VERSION 5.8 ;
BUSBITCHARS "[]" ;
DIVIDERCHAR "/" ;
UNITS
    DATABASE MICRONS 1000 ;
END UNITS

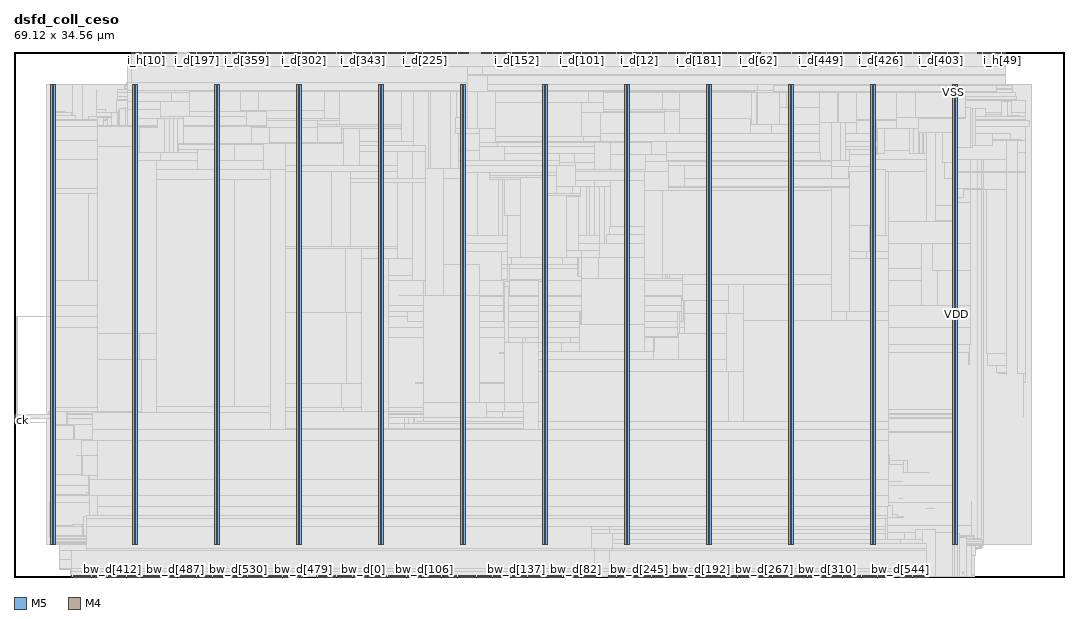
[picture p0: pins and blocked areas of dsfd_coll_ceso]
MACRO dsfd_coll_ceso
  FOREIGN dsfd_coll_ceso 0 0 ;
  CLASS BLOCK ;
  SIZE 69.12 BY 34.56 ;
  PIN bw_d[0]
    DIRECTION OUTPUT ;
    USE SIGNAL ;
    PORT
      LAYER M5 ;
        RECT  22.992 0 23.016 0.084 ;
    END
  END bw_d[0]
  PIN bw_d[100]
    DIRECTION OUTPUT ;
    USE SIGNAL ;
    PORT
      LAYER M5 ;
        RECT  26.448 0 26.472 0.084 ;
    END
  END bw_d[100]
  PIN bw_d[101]
    DIRECTION OUTPUT ;
    USE SIGNAL ;
    PORT
      LAYER M5 ;
        RECT  26.544 0 26.568 0.084 ;
    END
  END bw_d[101]
  PIN bw_d[102]
    DIRECTION OUTPUT ;
    USE SIGNAL ;
    PORT
      LAYER M5 ;
        RECT  26.64 0 26.664 0.084 ;
    END
  END bw_d[102]
  PIN bw_d[103]
    DIRECTION OUTPUT ;
    USE SIGNAL ;
    PORT
      LAYER M5 ;
        RECT  26.736 0 26.76 0.084 ;
    END
  END bw_d[103]
  PIN bw_d[104]
    DIRECTION OUTPUT ;
    USE SIGNAL ;
    PORT
      LAYER M5 ;
        RECT  26.832 0 26.856 0.084 ;
    END
  END bw_d[104]
  PIN bw_d[105]
    DIRECTION OUTPUT ;
    USE SIGNAL ;
    PORT
      LAYER M5 ;
        RECT  26.928 0 26.952 0.084 ;
    END
  END bw_d[105]
  PIN bw_d[106]
    DIRECTION OUTPUT ;
    USE SIGNAL ;
    PORT
      LAYER M5 ;
        RECT  27.024 0 27.048 0.084 ;
    END
  END bw_d[106]
  PIN bw_d[107]
    DIRECTION OUTPUT ;
    USE SIGNAL ;
    PORT
      LAYER M5 ;
        RECT  27.12 0 27.144 0.084 ;
    END
  END bw_d[107]
  PIN bw_d[108]
    DIRECTION OUTPUT ;
    USE SIGNAL ;
    PORT
      LAYER M5 ;
        RECT  27.216 0 27.24 0.084 ;
    END
  END bw_d[108]
  PIN bw_d[109]
    DIRECTION OUTPUT ;
    USE SIGNAL ;
    PORT
      LAYER M5 ;
        RECT  27.312 0 27.336 0.084 ;
    END
  END bw_d[109]
  PIN bw_d[10]
    DIRECTION OUTPUT ;
    USE SIGNAL ;
    PORT
      LAYER M5 ;
        RECT  23.952 0 23.976 0.084 ;
    END
  END bw_d[10]
  PIN bw_d[110]
    DIRECTION OUTPUT ;
    USE SIGNAL ;
    PORT
      LAYER M5 ;
        RECT  27.408 0 27.432 0.084 ;
    END
  END bw_d[110]
  PIN bw_d[111]
    DIRECTION OUTPUT ;
    USE SIGNAL ;
    PORT
      LAYER M5 ;
        RECT  27.504 0 27.528 0.084 ;
    END
  END bw_d[111]
  PIN bw_d[112]
    DIRECTION OUTPUT ;
    USE SIGNAL ;
    PORT
      LAYER M5 ;
        RECT  27.6 0 27.624 0.084 ;
    END
  END bw_d[112]
  PIN bw_d[113]
    DIRECTION OUTPUT ;
    USE SIGNAL ;
    PORT
      LAYER M5 ;
        RECT  27.696 0 27.72 0.084 ;
    END
  END bw_d[113]
  PIN bw_d[114]
    DIRECTION OUTPUT ;
    USE SIGNAL ;
    PORT
      LAYER M5 ;
        RECT  27.792 0 27.816 0.084 ;
    END
  END bw_d[114]
  PIN bw_d[115]
    DIRECTION OUTPUT ;
    USE SIGNAL ;
    PORT
      LAYER M5 ;
        RECT  27.888 0 27.912 0.084 ;
    END
  END bw_d[115]
  PIN bw_d[116]
    DIRECTION OUTPUT ;
    USE SIGNAL ;
    PORT
      LAYER M5 ;
        RECT  27.984 0 28.008 0.084 ;
    END
  END bw_d[116]
  PIN bw_d[117]
    DIRECTION OUTPUT ;
    USE SIGNAL ;
    PORT
      LAYER M5 ;
        RECT  28.08 0 28.104 0.084 ;
    END
  END bw_d[117]
  PIN bw_d[118]
    DIRECTION OUTPUT ;
    USE SIGNAL ;
    PORT
      LAYER M5 ;
        RECT  28.176 0 28.2 0.084 ;
    END
  END bw_d[118]
  PIN bw_d[119]
    DIRECTION OUTPUT ;
    USE SIGNAL ;
    PORT
      LAYER M5 ;
        RECT  28.272 0 28.296 0.084 ;
    END
  END bw_d[119]
  PIN bw_d[11]
    DIRECTION OUTPUT ;
    USE SIGNAL ;
    PORT
      LAYER M5 ;
        RECT  24.048 0 24.072 0.084 ;
    END
  END bw_d[11]
  PIN bw_d[120]
    DIRECTION OUTPUT ;
    USE SIGNAL ;
    PORT
      LAYER M5 ;
        RECT  28.368 0 28.392 0.084 ;
    END
  END bw_d[120]
  PIN bw_d[121]
    DIRECTION OUTPUT ;
    USE SIGNAL ;
    PORT
      LAYER M5 ;
        RECT  28.464 0 28.488 0.084 ;
    END
  END bw_d[121]
  PIN bw_d[122]
    DIRECTION OUTPUT ;
    USE SIGNAL ;
    PORT
      LAYER M5 ;
        RECT  28.56 0 28.584 0.084 ;
    END
  END bw_d[122]
  PIN bw_d[123]
    DIRECTION OUTPUT ;
    USE SIGNAL ;
    PORT
      LAYER M5 ;
        RECT  28.656 0 28.68 0.084 ;
    END
  END bw_d[123]
  PIN bw_d[124]
    DIRECTION OUTPUT ;
    USE SIGNAL ;
    PORT
      LAYER M5 ;
        RECT  28.752 0 28.776 0.084 ;
    END
  END bw_d[124]
  PIN bw_d[125]
    DIRECTION OUTPUT ;
    USE SIGNAL ;
    PORT
      LAYER M5 ;
        RECT  28.848 0 28.872 0.084 ;
    END
  END bw_d[125]
  PIN bw_d[126]
    DIRECTION OUTPUT ;
    USE SIGNAL ;
    PORT
      LAYER M5 ;
        RECT  28.944 0 28.968 0.084 ;
    END
  END bw_d[126]
  PIN bw_d[127]
    DIRECTION OUTPUT ;
    USE SIGNAL ;
    PORT
      LAYER M5 ;
        RECT  29.04 0 29.064 0.084 ;
    END
  END bw_d[127]
  PIN bw_d[128]
    DIRECTION OUTPUT ;
    USE SIGNAL ;
    PORT
      LAYER M5 ;
        RECT  32.208 0 32.232 0.084 ;
    END
  END bw_d[128]
  PIN bw_d[129]
    DIRECTION OUTPUT ;
    USE SIGNAL ;
    PORT
      LAYER M5 ;
        RECT  32.304 0 32.328 0.084 ;
    END
  END bw_d[129]
  PIN bw_d[12]
    DIRECTION OUTPUT ;
    USE SIGNAL ;
    PORT
      LAYER M5 ;
        RECT  24.144 0 24.168 0.084 ;
    END
  END bw_d[12]
  PIN bw_d[130]
    DIRECTION OUTPUT ;
    USE SIGNAL ;
    PORT
      LAYER M5 ;
        RECT  32.4 0 32.424 0.084 ;
    END
  END bw_d[130]
  PIN bw_d[131]
    DIRECTION OUTPUT ;
    USE SIGNAL ;
    PORT
      LAYER M5 ;
        RECT  32.496 0 32.52 0.084 ;
    END
  END bw_d[131]
  PIN bw_d[132]
    DIRECTION OUTPUT ;
    USE SIGNAL ;
    PORT
      LAYER M5 ;
        RECT  32.592 0 32.616 0.084 ;
    END
  END bw_d[132]
  PIN bw_d[133]
    DIRECTION OUTPUT ;
    USE SIGNAL ;
    PORT
      LAYER M5 ;
        RECT  32.688 0 32.712 0.084 ;
    END
  END bw_d[133]
  PIN bw_d[134]
    DIRECTION OUTPUT ;
    USE SIGNAL ;
    PORT
      LAYER M5 ;
        RECT  32.784 0 32.808 0.084 ;
    END
  END bw_d[134]
  PIN bw_d[135]
    DIRECTION OUTPUT ;
    USE SIGNAL ;
    PORT
      LAYER M5 ;
        RECT  32.88 0 32.904 0.084 ;
    END
  END bw_d[135]
  PIN bw_d[136]
    DIRECTION OUTPUT ;
    USE SIGNAL ;
    PORT
      LAYER M5 ;
        RECT  32.976 0 33 0.084 ;
    END
  END bw_d[136]
  PIN bw_d[137]
    DIRECTION OUTPUT ;
    USE SIGNAL ;
    PORT
      LAYER M5 ;
        RECT  33.072 0 33.096 0.084 ;
    END
  END bw_d[137]
  PIN bw_d[138]
    DIRECTION OUTPUT ;
    USE SIGNAL ;
    PORT
      LAYER M5 ;
        RECT  33.168 0 33.192 0.084 ;
    END
  END bw_d[138]
  PIN bw_d[139]
    DIRECTION OUTPUT ;
    USE SIGNAL ;
    PORT
      LAYER M5 ;
        RECT  33.264 0 33.288 0.084 ;
    END
  END bw_d[139]
  PIN bw_d[13]
    DIRECTION OUTPUT ;
    USE SIGNAL ;
    PORT
      LAYER M5 ;
        RECT  24.24 0 24.264 0.084 ;
    END
  END bw_d[13]
  PIN bw_d[140]
    DIRECTION OUTPUT ;
    USE SIGNAL ;
    PORT
      LAYER M5 ;
        RECT  33.36 0 33.384 0.084 ;
    END
  END bw_d[140]
  PIN bw_d[141]
    DIRECTION OUTPUT ;
    USE SIGNAL ;
    PORT
      LAYER M5 ;
        RECT  33.456 0 33.48 0.084 ;
    END
  END bw_d[141]
  PIN bw_d[142]
    DIRECTION OUTPUT ;
    USE SIGNAL ;
    PORT
      LAYER M5 ;
        RECT  33.552 0 33.576 0.084 ;
    END
  END bw_d[142]
  PIN bw_d[143]
    DIRECTION OUTPUT ;
    USE SIGNAL ;
    PORT
      LAYER M5 ;
        RECT  33.648 0 33.672 0.084 ;
    END
  END bw_d[143]
  PIN bw_d[144]
    DIRECTION OUTPUT ;
    USE SIGNAL ;
    PORT
      LAYER M5 ;
        RECT  33.744 0 33.768 0.084 ;
    END
  END bw_d[144]
  PIN bw_d[145]
    DIRECTION OUTPUT ;
    USE SIGNAL ;
    PORT
      LAYER M5 ;
        RECT  33.84 0 33.864 0.084 ;
    END
  END bw_d[145]
  PIN bw_d[146]
    DIRECTION OUTPUT ;
    USE SIGNAL ;
    PORT
      LAYER M5 ;
        RECT  33.936 0 33.96 0.084 ;
    END
  END bw_d[146]
  PIN bw_d[147]
    DIRECTION OUTPUT ;
    USE SIGNAL ;
    PORT
      LAYER M5 ;
        RECT  34.032 0 34.056 0.084 ;
    END
  END bw_d[147]
  PIN bw_d[148]
    DIRECTION OUTPUT ;
    USE SIGNAL ;
    PORT
      LAYER M5 ;
        RECT  34.128 0 34.152 0.084 ;
    END
  END bw_d[148]
  PIN bw_d[149]
    DIRECTION OUTPUT ;
    USE SIGNAL ;
    PORT
      LAYER M5 ;
        RECT  34.224 0 34.248 0.084 ;
    END
  END bw_d[149]
  PIN bw_d[14]
    DIRECTION OUTPUT ;
    USE SIGNAL ;
    PORT
      LAYER M5 ;
        RECT  24.336 0 24.36 0.084 ;
    END
  END bw_d[14]
  PIN bw_d[150]
    DIRECTION OUTPUT ;
    USE SIGNAL ;
    PORT
      LAYER M5 ;
        RECT  34.32 0 34.344 0.084 ;
    END
  END bw_d[150]
  PIN bw_d[151]
    DIRECTION OUTPUT ;
    USE SIGNAL ;
    PORT
      LAYER M5 ;
        RECT  34.416 0 34.44 0.084 ;
    END
  END bw_d[151]
  PIN bw_d[152]
    DIRECTION OUTPUT ;
    USE SIGNAL ;
    PORT
      LAYER M5 ;
        RECT  34.512 0 34.536 0.084 ;
    END
  END bw_d[152]
  PIN bw_d[153]
    DIRECTION OUTPUT ;
    USE SIGNAL ;
    PORT
      LAYER M5 ;
        RECT  34.608 0 34.632 0.084 ;
    END
  END bw_d[153]
  PIN bw_d[154]
    DIRECTION OUTPUT ;
    USE SIGNAL ;
    PORT
      LAYER M5 ;
        RECT  34.704 0 34.728 0.084 ;
    END
  END bw_d[154]
  PIN bw_d[155]
    DIRECTION OUTPUT ;
    USE SIGNAL ;
    PORT
      LAYER M5 ;
        RECT  34.8 0 34.824 0.084 ;
    END
  END bw_d[155]
  PIN bw_d[156]
    DIRECTION OUTPUT ;
    USE SIGNAL ;
    PORT
      LAYER M5 ;
        RECT  34.896 0 34.92 0.084 ;
    END
  END bw_d[156]
  PIN bw_d[157]
    DIRECTION OUTPUT ;
    USE SIGNAL ;
    PORT
      LAYER M5 ;
        RECT  34.992 0 35.016 0.084 ;
    END
  END bw_d[157]
  PIN bw_d[158]
    DIRECTION OUTPUT ;
    USE SIGNAL ;
    PORT
      LAYER M5 ;
        RECT  35.088 0 35.112 0.084 ;
    END
  END bw_d[158]
  PIN bw_d[159]
    DIRECTION OUTPUT ;
    USE SIGNAL ;
    PORT
      LAYER M5 ;
        RECT  35.184 0 35.208 0.084 ;
    END
  END bw_d[159]
  PIN bw_d[15]
    DIRECTION OUTPUT ;
    USE SIGNAL ;
    PORT
      LAYER M5 ;
        RECT  24.432 0 24.456 0.084 ;
    END
  END bw_d[15]
  PIN bw_d[160]
    DIRECTION OUTPUT ;
    USE SIGNAL ;
    PORT
      LAYER M5 ;
        RECT  29.136 0 29.16 0.084 ;
    END
  END bw_d[160]
  PIN bw_d[161]
    DIRECTION OUTPUT ;
    USE SIGNAL ;
    PORT
      LAYER M5 ;
        RECT  29.232 0 29.256 0.084 ;
    END
  END bw_d[161]
  PIN bw_d[162]
    DIRECTION OUTPUT ;
    USE SIGNAL ;
    PORT
      LAYER M5 ;
        RECT  29.328 0 29.352 0.084 ;
    END
  END bw_d[162]
  PIN bw_d[163]
    DIRECTION OUTPUT ;
    USE SIGNAL ;
    PORT
      LAYER M5 ;
        RECT  29.424 0 29.448 0.084 ;
    END
  END bw_d[163]
  PIN bw_d[164]
    DIRECTION OUTPUT ;
    USE SIGNAL ;
    PORT
      LAYER M5 ;
        RECT  29.52 0 29.544 0.084 ;
    END
  END bw_d[164]
  PIN bw_d[165]
    DIRECTION OUTPUT ;
    USE SIGNAL ;
    PORT
      LAYER M5 ;
        RECT  29.616 0 29.64 0.084 ;
    END
  END bw_d[165]
  PIN bw_d[166]
    DIRECTION OUTPUT ;
    USE SIGNAL ;
    PORT
      LAYER M5 ;
        RECT  29.712 0 29.736 0.084 ;
    END
  END bw_d[166]
  PIN bw_d[167]
    DIRECTION OUTPUT ;
    USE SIGNAL ;
    PORT
      LAYER M5 ;
        RECT  29.808 0 29.832 0.084 ;
    END
  END bw_d[167]
  PIN bw_d[168]
    DIRECTION OUTPUT ;
    USE SIGNAL ;
    PORT
      LAYER M5 ;
        RECT  29.904 0 29.928 0.084 ;
    END
  END bw_d[168]
  PIN bw_d[169]
    DIRECTION OUTPUT ;
    USE SIGNAL ;
    PORT
      LAYER M5 ;
        RECT  30 0 30.024 0.084 ;
    END
  END bw_d[169]
  PIN bw_d[16]
    DIRECTION OUTPUT ;
    USE SIGNAL ;
    PORT
      LAYER M5 ;
        RECT  24.528 0 24.552 0.084 ;
    END
  END bw_d[16]
  PIN bw_d[170]
    DIRECTION OUTPUT ;
    USE SIGNAL ;
    PORT
      LAYER M5 ;
        RECT  30.096 0 30.12 0.084 ;
    END
  END bw_d[170]
  PIN bw_d[171]
    DIRECTION OUTPUT ;
    USE SIGNAL ;
    PORT
      LAYER M5 ;
        RECT  30.192 0 30.216 0.084 ;
    END
  END bw_d[171]
  PIN bw_d[172]
    DIRECTION OUTPUT ;
    USE SIGNAL ;
    PORT
      LAYER M5 ;
        RECT  30.288 0 30.312 0.084 ;
    END
  END bw_d[172]
  PIN bw_d[173]
    DIRECTION OUTPUT ;
    USE SIGNAL ;
    PORT
      LAYER M5 ;
        RECT  30.384 0 30.408 0.084 ;
    END
  END bw_d[173]
  PIN bw_d[174]
    DIRECTION OUTPUT ;
    USE SIGNAL ;
    PORT
      LAYER M5 ;
        RECT  30.48 0 30.504 0.084 ;
    END
  END bw_d[174]
  PIN bw_d[175]
    DIRECTION OUTPUT ;
    USE SIGNAL ;
    PORT
      LAYER M5 ;
        RECT  30.576 0 30.6 0.084 ;
    END
  END bw_d[175]
  PIN bw_d[176]
    DIRECTION OUTPUT ;
    USE SIGNAL ;
    PORT
      LAYER M5 ;
        RECT  30.672 0 30.696 0.084 ;
    END
  END bw_d[176]
  PIN bw_d[177]
    DIRECTION OUTPUT ;
    USE SIGNAL ;
    PORT
      LAYER M5 ;
        RECT  30.768 0 30.792 0.084 ;
    END
  END bw_d[177]
  PIN bw_d[178]
    DIRECTION OUTPUT ;
    USE SIGNAL ;
    PORT
      LAYER M5 ;
        RECT  30.864 0 30.888 0.084 ;
    END
  END bw_d[178]
  PIN bw_d[179]
    DIRECTION OUTPUT ;
    USE SIGNAL ;
    PORT
      LAYER M5 ;
        RECT  30.96 0 30.984 0.084 ;
    END
  END bw_d[179]
  PIN bw_d[17]
    DIRECTION OUTPUT ;
    USE SIGNAL ;
    PORT
      LAYER M5 ;
        RECT  24.624 0 24.648 0.084 ;
    END
  END bw_d[17]
  PIN bw_d[180]
    DIRECTION OUTPUT ;
    USE SIGNAL ;
    PORT
      LAYER M5 ;
        RECT  31.056 0 31.08 0.084 ;
    END
  END bw_d[180]
  PIN bw_d[181]
    DIRECTION OUTPUT ;
    USE SIGNAL ;
    PORT
      LAYER M5 ;
        RECT  31.152 0 31.176 0.084 ;
    END
  END bw_d[181]
  PIN bw_d[182]
    DIRECTION OUTPUT ;
    USE SIGNAL ;
    PORT
      LAYER M5 ;
        RECT  31.248 0 31.272 0.084 ;
    END
  END bw_d[182]
  PIN bw_d[183]
    DIRECTION OUTPUT ;
    USE SIGNAL ;
    PORT
      LAYER M5 ;
        RECT  31.344 0 31.368 0.084 ;
    END
  END bw_d[183]
  PIN bw_d[184]
    DIRECTION OUTPUT ;
    USE SIGNAL ;
    PORT
      LAYER M5 ;
        RECT  31.44 0 31.464 0.084 ;
    END
  END bw_d[184]
  PIN bw_d[185]
    DIRECTION OUTPUT ;
    USE SIGNAL ;
    PORT
      LAYER M5 ;
        RECT  31.536 0 31.56 0.084 ;
    END
  END bw_d[185]
  PIN bw_d[186]
    DIRECTION OUTPUT ;
    USE SIGNAL ;
    PORT
      LAYER M5 ;
        RECT  31.632 0 31.656 0.084 ;
    END
  END bw_d[186]
  PIN bw_d[187]
    DIRECTION OUTPUT ;
    USE SIGNAL ;
    PORT
      LAYER M5 ;
        RECT  31.728 0 31.752 0.084 ;
    END
  END bw_d[187]
  PIN bw_d[188]
    DIRECTION OUTPUT ;
    USE SIGNAL ;
    PORT
      LAYER M5 ;
        RECT  31.824 0 31.848 0.084 ;
    END
  END bw_d[188]
  PIN bw_d[189]
    DIRECTION OUTPUT ;
    USE SIGNAL ;
    PORT
      LAYER M5 ;
        RECT  31.92 0 31.944 0.084 ;
    END
  END bw_d[189]
  PIN bw_d[18]
    DIRECTION OUTPUT ;
    USE SIGNAL ;
    PORT
      LAYER M5 ;
        RECT  24.72 0 24.744 0.084 ;
    END
  END bw_d[18]
  PIN bw_d[190]
    DIRECTION OUTPUT ;
    USE SIGNAL ;
    PORT
      LAYER M5 ;
        RECT  32.016 0 32.04 0.084 ;
    END
  END bw_d[190]
  PIN bw_d[191]
    DIRECTION OUTPUT ;
    USE SIGNAL ;
    PORT
      LAYER M5 ;
        RECT  32.112 0 32.136 0.084 ;
    END
  END bw_d[191]
  PIN bw_d[192]
    DIRECTION OUTPUT ;
    USE SIGNAL ;
    PORT
      LAYER M5 ;
        RECT  45.264 0 45.288 0.084 ;
    END
  END bw_d[192]
  PIN bw_d[193]
    DIRECTION OUTPUT ;
    USE SIGNAL ;
    PORT
      LAYER M5 ;
        RECT  45.36 0 45.384 0.084 ;
    END
  END bw_d[193]
  PIN bw_d[194]
    DIRECTION OUTPUT ;
    USE SIGNAL ;
    PORT
      LAYER M5 ;
        RECT  45.456 0 45.48 0.084 ;
    END
  END bw_d[194]
  PIN bw_d[195]
    DIRECTION OUTPUT ;
    USE SIGNAL ;
    PORT
      LAYER M5 ;
        RECT  45.552 0 45.576 0.084 ;
    END
  END bw_d[195]
  PIN bw_d[196]
    DIRECTION OUTPUT ;
    USE SIGNAL ;
    PORT
      LAYER M5 ;
        RECT  45.648 0 45.672 0.084 ;
    END
  END bw_d[196]
  PIN bw_d[197]
    DIRECTION OUTPUT ;
    USE SIGNAL ;
    PORT
      LAYER M5 ;
        RECT  45.744 0 45.768 0.084 ;
    END
  END bw_d[197]
  PIN bw_d[198]
    DIRECTION OUTPUT ;
    USE SIGNAL ;
    PORT
      LAYER M5 ;
        RECT  45.84 0 45.864 0.084 ;
    END
  END bw_d[198]
  PIN bw_d[199]
    DIRECTION OUTPUT ;
    USE SIGNAL ;
    PORT
      LAYER M5 ;
        RECT  45.936 0 45.96 0.084 ;
    END
  END bw_d[199]
  PIN bw_d[19]
    DIRECTION OUTPUT ;
    USE SIGNAL ;
    PORT
      LAYER M5 ;
        RECT  24.816 0 24.84 0.084 ;
    END
  END bw_d[19]
  PIN bw_d[1]
    DIRECTION OUTPUT ;
    USE SIGNAL ;
    PORT
      LAYER M5 ;
        RECT  23.088 0 23.112 0.084 ;
    END
  END bw_d[1]
  PIN bw_d[200]
    DIRECTION OUTPUT ;
    USE SIGNAL ;
    PORT
      LAYER M5 ;
        RECT  46.032 0 46.056 0.084 ;
    END
  END bw_d[200]
  PIN bw_d[201]
    DIRECTION OUTPUT ;
    USE SIGNAL ;
    PORT
      LAYER M5 ;
        RECT  46.128 0 46.152 0.084 ;
    END
  END bw_d[201]
  PIN bw_d[202]
    DIRECTION OUTPUT ;
    USE SIGNAL ;
    PORT
      LAYER M5 ;
        RECT  46.224 0 46.248 0.084 ;
    END
  END bw_d[202]
  PIN bw_d[203]
    DIRECTION OUTPUT ;
    USE SIGNAL ;
    PORT
      LAYER M5 ;
        RECT  46.32 0 46.344 0.084 ;
    END
  END bw_d[203]
  PIN bw_d[204]
    DIRECTION OUTPUT ;
    USE SIGNAL ;
    PORT
      LAYER M5 ;
        RECT  46.416 0 46.44 0.084 ;
    END
  END bw_d[204]
  PIN bw_d[205]
    DIRECTION OUTPUT ;
    USE SIGNAL ;
    PORT
      LAYER M5 ;
        RECT  46.512 0 46.536 0.084 ;
    END
  END bw_d[205]
  PIN bw_d[206]
    DIRECTION OUTPUT ;
    USE SIGNAL ;
    PORT
      LAYER M5 ;
        RECT  46.608 0 46.632 0.084 ;
    END
  END bw_d[206]
  PIN bw_d[207]
    DIRECTION OUTPUT ;
    USE SIGNAL ;
    PORT
      LAYER M5 ;
        RECT  46.704 0 46.728 0.084 ;
    END
  END bw_d[207]
  PIN bw_d[208]
    DIRECTION OUTPUT ;
    USE SIGNAL ;
    PORT
      LAYER M5 ;
        RECT  46.8 0 46.824 0.084 ;
    END
  END bw_d[208]
  PIN bw_d[209]
    DIRECTION OUTPUT ;
    USE SIGNAL ;
    PORT
      LAYER M5 ;
        RECT  46.896 0 46.92 0.084 ;
    END
  END bw_d[209]
  PIN bw_d[20]
    DIRECTION OUTPUT ;
    USE SIGNAL ;
    PORT
      LAYER M5 ;
        RECT  24.912 0 24.936 0.084 ;
    END
  END bw_d[20]
  PIN bw_d[210]
    DIRECTION OUTPUT ;
    USE SIGNAL ;
    PORT
      LAYER M5 ;
        RECT  46.992 0 47.016 0.084 ;
    END
  END bw_d[210]
  PIN bw_d[211]
    DIRECTION OUTPUT ;
    USE SIGNAL ;
    PORT
      LAYER M5 ;
        RECT  47.088 0 47.112 0.084 ;
    END
  END bw_d[211]
  PIN bw_d[212]
    DIRECTION OUTPUT ;
    USE SIGNAL ;
    PORT
      LAYER M5 ;
        RECT  47.184 0 47.208 0.084 ;
    END
  END bw_d[212]
  PIN bw_d[213]
    DIRECTION OUTPUT ;
    USE SIGNAL ;
    PORT
      LAYER M5 ;
        RECT  47.28 0 47.304 0.084 ;
    END
  END bw_d[213]
  PIN bw_d[214]
    DIRECTION OUTPUT ;
    USE SIGNAL ;
    PORT
      LAYER M5 ;
        RECT  47.376 0 47.4 0.084 ;
    END
  END bw_d[214]
  PIN bw_d[215]
    DIRECTION OUTPUT ;
    USE SIGNAL ;
    PORT
      LAYER M5 ;
        RECT  47.472 0 47.496 0.084 ;
    END
  END bw_d[215]
  PIN bw_d[216]
    DIRECTION OUTPUT ;
    USE SIGNAL ;
    PORT
      LAYER M5 ;
        RECT  47.568 0 47.592 0.084 ;
    END
  END bw_d[216]
  PIN bw_d[217]
    DIRECTION OUTPUT ;
    USE SIGNAL ;
    PORT
      LAYER M5 ;
        RECT  47.664 0 47.688 0.084 ;
    END
  END bw_d[217]
  PIN bw_d[218]
    DIRECTION OUTPUT ;
    USE SIGNAL ;
    PORT
      LAYER M5 ;
        RECT  47.76 0 47.784 0.084 ;
    END
  END bw_d[218]
  PIN bw_d[219]
    DIRECTION OUTPUT ;
    USE SIGNAL ;
    PORT
      LAYER M5 ;
        RECT  47.856 0 47.88 0.084 ;
    END
  END bw_d[219]
  PIN bw_d[21]
    DIRECTION OUTPUT ;
    USE SIGNAL ;
    PORT
      LAYER M5 ;
        RECT  25.008 0 25.032 0.084 ;
    END
  END bw_d[21]
  PIN bw_d[220]
    DIRECTION OUTPUT ;
    USE SIGNAL ;
    PORT
      LAYER M5 ;
        RECT  47.952 0 47.976 0.084 ;
    END
  END bw_d[220]
  PIN bw_d[221]
    DIRECTION OUTPUT ;
    USE SIGNAL ;
    PORT
      LAYER M5 ;
        RECT  48.048 0 48.072 0.084 ;
    END
  END bw_d[221]
  PIN bw_d[222]
    DIRECTION OUTPUT ;
    USE SIGNAL ;
    PORT
      LAYER M5 ;
        RECT  48.144 0 48.168 0.084 ;
    END
  END bw_d[222]
  PIN bw_d[223]
    DIRECTION OUTPUT ;
    USE SIGNAL ;
    PORT
      LAYER M5 ;
        RECT  48.24 0 48.264 0.084 ;
    END
  END bw_d[223]
  PIN bw_d[224]
    DIRECTION OUTPUT ;
    USE SIGNAL ;
    PORT
      LAYER M5 ;
        RECT  39.12 0 39.144 0.084 ;
    END
  END bw_d[224]
  PIN bw_d[225]
    DIRECTION OUTPUT ;
    USE SIGNAL ;
    PORT
      LAYER M5 ;
        RECT  39.216 0 39.24 0.084 ;
    END
  END bw_d[225]
  PIN bw_d[226]
    DIRECTION OUTPUT ;
    USE SIGNAL ;
    PORT
      LAYER M5 ;
        RECT  39.312 0 39.336 0.084 ;
    END
  END bw_d[226]
  PIN bw_d[227]
    DIRECTION OUTPUT ;
    USE SIGNAL ;
    PORT
      LAYER M5 ;
        RECT  39.408 0 39.432 0.084 ;
    END
  END bw_d[227]
  PIN bw_d[228]
    DIRECTION OUTPUT ;
    USE SIGNAL ;
    PORT
      LAYER M5 ;
        RECT  39.504 0 39.528 0.084 ;
    END
  END bw_d[228]
  PIN bw_d[229]
    DIRECTION OUTPUT ;
    USE SIGNAL ;
    PORT
      LAYER M5 ;
        RECT  39.6 0 39.624 0.084 ;
    END
  END bw_d[229]
  PIN bw_d[22]
    DIRECTION OUTPUT ;
    USE SIGNAL ;
    PORT
      LAYER M5 ;
        RECT  25.104 0 25.128 0.084 ;
    END
  END bw_d[22]
  PIN bw_d[230]
    DIRECTION OUTPUT ;
    USE SIGNAL ;
    PORT
      LAYER M5 ;
        RECT  39.696 0 39.72 0.084 ;
    END
  END bw_d[230]
  PIN bw_d[231]
    DIRECTION OUTPUT ;
    USE SIGNAL ;
    PORT
      LAYER M5 ;
        RECT  39.792 0 39.816 0.084 ;
    END
  END bw_d[231]
  PIN bw_d[232]
    DIRECTION OUTPUT ;
    USE SIGNAL ;
    PORT
      LAYER M5 ;
        RECT  39.888 0 39.912 0.084 ;
    END
  END bw_d[232]
  PIN bw_d[233]
    DIRECTION OUTPUT ;
    USE SIGNAL ;
    PORT
      LAYER M5 ;
        RECT  39.984 0 40.008 0.084 ;
    END
  END bw_d[233]
  PIN bw_d[234]
    DIRECTION OUTPUT ;
    USE SIGNAL ;
    PORT
      LAYER M5 ;
        RECT  40.08 0 40.104 0.084 ;
    END
  END bw_d[234]
  PIN bw_d[235]
    DIRECTION OUTPUT ;
    USE SIGNAL ;
    PORT
      LAYER M5 ;
        RECT  40.176 0 40.2 0.084 ;
    END
  END bw_d[235]
  PIN bw_d[236]
    DIRECTION OUTPUT ;
    USE SIGNAL ;
    PORT
      LAYER M5 ;
        RECT  40.272 0 40.296 0.084 ;
    END
  END bw_d[236]
  PIN bw_d[237]
    DIRECTION OUTPUT ;
    USE SIGNAL ;
    PORT
      LAYER M5 ;
        RECT  40.368 0 40.392 0.084 ;
    END
  END bw_d[237]
  PIN bw_d[238]
    DIRECTION OUTPUT ;
    USE SIGNAL ;
    PORT
      LAYER M5 ;
        RECT  40.464 0 40.488 0.084 ;
    END
  END bw_d[238]
  PIN bw_d[239]
    DIRECTION OUTPUT ;
    USE SIGNAL ;
    PORT
      LAYER M5 ;
        RECT  40.56 0 40.584 0.084 ;
    END
  END bw_d[239]
  PIN bw_d[23]
    DIRECTION OUTPUT ;
    USE SIGNAL ;
    PORT
      LAYER M5 ;
        RECT  25.2 0 25.224 0.084 ;
    END
  END bw_d[23]
  PIN bw_d[240]
    DIRECTION OUTPUT ;
    USE SIGNAL ;
    PORT
      LAYER M5 ;
        RECT  40.656 0 40.68 0.084 ;
    END
  END bw_d[240]
  PIN bw_d[241]
    DIRECTION OUTPUT ;
    USE SIGNAL ;
    PORT
      LAYER M5 ;
        RECT  40.752 0 40.776 0.084 ;
    END
  END bw_d[241]
  PIN bw_d[242]
    DIRECTION OUTPUT ;
    USE SIGNAL ;
    PORT
      LAYER M5 ;
        RECT  40.848 0 40.872 0.084 ;
    END
  END bw_d[242]
  PIN bw_d[243]
    DIRECTION OUTPUT ;
    USE SIGNAL ;
    PORT
      LAYER M5 ;
        RECT  40.944 0 40.968 0.084 ;
    END
  END bw_d[243]
  PIN bw_d[244]
    DIRECTION OUTPUT ;
    USE SIGNAL ;
    PORT
      LAYER M5 ;
        RECT  41.04 0 41.064 0.084 ;
    END
  END bw_d[244]
  PIN bw_d[245]
    DIRECTION OUTPUT ;
    USE SIGNAL ;
    PORT
      LAYER M5 ;
        RECT  41.136 0 41.16 0.084 ;
    END
  END bw_d[245]
  PIN bw_d[246]
    DIRECTION OUTPUT ;
    USE SIGNAL ;
    PORT
      LAYER M5 ;
        RECT  41.232 0 41.256 0.084 ;
    END
  END bw_d[246]
  PIN bw_d[247]
    DIRECTION OUTPUT ;
    USE SIGNAL ;
    PORT
      LAYER M5 ;
        RECT  41.328 0 41.352 0.084 ;
    END
  END bw_d[247]
  PIN bw_d[248]
    DIRECTION OUTPUT ;
    USE SIGNAL ;
    PORT
      LAYER M5 ;
        RECT  41.424 0 41.448 0.084 ;
    END
  END bw_d[248]
  PIN bw_d[249]
    DIRECTION OUTPUT ;
    USE SIGNAL ;
    PORT
      LAYER M5 ;
        RECT  41.52 0 41.544 0.084 ;
    END
  END bw_d[249]
  PIN bw_d[24]
    DIRECTION OUTPUT ;
    USE SIGNAL ;
    PORT
      LAYER M5 ;
        RECT  25.296 0 25.32 0.084 ;
    END
  END bw_d[24]
  PIN bw_d[250]
    DIRECTION OUTPUT ;
    USE SIGNAL ;
    PORT
      LAYER M5 ;
        RECT  41.616 0 41.64 0.084 ;
    END
  END bw_d[250]
  PIN bw_d[251]
    DIRECTION OUTPUT ;
    USE SIGNAL ;
    PORT
      LAYER M5 ;
        RECT  41.712 0 41.736 0.084 ;
    END
  END bw_d[251]
  PIN bw_d[252]
    DIRECTION OUTPUT ;
    USE SIGNAL ;
    PORT
      LAYER M5 ;
        RECT  41.808 0 41.832 0.084 ;
    END
  END bw_d[252]
  PIN bw_d[253]
    DIRECTION OUTPUT ;
    USE SIGNAL ;
    PORT
      LAYER M5 ;
        RECT  41.904 0 41.928 0.084 ;
    END
  END bw_d[253]
  PIN bw_d[254]
    DIRECTION OUTPUT ;
    USE SIGNAL ;
    PORT
      LAYER M5 ;
        RECT  42 0 42.024 0.084 ;
    END
  END bw_d[254]
  PIN bw_d[255]
    DIRECTION OUTPUT ;
    USE SIGNAL ;
    PORT
      LAYER M5 ;
        RECT  42.096 0 42.12 0.084 ;
    END
  END bw_d[255]
  PIN bw_d[256]
    DIRECTION OUTPUT ;
    USE SIGNAL ;
    PORT
      LAYER M5 ;
        RECT  48.336 0 48.36 0.084 ;
    END
  END bw_d[256]
  PIN bw_d[257]
    DIRECTION OUTPUT ;
    USE SIGNAL ;
    PORT
      LAYER M5 ;
        RECT  48.432 0 48.456 0.084 ;
    END
  END bw_d[257]
  PIN bw_d[258]
    DIRECTION OUTPUT ;
    USE SIGNAL ;
    PORT
      LAYER M5 ;
        RECT  48.528 0 48.552 0.084 ;
    END
  END bw_d[258]
  PIN bw_d[259]
    DIRECTION OUTPUT ;
    USE SIGNAL ;
    PORT
      LAYER M5 ;
        RECT  48.624 0 48.648 0.084 ;
    END
  END bw_d[259]
  PIN bw_d[25]
    DIRECTION OUTPUT ;
    USE SIGNAL ;
    PORT
      LAYER M5 ;
        RECT  25.392 0 25.416 0.084 ;
    END
  END bw_d[25]
  PIN bw_d[260]
    DIRECTION OUTPUT ;
    USE SIGNAL ;
    PORT
      LAYER M5 ;
        RECT  48.72 0 48.744 0.084 ;
    END
  END bw_d[260]
  PIN bw_d[261]
    DIRECTION OUTPUT ;
    USE SIGNAL ;
    PORT
      LAYER M5 ;
        RECT  48.816 0 48.84 0.084 ;
    END
  END bw_d[261]
  PIN bw_d[262]
    DIRECTION OUTPUT ;
    USE SIGNAL ;
    PORT
      LAYER M5 ;
        RECT  48.912 0 48.936 0.084 ;
    END
  END bw_d[262]
  PIN bw_d[263]
    DIRECTION OUTPUT ;
    USE SIGNAL ;
    PORT
      LAYER M5 ;
        RECT  49.008 0 49.032 0.084 ;
    END
  END bw_d[263]
  PIN bw_d[264]
    DIRECTION OUTPUT ;
    USE SIGNAL ;
    PORT
      LAYER M5 ;
        RECT  49.104 0 49.128 0.084 ;
    END
  END bw_d[264]
  PIN bw_d[265]
    DIRECTION OUTPUT ;
    USE SIGNAL ;
    PORT
      LAYER M5 ;
        RECT  49.2 0 49.224 0.084 ;
    END
  END bw_d[265]
  PIN bw_d[266]
    DIRECTION OUTPUT ;
    USE SIGNAL ;
    PORT
      LAYER M5 ;
        RECT  49.296 0 49.32 0.084 ;
    END
  END bw_d[266]
  PIN bw_d[267]
    DIRECTION OUTPUT ;
    USE SIGNAL ;
    PORT
      LAYER M5 ;
        RECT  49.392 0 49.416 0.084 ;
    END
  END bw_d[267]
  PIN bw_d[268]
    DIRECTION OUTPUT ;
    USE SIGNAL ;
    PORT
      LAYER M5 ;
        RECT  49.488 0 49.512 0.084 ;
    END
  END bw_d[268]
  PIN bw_d[269]
    DIRECTION OUTPUT ;
    USE SIGNAL ;
    PORT
      LAYER M5 ;
        RECT  49.584 0 49.608 0.084 ;
    END
  END bw_d[269]
  PIN bw_d[26]
    DIRECTION OUTPUT ;
    USE SIGNAL ;
    PORT
      LAYER M5 ;
        RECT  25.488 0 25.512 0.084 ;
    END
  END bw_d[26]
  PIN bw_d[270]
    DIRECTION OUTPUT ;
    USE SIGNAL ;
    PORT
      LAYER M5 ;
        RECT  49.68 0 49.704 0.084 ;
    END
  END bw_d[270]
  PIN bw_d[271]
    DIRECTION OUTPUT ;
    USE SIGNAL ;
    PORT
      LAYER M5 ;
        RECT  49.776 0 49.8 0.084 ;
    END
  END bw_d[271]
  PIN bw_d[272]
    DIRECTION OUTPUT ;
    USE SIGNAL ;
    PORT
      LAYER M5 ;
        RECT  49.872 0 49.896 0.084 ;
    END
  END bw_d[272]
  PIN bw_d[273]
    DIRECTION OUTPUT ;
    USE SIGNAL ;
    PORT
      LAYER M5 ;
        RECT  49.968 0 49.992 0.084 ;
    END
  END bw_d[273]
  PIN bw_d[274]
    DIRECTION OUTPUT ;
    USE SIGNAL ;
    PORT
      LAYER M5 ;
        RECT  50.064 0 50.088 0.084 ;
    END
  END bw_d[274]
  PIN bw_d[275]
    DIRECTION OUTPUT ;
    USE SIGNAL ;
    PORT
      LAYER M5 ;
        RECT  50.16 0 50.184 0.084 ;
    END
  END bw_d[275]
  PIN bw_d[276]
    DIRECTION OUTPUT ;
    USE SIGNAL ;
    PORT
      LAYER M5 ;
        RECT  50.256 0 50.28 0.084 ;
    END
  END bw_d[276]
  PIN bw_d[277]
    DIRECTION OUTPUT ;
    USE SIGNAL ;
    PORT
      LAYER M5 ;
        RECT  50.352 0 50.376 0.084 ;
    END
  END bw_d[277]
  PIN bw_d[278]
    DIRECTION OUTPUT ;
    USE SIGNAL ;
    PORT
      LAYER M5 ;
        RECT  50.448 0 50.472 0.084 ;
    END
  END bw_d[278]
  PIN bw_d[279]
    DIRECTION OUTPUT ;
    USE SIGNAL ;
    PORT
      LAYER M5 ;
        RECT  50.544 0 50.568 0.084 ;
    END
  END bw_d[279]
  PIN bw_d[27]
    DIRECTION OUTPUT ;
    USE SIGNAL ;
    PORT
      LAYER M5 ;
        RECT  25.584 0 25.608 0.084 ;
    END
  END bw_d[27]
  PIN bw_d[280]
    DIRECTION OUTPUT ;
    USE SIGNAL ;
    PORT
      LAYER M5 ;
        RECT  50.64 0 50.664 0.084 ;
    END
  END bw_d[280]
  PIN bw_d[281]
    DIRECTION OUTPUT ;
    USE SIGNAL ;
    PORT
      LAYER M5 ;
        RECT  50.736 0 50.76 0.084 ;
    END
  END bw_d[281]
  PIN bw_d[282]
    DIRECTION OUTPUT ;
    USE SIGNAL ;
    PORT
      LAYER M5 ;
        RECT  50.832 0 50.856 0.084 ;
    END
  END bw_d[282]
  PIN bw_d[283]
    DIRECTION OUTPUT ;
    USE SIGNAL ;
    PORT
      LAYER M5 ;
        RECT  50.928 0 50.952 0.084 ;
    END
  END bw_d[283]
  PIN bw_d[284]
    DIRECTION OUTPUT ;
    USE SIGNAL ;
    PORT
      LAYER M5 ;
        RECT  51.024 0 51.048 0.084 ;
    END
  END bw_d[284]
  PIN bw_d[285]
    DIRECTION OUTPUT ;
    USE SIGNAL ;
    PORT
      LAYER M5 ;
        RECT  51.12 0 51.144 0.084 ;
    END
  END bw_d[285]
  PIN bw_d[286]
    DIRECTION OUTPUT ;
    USE SIGNAL ;
    PORT
      LAYER M5 ;
        RECT  51.216 0 51.24 0.084 ;
    END
  END bw_d[286]
  PIN bw_d[287]
    DIRECTION OUTPUT ;
    USE SIGNAL ;
    PORT
      LAYER M5 ;
        RECT  51.312 0 51.336 0.084 ;
    END
  END bw_d[287]
  PIN bw_d[288]
    DIRECTION OUTPUT ;
    USE SIGNAL ;
    PORT
      LAYER M5 ;
        RECT  51.408 0 51.432 0.084 ;
    END
  END bw_d[288]
  PIN bw_d[289]
    DIRECTION OUTPUT ;
    USE SIGNAL ;
    PORT
      LAYER M5 ;
        RECT  51.504 0 51.528 0.084 ;
    END
  END bw_d[289]
  PIN bw_d[28]
    DIRECTION OUTPUT ;
    USE SIGNAL ;
    PORT
      LAYER M5 ;
        RECT  25.68 0 25.704 0.084 ;
    END
  END bw_d[28]
  PIN bw_d[290]
    DIRECTION OUTPUT ;
    USE SIGNAL ;
    PORT
      LAYER M5 ;
        RECT  51.6 0 51.624 0.084 ;
    END
  END bw_d[290]
  PIN bw_d[291]
    DIRECTION OUTPUT ;
    USE SIGNAL ;
    PORT
      LAYER M5 ;
        RECT  51.696 0 51.72 0.084 ;
    END
  END bw_d[291]
  PIN bw_d[292]
    DIRECTION OUTPUT ;
    USE SIGNAL ;
    PORT
      LAYER M5 ;
        RECT  51.792 0 51.816 0.084 ;
    END
  END bw_d[292]
  PIN bw_d[293]
    DIRECTION OUTPUT ;
    USE SIGNAL ;
    PORT
      LAYER M5 ;
        RECT  51.888 0 51.912 0.084 ;
    END
  END bw_d[293]
  PIN bw_d[294]
    DIRECTION OUTPUT ;
    USE SIGNAL ;
    PORT
      LAYER M5 ;
        RECT  51.984 0 52.008 0.084 ;
    END
  END bw_d[294]
  PIN bw_d[295]
    DIRECTION OUTPUT ;
    USE SIGNAL ;
    PORT
      LAYER M5 ;
        RECT  52.08 0 52.104 0.084 ;
    END
  END bw_d[295]
  PIN bw_d[296]
    DIRECTION OUTPUT ;
    USE SIGNAL ;
    PORT
      LAYER M5 ;
        RECT  52.176 0 52.2 0.084 ;
    END
  END bw_d[296]
  PIN bw_d[297]
    DIRECTION OUTPUT ;
    USE SIGNAL ;
    PORT
      LAYER M5 ;
        RECT  52.272 0 52.296 0.084 ;
    END
  END bw_d[297]
  PIN bw_d[298]
    DIRECTION OUTPUT ;
    USE SIGNAL ;
    PORT
      LAYER M5 ;
        RECT  52.368 0 52.392 0.084 ;
    END
  END bw_d[298]
  PIN bw_d[299]
    DIRECTION OUTPUT ;
    USE SIGNAL ;
    PORT
      LAYER M5 ;
        RECT  52.464 0 52.488 0.084 ;
    END
  END bw_d[299]
  PIN bw_d[29]
    DIRECTION OUTPUT ;
    USE SIGNAL ;
    PORT
      LAYER M5 ;
        RECT  25.776 0 25.8 0.084 ;
    END
  END bw_d[29]
  PIN bw_d[2]
    DIRECTION OUTPUT ;
    USE SIGNAL ;
    PORT
      LAYER M5 ;
        RECT  23.184 0 23.208 0.084 ;
    END
  END bw_d[2]
  PIN bw_d[300]
    DIRECTION OUTPUT ;
    USE SIGNAL ;
    PORT
      LAYER M5 ;
        RECT  52.56 0 52.584 0.084 ;
    END
  END bw_d[300]
  PIN bw_d[301]
    DIRECTION OUTPUT ;
    USE SIGNAL ;
    PORT
      LAYER M5 ;
        RECT  52.656 0 52.68 0.084 ;
    END
  END bw_d[301]
  PIN bw_d[302]
    DIRECTION OUTPUT ;
    USE SIGNAL ;
    PORT
      LAYER M5 ;
        RECT  52.752 0 52.776 0.084 ;
    END
  END bw_d[302]
  PIN bw_d[303]
    DIRECTION OUTPUT ;
    USE SIGNAL ;
    PORT
      LAYER M5 ;
        RECT  52.848 0 52.872 0.084 ;
    END
  END bw_d[303]
  PIN bw_d[304]
    DIRECTION OUTPUT ;
    USE SIGNAL ;
    PORT
      LAYER M5 ;
        RECT  52.944 0 52.968 0.084 ;
    END
  END bw_d[304]
  PIN bw_d[305]
    DIRECTION OUTPUT ;
    USE SIGNAL ;
    PORT
      LAYER M5 ;
        RECT  53.04 0 53.064 0.084 ;
    END
  END bw_d[305]
  PIN bw_d[306]
    DIRECTION OUTPUT ;
    USE SIGNAL ;
    PORT
      LAYER M5 ;
        RECT  53.136 0 53.16 0.084 ;
    END
  END bw_d[306]
  PIN bw_d[307]
    DIRECTION OUTPUT ;
    USE SIGNAL ;
    PORT
      LAYER M5 ;
        RECT  53.232 0 53.256 0.084 ;
    END
  END bw_d[307]
  PIN bw_d[308]
    DIRECTION OUTPUT ;
    USE SIGNAL ;
    PORT
      LAYER M5 ;
        RECT  53.328 0 53.352 0.084 ;
    END
  END bw_d[308]
  PIN bw_d[309]
    DIRECTION OUTPUT ;
    USE SIGNAL ;
    PORT
      LAYER M5 ;
        RECT  53.424 0 53.448 0.084 ;
    END
  END bw_d[309]
  PIN bw_d[30]
    DIRECTION OUTPUT ;
    USE SIGNAL ;
    PORT
      LAYER M5 ;
        RECT  25.872 0 25.896 0.084 ;
    END
  END bw_d[30]
  PIN bw_d[310]
    DIRECTION OUTPUT ;
    USE SIGNAL ;
    PORT
      LAYER M5 ;
        RECT  53.52 0 53.544 0.084 ;
    END
  END bw_d[310]
  PIN bw_d[311]
    DIRECTION OUTPUT ;
    USE SIGNAL ;
    PORT
      LAYER M5 ;
        RECT  53.616 0 53.64 0.084 ;
    END
  END bw_d[311]
  PIN bw_d[312]
    DIRECTION OUTPUT ;
    USE SIGNAL ;
    PORT
      LAYER M5 ;
        RECT  53.712 0 53.736 0.084 ;
    END
  END bw_d[312]
  PIN bw_d[313]
    DIRECTION OUTPUT ;
    USE SIGNAL ;
    PORT
      LAYER M5 ;
        RECT  53.808 0 53.832 0.084 ;
    END
  END bw_d[313]
  PIN bw_d[314]
    DIRECTION OUTPUT ;
    USE SIGNAL ;
    PORT
      LAYER M5 ;
        RECT  53.904 0 53.928 0.084 ;
    END
  END bw_d[314]
  PIN bw_d[315]
    DIRECTION OUTPUT ;
    USE SIGNAL ;
    PORT
      LAYER M5 ;
        RECT  54 0 54.024 0.084 ;
    END
  END bw_d[315]
  PIN bw_d[316]
    DIRECTION OUTPUT ;
    USE SIGNAL ;
    PORT
      LAYER M5 ;
        RECT  54.096 0 54.12 0.084 ;
    END
  END bw_d[316]
  PIN bw_d[317]
    DIRECTION OUTPUT ;
    USE SIGNAL ;
    PORT
      LAYER M5 ;
        RECT  54.192 0 54.216 0.084 ;
    END
  END bw_d[317]
  PIN bw_d[318]
    DIRECTION OUTPUT ;
    USE SIGNAL ;
    PORT
      LAYER M5 ;
        RECT  54.288 0 54.312 0.084 ;
    END
  END bw_d[318]
  PIN bw_d[319]
    DIRECTION OUTPUT ;
    USE SIGNAL ;
    PORT
      LAYER M5 ;
        RECT  54.384 0 54.408 0.084 ;
    END
  END bw_d[319]
  PIN bw_d[31]
    DIRECTION OUTPUT ;
    USE SIGNAL ;
    PORT
      LAYER M5 ;
        RECT  25.968 0 25.992 0.084 ;
    END
  END bw_d[31]
  PIN bw_d[320]
    DIRECTION OUTPUT ;
    USE SIGNAL ;
    PORT
      LAYER M5 ;
        RECT  42.192 0 42.216 0.084 ;
    END
  END bw_d[320]
  PIN bw_d[321]
    DIRECTION OUTPUT ;
    USE SIGNAL ;
    PORT
      LAYER M5 ;
        RECT  42.288 0 42.312 0.084 ;
    END
  END bw_d[321]
  PIN bw_d[322]
    DIRECTION OUTPUT ;
    USE SIGNAL ;
    PORT
      LAYER M5 ;
        RECT  42.384 0 42.408 0.084 ;
    END
  END bw_d[322]
  PIN bw_d[323]
    DIRECTION OUTPUT ;
    USE SIGNAL ;
    PORT
      LAYER M5 ;
        RECT  42.48 0 42.504 0.084 ;
    END
  END bw_d[323]
  PIN bw_d[324]
    DIRECTION OUTPUT ;
    USE SIGNAL ;
    PORT
      LAYER M5 ;
        RECT  42.576 0 42.6 0.084 ;
    END
  END bw_d[324]
  PIN bw_d[325]
    DIRECTION OUTPUT ;
    USE SIGNAL ;
    PORT
      LAYER M5 ;
        RECT  42.672 0 42.696 0.084 ;
    END
  END bw_d[325]
  PIN bw_d[326]
    DIRECTION OUTPUT ;
    USE SIGNAL ;
    PORT
      LAYER M5 ;
        RECT  42.768 0 42.792 0.084 ;
    END
  END bw_d[326]
  PIN bw_d[327]
    DIRECTION OUTPUT ;
    USE SIGNAL ;
    PORT
      LAYER M5 ;
        RECT  42.864 0 42.888 0.084 ;
    END
  END bw_d[327]
  PIN bw_d[328]
    DIRECTION OUTPUT ;
    USE SIGNAL ;
    PORT
      LAYER M5 ;
        RECT  42.96 0 42.984 0.084 ;
    END
  END bw_d[328]
  PIN bw_d[329]
    DIRECTION OUTPUT ;
    USE SIGNAL ;
    PORT
      LAYER M5 ;
        RECT  43.056 0 43.08 0.084 ;
    END
  END bw_d[329]
  PIN bw_d[32]
    DIRECTION OUTPUT ;
    USE SIGNAL ;
    PORT
      LAYER M5 ;
        RECT  19.92 0 19.944 0.084 ;
    END
  END bw_d[32]
  PIN bw_d[330]
    DIRECTION OUTPUT ;
    USE SIGNAL ;
    PORT
      LAYER M5 ;
        RECT  43.152 0 43.176 0.084 ;
    END
  END bw_d[330]
  PIN bw_d[331]
    DIRECTION OUTPUT ;
    USE SIGNAL ;
    PORT
      LAYER M5 ;
        RECT  43.248 0 43.272 0.084 ;
    END
  END bw_d[331]
  PIN bw_d[332]
    DIRECTION OUTPUT ;
    USE SIGNAL ;
    PORT
      LAYER M5 ;
        RECT  43.344 0 43.368 0.084 ;
    END
  END bw_d[332]
  PIN bw_d[333]
    DIRECTION OUTPUT ;
    USE SIGNAL ;
    PORT
      LAYER M5 ;
        RECT  43.44 0 43.464 0.084 ;
    END
  END bw_d[333]
  PIN bw_d[334]
    DIRECTION OUTPUT ;
    USE SIGNAL ;
    PORT
      LAYER M5 ;
        RECT  43.536 0 43.56 0.084 ;
    END
  END bw_d[334]
  PIN bw_d[335]
    DIRECTION OUTPUT ;
    USE SIGNAL ;
    PORT
      LAYER M5 ;
        RECT  43.632 0 43.656 0.084 ;
    END
  END bw_d[335]
  PIN bw_d[336]
    DIRECTION OUTPUT ;
    USE SIGNAL ;
    PORT
      LAYER M5 ;
        RECT  43.728 0 43.752 0.084 ;
    END
  END bw_d[336]
  PIN bw_d[337]
    DIRECTION OUTPUT ;
    USE SIGNAL ;
    PORT
      LAYER M5 ;
        RECT  43.824 0 43.848 0.084 ;
    END
  END bw_d[337]
  PIN bw_d[338]
    DIRECTION OUTPUT ;
    USE SIGNAL ;
    PORT
      LAYER M5 ;
        RECT  43.92 0 43.944 0.084 ;
    END
  END bw_d[338]
  PIN bw_d[339]
    DIRECTION OUTPUT ;
    USE SIGNAL ;
    PORT
      LAYER M5 ;
        RECT  44.016 0 44.04 0.084 ;
    END
  END bw_d[339]
  PIN bw_d[33]
    DIRECTION OUTPUT ;
    USE SIGNAL ;
    PORT
      LAYER M5 ;
        RECT  20.016 0 20.04 0.084 ;
    END
  END bw_d[33]
  PIN bw_d[340]
    DIRECTION OUTPUT ;
    USE SIGNAL ;
    PORT
      LAYER M5 ;
        RECT  44.112 0 44.136 0.084 ;
    END
  END bw_d[340]
  PIN bw_d[341]
    DIRECTION OUTPUT ;
    USE SIGNAL ;
    PORT
      LAYER M5 ;
        RECT  44.208 0 44.232 0.084 ;
    END
  END bw_d[341]
  PIN bw_d[342]
    DIRECTION OUTPUT ;
    USE SIGNAL ;
    PORT
      LAYER M5 ;
        RECT  44.304 0 44.328 0.084 ;
    END
  END bw_d[342]
  PIN bw_d[343]
    DIRECTION OUTPUT ;
    USE SIGNAL ;
    PORT
      LAYER M5 ;
        RECT  44.4 0 44.424 0.084 ;
    END
  END bw_d[343]
  PIN bw_d[344]
    DIRECTION OUTPUT ;
    USE SIGNAL ;
    PORT
      LAYER M5 ;
        RECT  44.496 0 44.52 0.084 ;
    END
  END bw_d[344]
  PIN bw_d[345]
    DIRECTION OUTPUT ;
    USE SIGNAL ;
    PORT
      LAYER M5 ;
        RECT  44.592 0 44.616 0.084 ;
    END
  END bw_d[345]
  PIN bw_d[346]
    DIRECTION OUTPUT ;
    USE SIGNAL ;
    PORT
      LAYER M5 ;
        RECT  44.688 0 44.712 0.084 ;
    END
  END bw_d[346]
  PIN bw_d[347]
    DIRECTION OUTPUT ;
    USE SIGNAL ;
    PORT
      LAYER M5 ;
        RECT  44.784 0 44.808 0.084 ;
    END
  END bw_d[347]
  PIN bw_d[348]
    DIRECTION OUTPUT ;
    USE SIGNAL ;
    PORT
      LAYER M5 ;
        RECT  44.88 0 44.904 0.084 ;
    END
  END bw_d[348]
  PIN bw_d[349]
    DIRECTION OUTPUT ;
    USE SIGNAL ;
    PORT
      LAYER M5 ;
        RECT  44.976 0 45 0.084 ;
    END
  END bw_d[349]
  PIN bw_d[34]
    DIRECTION OUTPUT ;
    USE SIGNAL ;
    PORT
      LAYER M5 ;
        RECT  20.112 0 20.136 0.084 ;
    END
  END bw_d[34]
  PIN bw_d[350]
    DIRECTION OUTPUT ;
    USE SIGNAL ;
    PORT
      LAYER M5 ;
        RECT  45.072 0 45.096 0.084 ;
    END
  END bw_d[350]
  PIN bw_d[351]
    DIRECTION OUTPUT ;
    USE SIGNAL ;
    PORT
      LAYER M5 ;
        RECT  45.168 0 45.192 0.084 ;
    END
  END bw_d[351]
  PIN bw_d[352]
    DIRECTION OUTPUT ;
    USE SIGNAL ;
    PORT
      LAYER M5 ;
        RECT  54.48 0 54.504 0.084 ;
    END
  END bw_d[352]
  PIN bw_d[353]
    DIRECTION OUTPUT ;
    USE SIGNAL ;
    PORT
      LAYER M5 ;
        RECT  54.576 0 54.6 0.084 ;
    END
  END bw_d[353]
  PIN bw_d[354]
    DIRECTION OUTPUT ;
    USE SIGNAL ;
    PORT
      LAYER M5 ;
        RECT  54.672 0 54.696 0.084 ;
    END
  END bw_d[354]
  PIN bw_d[355]
    DIRECTION OUTPUT ;
    USE SIGNAL ;
    PORT
      LAYER M5 ;
        RECT  54.768 0 54.792 0.084 ;
    END
  END bw_d[355]
  PIN bw_d[356]
    DIRECTION OUTPUT ;
    USE SIGNAL ;
    PORT
      LAYER M5 ;
        RECT  54.864 0 54.888 0.084 ;
    END
  END bw_d[356]
  PIN bw_d[357]
    DIRECTION OUTPUT ;
    USE SIGNAL ;
    PORT
      LAYER M5 ;
        RECT  54.96 0 54.984 0.084 ;
    END
  END bw_d[357]
  PIN bw_d[358]
    DIRECTION OUTPUT ;
    USE SIGNAL ;
    PORT
      LAYER M5 ;
        RECT  55.056 0 55.08 0.084 ;
    END
  END bw_d[358]
  PIN bw_d[359]
    DIRECTION OUTPUT ;
    USE SIGNAL ;
    PORT
      LAYER M5 ;
        RECT  55.152 0 55.176 0.084 ;
    END
  END bw_d[359]
  PIN bw_d[35]
    DIRECTION OUTPUT ;
    USE SIGNAL ;
    PORT
      LAYER M5 ;
        RECT  20.208 0 20.232 0.084 ;
    END
  END bw_d[35]
  PIN bw_d[360]
    DIRECTION OUTPUT ;
    USE SIGNAL ;
    PORT
      LAYER M5 ;
        RECT  55.248 0 55.272 0.084 ;
    END
  END bw_d[360]
  PIN bw_d[361]
    DIRECTION OUTPUT ;
    USE SIGNAL ;
    PORT
      LAYER M5 ;
        RECT  55.344 0 55.368 0.084 ;
    END
  END bw_d[361]
  PIN bw_d[362]
    DIRECTION OUTPUT ;
    USE SIGNAL ;
    PORT
      LAYER M5 ;
        RECT  55.44 0 55.464 0.084 ;
    END
  END bw_d[362]
  PIN bw_d[363]
    DIRECTION OUTPUT ;
    USE SIGNAL ;
    PORT
      LAYER M5 ;
        RECT  55.536 0 55.56 0.084 ;
    END
  END bw_d[363]
  PIN bw_d[364]
    DIRECTION OUTPUT ;
    USE SIGNAL ;
    PORT
      LAYER M5 ;
        RECT  55.632 0 55.656 0.084 ;
    END
  END bw_d[364]
  PIN bw_d[365]
    DIRECTION OUTPUT ;
    USE SIGNAL ;
    PORT
      LAYER M5 ;
        RECT  55.728 0 55.752 0.084 ;
    END
  END bw_d[365]
  PIN bw_d[366]
    DIRECTION OUTPUT ;
    USE SIGNAL ;
    PORT
      LAYER M5 ;
        RECT  55.824 0 55.848 0.084 ;
    END
  END bw_d[366]
  PIN bw_d[367]
    DIRECTION OUTPUT ;
    USE SIGNAL ;
    PORT
      LAYER M5 ;
        RECT  55.92 0 55.944 0.084 ;
    END
  END bw_d[367]
  PIN bw_d[368]
    DIRECTION OUTPUT ;
    USE SIGNAL ;
    PORT
      LAYER M5 ;
        RECT  56.016 0 56.04 0.084 ;
    END
  END bw_d[368]
  PIN bw_d[369]
    DIRECTION OUTPUT ;
    USE SIGNAL ;
    PORT
      LAYER M5 ;
        RECT  56.112 0 56.136 0.084 ;
    END
  END bw_d[369]
  PIN bw_d[36]
    DIRECTION OUTPUT ;
    USE SIGNAL ;
    PORT
      LAYER M5 ;
        RECT  20.304 0 20.328 0.084 ;
    END
  END bw_d[36]
  PIN bw_d[370]
    DIRECTION OUTPUT ;
    USE SIGNAL ;
    PORT
      LAYER M5 ;
        RECT  56.208 0 56.232 0.084 ;
    END
  END bw_d[370]
  PIN bw_d[371]
    DIRECTION OUTPUT ;
    USE SIGNAL ;
    PORT
      LAYER M5 ;
        RECT  56.304 0 56.328 0.084 ;
    END
  END bw_d[371]
  PIN bw_d[372]
    DIRECTION OUTPUT ;
    USE SIGNAL ;
    PORT
      LAYER M5 ;
        RECT  56.4 0 56.424 0.084 ;
    END
  END bw_d[372]
  PIN bw_d[373]
    DIRECTION OUTPUT ;
    USE SIGNAL ;
    PORT
      LAYER M5 ;
        RECT  56.496 0 56.52 0.084 ;
    END
  END bw_d[373]
  PIN bw_d[374]
    DIRECTION OUTPUT ;
    USE SIGNAL ;
    PORT
      LAYER M5 ;
        RECT  56.592 0 56.616 0.084 ;
    END
  END bw_d[374]
  PIN bw_d[375]
    DIRECTION OUTPUT ;
    USE SIGNAL ;
    PORT
      LAYER M5 ;
        RECT  56.688 0 56.712 0.084 ;
    END
  END bw_d[375]
  PIN bw_d[376]
    DIRECTION OUTPUT ;
    USE SIGNAL ;
    PORT
      LAYER M5 ;
        RECT  56.784 0 56.808 0.084 ;
    END
  END bw_d[376]
  PIN bw_d[377]
    DIRECTION OUTPUT ;
    USE SIGNAL ;
    PORT
      LAYER M5 ;
        RECT  56.88 0 56.904 0.084 ;
    END
  END bw_d[377]
  PIN bw_d[378]
    DIRECTION OUTPUT ;
    USE SIGNAL ;
    PORT
      LAYER M5 ;
        RECT  56.976 0 57 0.084 ;
    END
  END bw_d[378]
  PIN bw_d[379]
    DIRECTION OUTPUT ;
    USE SIGNAL ;
    PORT
      LAYER M5 ;
        RECT  57.072 0 57.096 0.084 ;
    END
  END bw_d[379]
  PIN bw_d[37]
    DIRECTION OUTPUT ;
    USE SIGNAL ;
    PORT
      LAYER M5 ;
        RECT  20.4 0 20.424 0.084 ;
    END
  END bw_d[37]
  PIN bw_d[380]
    DIRECTION OUTPUT ;
    USE SIGNAL ;
    PORT
      LAYER M5 ;
        RECT  57.168 0 57.192 0.084 ;
    END
  END bw_d[380]
  PIN bw_d[381]
    DIRECTION OUTPUT ;
    USE SIGNAL ;
    PORT
      LAYER M5 ;
        RECT  57.264 0 57.288 0.084 ;
    END
  END bw_d[381]
  PIN bw_d[382]
    DIRECTION OUTPUT ;
    USE SIGNAL ;
    PORT
      LAYER M5 ;
        RECT  57.36 0 57.384 0.084 ;
    END
  END bw_d[382]
  PIN bw_d[383]
    DIRECTION OUTPUT ;
    USE SIGNAL ;
    PORT
      LAYER M5 ;
        RECT  57.456 0 57.48 0.084 ;
    END
  END bw_d[383]
  PIN bw_d[384]
    DIRECTION OUTPUT ;
    USE SIGNAL ;
    PORT
      LAYER M5 ;
        RECT  3.792 0 3.816 0.084 ;
    END
  END bw_d[384]
  PIN bw_d[385]
    DIRECTION OUTPUT ;
    USE SIGNAL ;
    PORT
      LAYER M5 ;
        RECT  3.888 0 3.912 0.084 ;
    END
  END bw_d[385]
  PIN bw_d[386]
    DIRECTION OUTPUT ;
    USE SIGNAL ;
    PORT
      LAYER M5 ;
        RECT  3.984 0 4.008 0.084 ;
    END
  END bw_d[386]
  PIN bw_d[387]
    DIRECTION OUTPUT ;
    USE SIGNAL ;
    PORT
      LAYER M5 ;
        RECT  4.08 0 4.104 0.084 ;
    END
  END bw_d[387]
  PIN bw_d[388]
    DIRECTION OUTPUT ;
    USE SIGNAL ;
    PORT
      LAYER M5 ;
        RECT  4.176 0 4.2 0.084 ;
    END
  END bw_d[388]
  PIN bw_d[389]
    DIRECTION OUTPUT ;
    USE SIGNAL ;
    PORT
      LAYER M5 ;
        RECT  4.272 0 4.296 0.084 ;
    END
  END bw_d[389]
  PIN bw_d[38]
    DIRECTION OUTPUT ;
    USE SIGNAL ;
    PORT
      LAYER M5 ;
        RECT  20.496 0 20.52 0.084 ;
    END
  END bw_d[38]
  PIN bw_d[390]
    DIRECTION OUTPUT ;
    USE SIGNAL ;
    PORT
      LAYER M5 ;
        RECT  4.368 0 4.392 0.084 ;
    END
  END bw_d[390]
  PIN bw_d[391]
    DIRECTION OUTPUT ;
    USE SIGNAL ;
    PORT
      LAYER M5 ;
        RECT  4.464 0 4.488 0.084 ;
    END
  END bw_d[391]
  PIN bw_d[392]
    DIRECTION OUTPUT ;
    USE SIGNAL ;
    PORT
      LAYER M5 ;
        RECT  4.56 0 4.584 0.084 ;
    END
  END bw_d[392]
  PIN bw_d[393]
    DIRECTION OUTPUT ;
    USE SIGNAL ;
    PORT
      LAYER M5 ;
        RECT  4.656 0 4.68 0.084 ;
    END
  END bw_d[393]
  PIN bw_d[394]
    DIRECTION OUTPUT ;
    USE SIGNAL ;
    PORT
      LAYER M5 ;
        RECT  4.752 0 4.776 0.084 ;
    END
  END bw_d[394]
  PIN bw_d[395]
    DIRECTION OUTPUT ;
    USE SIGNAL ;
    PORT
      LAYER M5 ;
        RECT  4.848 0 4.872 0.084 ;
    END
  END bw_d[395]
  PIN bw_d[396]
    DIRECTION OUTPUT ;
    USE SIGNAL ;
    PORT
      LAYER M5 ;
        RECT  4.944 0 4.968 0.084 ;
    END
  END bw_d[396]
  PIN bw_d[397]
    DIRECTION OUTPUT ;
    USE SIGNAL ;
    PORT
      LAYER M5 ;
        RECT  5.04 0 5.064 0.084 ;
    END
  END bw_d[397]
  PIN bw_d[398]
    DIRECTION OUTPUT ;
    USE SIGNAL ;
    PORT
      LAYER M5 ;
        RECT  5.136 0 5.16 0.084 ;
    END
  END bw_d[398]
  PIN bw_d[399]
    DIRECTION OUTPUT ;
    USE SIGNAL ;
    PORT
      LAYER M5 ;
        RECT  5.232 0 5.256 0.084 ;
    END
  END bw_d[399]
  PIN bw_d[39]
    DIRECTION OUTPUT ;
    USE SIGNAL ;
    PORT
      LAYER M5 ;
        RECT  20.592 0 20.616 0.084 ;
    END
  END bw_d[39]
  PIN bw_d[3]
    DIRECTION OUTPUT ;
    USE SIGNAL ;
    PORT
      LAYER M5 ;
        RECT  23.28 0 23.304 0.084 ;
    END
  END bw_d[3]
  PIN bw_d[400]
    DIRECTION OUTPUT ;
    USE SIGNAL ;
    PORT
      LAYER M5 ;
        RECT  5.328 0 5.352 0.084 ;
    END
  END bw_d[400]
  PIN bw_d[401]
    DIRECTION OUTPUT ;
    USE SIGNAL ;
    PORT
      LAYER M5 ;
        RECT  5.424 0 5.448 0.084 ;
    END
  END bw_d[401]
  PIN bw_d[402]
    DIRECTION OUTPUT ;
    USE SIGNAL ;
    PORT
      LAYER M5 ;
        RECT  5.52 0 5.544 0.084 ;
    END
  END bw_d[402]
  PIN bw_d[403]
    DIRECTION OUTPUT ;
    USE SIGNAL ;
    PORT
      LAYER M5 ;
        RECT  5.616 0 5.64 0.084 ;
    END
  END bw_d[403]
  PIN bw_d[404]
    DIRECTION OUTPUT ;
    USE SIGNAL ;
    PORT
      LAYER M5 ;
        RECT  5.712 0 5.736 0.084 ;
    END
  END bw_d[404]
  PIN bw_d[405]
    DIRECTION OUTPUT ;
    USE SIGNAL ;
    PORT
      LAYER M5 ;
        RECT  5.808 0 5.832 0.084 ;
    END
  END bw_d[405]
  PIN bw_d[406]
    DIRECTION OUTPUT ;
    USE SIGNAL ;
    PORT
      LAYER M5 ;
        RECT  5.904 0 5.928 0.084 ;
    END
  END bw_d[406]
  PIN bw_d[407]
    DIRECTION OUTPUT ;
    USE SIGNAL ;
    PORT
      LAYER M5 ;
        RECT  6 0 6.024 0.084 ;
    END
  END bw_d[407]
  PIN bw_d[408]
    DIRECTION OUTPUT ;
    USE SIGNAL ;
    PORT
      LAYER M5 ;
        RECT  6.096 0 6.12 0.084 ;
    END
  END bw_d[408]
  PIN bw_d[409]
    DIRECTION OUTPUT ;
    USE SIGNAL ;
    PORT
      LAYER M5 ;
        RECT  6.192 0 6.216 0.084 ;
    END
  END bw_d[409]
  PIN bw_d[40]
    DIRECTION OUTPUT ;
    USE SIGNAL ;
    PORT
      LAYER M5 ;
        RECT  20.688 0 20.712 0.084 ;
    END
  END bw_d[40]
  PIN bw_d[410]
    DIRECTION OUTPUT ;
    USE SIGNAL ;
    PORT
      LAYER M5 ;
        RECT  6.288 0 6.312 0.084 ;
    END
  END bw_d[410]
  PIN bw_d[411]
    DIRECTION OUTPUT ;
    USE SIGNAL ;
    PORT
      LAYER M5 ;
        RECT  6.384 0 6.408 0.084 ;
    END
  END bw_d[411]
  PIN bw_d[412]
    DIRECTION OUTPUT ;
    USE SIGNAL ;
    PORT
      LAYER M5 ;
        RECT  6.48 0 6.504 0.084 ;
    END
  END bw_d[412]
  PIN bw_d[413]
    DIRECTION OUTPUT ;
    USE SIGNAL ;
    PORT
      LAYER M5 ;
        RECT  6.576 0 6.6 0.084 ;
    END
  END bw_d[413]
  PIN bw_d[414]
    DIRECTION OUTPUT ;
    USE SIGNAL ;
    PORT
      LAYER M5 ;
        RECT  6.672 0 6.696 0.084 ;
    END
  END bw_d[414]
  PIN bw_d[415]
    DIRECTION OUTPUT ;
    USE SIGNAL ;
    PORT
      LAYER M5 ;
        RECT  6.768 0 6.792 0.084 ;
    END
  END bw_d[415]
  PIN bw_d[416]
    DIRECTION OUTPUT ;
    USE SIGNAL ;
    PORT
      LAYER M5 ;
        RECT  6.864 0 6.888 0.084 ;
    END
  END bw_d[416]
  PIN bw_d[417]
    DIRECTION OUTPUT ;
    USE SIGNAL ;
    PORT
      LAYER M5 ;
        RECT  6.96 0 6.984 0.084 ;
    END
  END bw_d[417]
  PIN bw_d[418]
    DIRECTION OUTPUT ;
    USE SIGNAL ;
    PORT
      LAYER M5 ;
        RECT  7.056 0 7.08 0.084 ;
    END
  END bw_d[418]
  PIN bw_d[419]
    DIRECTION OUTPUT ;
    USE SIGNAL ;
    PORT
      LAYER M5 ;
        RECT  7.152 0 7.176 0.084 ;
    END
  END bw_d[419]
  PIN bw_d[41]
    DIRECTION OUTPUT ;
    USE SIGNAL ;
    PORT
      LAYER M5 ;
        RECT  20.784 0 20.808 0.084 ;
    END
  END bw_d[41]
  PIN bw_d[420]
    DIRECTION OUTPUT ;
    USE SIGNAL ;
    PORT
      LAYER M5 ;
        RECT  7.248 0 7.272 0.084 ;
    END
  END bw_d[420]
  PIN bw_d[421]
    DIRECTION OUTPUT ;
    USE SIGNAL ;
    PORT
      LAYER M5 ;
        RECT  7.344 0 7.368 0.084 ;
    END
  END bw_d[421]
  PIN bw_d[422]
    DIRECTION OUTPUT ;
    USE SIGNAL ;
    PORT
      LAYER M5 ;
        RECT  7.44 0 7.464 0.084 ;
    END
  END bw_d[422]
  PIN bw_d[423]
    DIRECTION OUTPUT ;
    USE SIGNAL ;
    PORT
      LAYER M5 ;
        RECT  7.536 0 7.56 0.084 ;
    END
  END bw_d[423]
  PIN bw_d[424]
    DIRECTION OUTPUT ;
    USE SIGNAL ;
    PORT
      LAYER M5 ;
        RECT  7.632 0 7.656 0.084 ;
    END
  END bw_d[424]
  PIN bw_d[425]
    DIRECTION OUTPUT ;
    USE SIGNAL ;
    PORT
      LAYER M5 ;
        RECT  7.728 0 7.752 0.084 ;
    END
  END bw_d[425]
  PIN bw_d[426]
    DIRECTION OUTPUT ;
    USE SIGNAL ;
    PORT
      LAYER M5 ;
        RECT  7.824 0 7.848 0.084 ;
    END
  END bw_d[426]
  PIN bw_d[427]
    DIRECTION OUTPUT ;
    USE SIGNAL ;
    PORT
      LAYER M5 ;
        RECT  7.92 0 7.944 0.084 ;
    END
  END bw_d[427]
  PIN bw_d[428]
    DIRECTION OUTPUT ;
    USE SIGNAL ;
    PORT
      LAYER M5 ;
        RECT  8.016 0 8.04 0.084 ;
    END
  END bw_d[428]
  PIN bw_d[429]
    DIRECTION OUTPUT ;
    USE SIGNAL ;
    PORT
      LAYER M5 ;
        RECT  8.112 0 8.136 0.084 ;
    END
  END bw_d[429]
  PIN bw_d[42]
    DIRECTION OUTPUT ;
    USE SIGNAL ;
    PORT
      LAYER M5 ;
        RECT  20.88 0 20.904 0.084 ;
    END
  END bw_d[42]
  PIN bw_d[430]
    DIRECTION OUTPUT ;
    USE SIGNAL ;
    PORT
      LAYER M5 ;
        RECT  8.208 0 8.232 0.084 ;
    END
  END bw_d[430]
  PIN bw_d[431]
    DIRECTION OUTPUT ;
    USE SIGNAL ;
    PORT
      LAYER M5 ;
        RECT  8.304 0 8.328 0.084 ;
    END
  END bw_d[431]
  PIN bw_d[432]
    DIRECTION OUTPUT ;
    USE SIGNAL ;
    PORT
      LAYER M5 ;
        RECT  8.4 0 8.424 0.084 ;
    END
  END bw_d[432]
  PIN bw_d[433]
    DIRECTION OUTPUT ;
    USE SIGNAL ;
    PORT
      LAYER M5 ;
        RECT  8.496 0 8.52 0.084 ;
    END
  END bw_d[433]
  PIN bw_d[434]
    DIRECTION OUTPUT ;
    USE SIGNAL ;
    PORT
      LAYER M5 ;
        RECT  8.592 0 8.616 0.084 ;
    END
  END bw_d[434]
  PIN bw_d[435]
    DIRECTION OUTPUT ;
    USE SIGNAL ;
    PORT
      LAYER M5 ;
        RECT  8.688 0 8.712 0.084 ;
    END
  END bw_d[435]
  PIN bw_d[436]
    DIRECTION OUTPUT ;
    USE SIGNAL ;
    PORT
      LAYER M5 ;
        RECT  8.784 0 8.808 0.084 ;
    END
  END bw_d[436]
  PIN bw_d[437]
    DIRECTION OUTPUT ;
    USE SIGNAL ;
    PORT
      LAYER M5 ;
        RECT  8.88 0 8.904 0.084 ;
    END
  END bw_d[437]
  PIN bw_d[438]
    DIRECTION OUTPUT ;
    USE SIGNAL ;
    PORT
      LAYER M5 ;
        RECT  8.976 0 9 0.084 ;
    END
  END bw_d[438]
  PIN bw_d[439]
    DIRECTION OUTPUT ;
    USE SIGNAL ;
    PORT
      LAYER M5 ;
        RECT  9.072 0 9.096 0.084 ;
    END
  END bw_d[439]
  PIN bw_d[43]
    DIRECTION OUTPUT ;
    USE SIGNAL ;
    PORT
      LAYER M5 ;
        RECT  20.976 0 21 0.084 ;
    END
  END bw_d[43]
  PIN bw_d[440]
    DIRECTION OUTPUT ;
    USE SIGNAL ;
    PORT
      LAYER M5 ;
        RECT  9.168 0 9.192 0.084 ;
    END
  END bw_d[440]
  PIN bw_d[441]
    DIRECTION OUTPUT ;
    USE SIGNAL ;
    PORT
      LAYER M5 ;
        RECT  9.264 0 9.288 0.084 ;
    END
  END bw_d[441]
  PIN bw_d[442]
    DIRECTION OUTPUT ;
    USE SIGNAL ;
    PORT
      LAYER M5 ;
        RECT  9.36 0 9.384 0.084 ;
    END
  END bw_d[442]
  PIN bw_d[443]
    DIRECTION OUTPUT ;
    USE SIGNAL ;
    PORT
      LAYER M5 ;
        RECT  9.456 0 9.48 0.084 ;
    END
  END bw_d[443]
  PIN bw_d[444]
    DIRECTION OUTPUT ;
    USE SIGNAL ;
    PORT
      LAYER M5 ;
        RECT  9.552 0 9.576 0.084 ;
    END
  END bw_d[444]
  PIN bw_d[445]
    DIRECTION OUTPUT ;
    USE SIGNAL ;
    PORT
      LAYER M5 ;
        RECT  9.648 0 9.672 0.084 ;
    END
  END bw_d[445]
  PIN bw_d[446]
    DIRECTION OUTPUT ;
    USE SIGNAL ;
    PORT
      LAYER M5 ;
        RECT  9.744 0 9.768 0.084 ;
    END
  END bw_d[446]
  PIN bw_d[447]
    DIRECTION OUTPUT ;
    USE SIGNAL ;
    PORT
      LAYER M5 ;
        RECT  9.84 0 9.864 0.084 ;
    END
  END bw_d[447]
  PIN bw_d[448]
    DIRECTION OUTPUT ;
    USE SIGNAL ;
    PORT
      LAYER M5 ;
        RECT  16.08 0 16.104 0.084 ;
    END
  END bw_d[448]
  PIN bw_d[449]
    DIRECTION OUTPUT ;
    USE SIGNAL ;
    PORT
      LAYER M5 ;
        RECT  16.176 0 16.2 0.084 ;
    END
  END bw_d[449]
  PIN bw_d[44]
    DIRECTION OUTPUT ;
    USE SIGNAL ;
    PORT
      LAYER M5 ;
        RECT  21.072 0 21.096 0.084 ;
    END
  END bw_d[44]
  PIN bw_d[450]
    DIRECTION OUTPUT ;
    USE SIGNAL ;
    PORT
      LAYER M5 ;
        RECT  16.272 0 16.296 0.084 ;
    END
  END bw_d[450]
  PIN bw_d[451]
    DIRECTION OUTPUT ;
    USE SIGNAL ;
    PORT
      LAYER M5 ;
        RECT  16.368 0 16.392 0.084 ;
    END
  END bw_d[451]
  PIN bw_d[452]
    DIRECTION OUTPUT ;
    USE SIGNAL ;
    PORT
      LAYER M5 ;
        RECT  16.464 0 16.488 0.084 ;
    END
  END bw_d[452]
  PIN bw_d[453]
    DIRECTION OUTPUT ;
    USE SIGNAL ;
    PORT
      LAYER M5 ;
        RECT  16.56 0 16.584 0.084 ;
    END
  END bw_d[453]
  PIN bw_d[454]
    DIRECTION OUTPUT ;
    USE SIGNAL ;
    PORT
      LAYER M5 ;
        RECT  16.656 0 16.68 0.084 ;
    END
  END bw_d[454]
  PIN bw_d[455]
    DIRECTION OUTPUT ;
    USE SIGNAL ;
    PORT
      LAYER M5 ;
        RECT  16.752 0 16.776 0.084 ;
    END
  END bw_d[455]
  PIN bw_d[456]
    DIRECTION OUTPUT ;
    USE SIGNAL ;
    PORT
      LAYER M5 ;
        RECT  16.848 0 16.872 0.084 ;
    END
  END bw_d[456]
  PIN bw_d[457]
    DIRECTION OUTPUT ;
    USE SIGNAL ;
    PORT
      LAYER M5 ;
        RECT  16.944 0 16.968 0.084 ;
    END
  END bw_d[457]
  PIN bw_d[458]
    DIRECTION OUTPUT ;
    USE SIGNAL ;
    PORT
      LAYER M5 ;
        RECT  17.04 0 17.064 0.084 ;
    END
  END bw_d[458]
  PIN bw_d[459]
    DIRECTION OUTPUT ;
    USE SIGNAL ;
    PORT
      LAYER M5 ;
        RECT  17.136 0 17.16 0.084 ;
    END
  END bw_d[459]
  PIN bw_d[45]
    DIRECTION OUTPUT ;
    USE SIGNAL ;
    PORT
      LAYER M5 ;
        RECT  21.168 0 21.192 0.084 ;
    END
  END bw_d[45]
  PIN bw_d[460]
    DIRECTION OUTPUT ;
    USE SIGNAL ;
    PORT
      LAYER M5 ;
        RECT  17.232 0 17.256 0.084 ;
    END
  END bw_d[460]
  PIN bw_d[461]
    DIRECTION OUTPUT ;
    USE SIGNAL ;
    PORT
      LAYER M5 ;
        RECT  17.328 0 17.352 0.084 ;
    END
  END bw_d[461]
  PIN bw_d[462]
    DIRECTION OUTPUT ;
    USE SIGNAL ;
    PORT
      LAYER M5 ;
        RECT  17.424 0 17.448 0.084 ;
    END
  END bw_d[462]
  PIN bw_d[463]
    DIRECTION OUTPUT ;
    USE SIGNAL ;
    PORT
      LAYER M5 ;
        RECT  17.52 0 17.544 0.084 ;
    END
  END bw_d[463]
  PIN bw_d[464]
    DIRECTION OUTPUT ;
    USE SIGNAL ;
    PORT
      LAYER M5 ;
        RECT  17.616 0 17.64 0.084 ;
    END
  END bw_d[464]
  PIN bw_d[465]
    DIRECTION OUTPUT ;
    USE SIGNAL ;
    PORT
      LAYER M5 ;
        RECT  17.712 0 17.736 0.084 ;
    END
  END bw_d[465]
  PIN bw_d[466]
    DIRECTION OUTPUT ;
    USE SIGNAL ;
    PORT
      LAYER M5 ;
        RECT  17.808 0 17.832 0.084 ;
    END
  END bw_d[466]
  PIN bw_d[467]
    DIRECTION OUTPUT ;
    USE SIGNAL ;
    PORT
      LAYER M5 ;
        RECT  17.904 0 17.928 0.084 ;
    END
  END bw_d[467]
  PIN bw_d[468]
    DIRECTION OUTPUT ;
    USE SIGNAL ;
    PORT
      LAYER M5 ;
        RECT  18 0 18.024 0.084 ;
    END
  END bw_d[468]
  PIN bw_d[469]
    DIRECTION OUTPUT ;
    USE SIGNAL ;
    PORT
      LAYER M5 ;
        RECT  18.096 0 18.12 0.084 ;
    END
  END bw_d[469]
  PIN bw_d[46]
    DIRECTION OUTPUT ;
    USE SIGNAL ;
    PORT
      LAYER M5 ;
        RECT  21.264 0 21.288 0.084 ;
    END
  END bw_d[46]
  PIN bw_d[470]
    DIRECTION OUTPUT ;
    USE SIGNAL ;
    PORT
      LAYER M5 ;
        RECT  18.192 0 18.216 0.084 ;
    END
  END bw_d[470]
  PIN bw_d[471]
    DIRECTION OUTPUT ;
    USE SIGNAL ;
    PORT
      LAYER M5 ;
        RECT  18.288 0 18.312 0.084 ;
    END
  END bw_d[471]
  PIN bw_d[472]
    DIRECTION OUTPUT ;
    USE SIGNAL ;
    PORT
      LAYER M5 ;
        RECT  18.384 0 18.408 0.084 ;
    END
  END bw_d[472]
  PIN bw_d[473]
    DIRECTION OUTPUT ;
    USE SIGNAL ;
    PORT
      LAYER M5 ;
        RECT  18.48 0 18.504 0.084 ;
    END
  END bw_d[473]
  PIN bw_d[474]
    DIRECTION OUTPUT ;
    USE SIGNAL ;
    PORT
      LAYER M5 ;
        RECT  18.576 0 18.6 0.084 ;
    END
  END bw_d[474]
  PIN bw_d[475]
    DIRECTION OUTPUT ;
    USE SIGNAL ;
    PORT
      LAYER M5 ;
        RECT  18.672 0 18.696 0.084 ;
    END
  END bw_d[475]
  PIN bw_d[476]
    DIRECTION OUTPUT ;
    USE SIGNAL ;
    PORT
      LAYER M5 ;
        RECT  18.768 0 18.792 0.084 ;
    END
  END bw_d[476]
  PIN bw_d[477]
    DIRECTION OUTPUT ;
    USE SIGNAL ;
    PORT
      LAYER M5 ;
        RECT  18.864 0 18.888 0.084 ;
    END
  END bw_d[477]
  PIN bw_d[478]
    DIRECTION OUTPUT ;
    USE SIGNAL ;
    PORT
      LAYER M5 ;
        RECT  18.96 0 18.984 0.084 ;
    END
  END bw_d[478]
  PIN bw_d[479]
    DIRECTION OUTPUT ;
    USE SIGNAL ;
    PORT
      LAYER M5 ;
        RECT  19.056 0 19.08 0.084 ;
    END
  END bw_d[479]
  PIN bw_d[47]
    DIRECTION OUTPUT ;
    USE SIGNAL ;
    PORT
      LAYER M5 ;
        RECT  21.36 0 21.384 0.084 ;
    END
  END bw_d[47]
  PIN bw_d[480]
    DIRECTION OUTPUT ;
    USE SIGNAL ;
    PORT
      LAYER M5 ;
        RECT  9.936 0 9.96 0.084 ;
    END
  END bw_d[480]
  PIN bw_d[481]
    DIRECTION OUTPUT ;
    USE SIGNAL ;
    PORT
      LAYER M5 ;
        RECT  10.032 0 10.056 0.084 ;
    END
  END bw_d[481]
  PIN bw_d[482]
    DIRECTION OUTPUT ;
    USE SIGNAL ;
    PORT
      LAYER M5 ;
        RECT  10.128 0 10.152 0.084 ;
    END
  END bw_d[482]
  PIN bw_d[483]
    DIRECTION OUTPUT ;
    USE SIGNAL ;
    PORT
      LAYER M5 ;
        RECT  10.224 0 10.248 0.084 ;
    END
  END bw_d[483]
  PIN bw_d[484]
    DIRECTION OUTPUT ;
    USE SIGNAL ;
    PORT
      LAYER M5 ;
        RECT  10.32 0 10.344 0.084 ;
    END
  END bw_d[484]
  PIN bw_d[485]
    DIRECTION OUTPUT ;
    USE SIGNAL ;
    PORT
      LAYER M5 ;
        RECT  10.416 0 10.44 0.084 ;
    END
  END bw_d[485]
  PIN bw_d[486]
    DIRECTION OUTPUT ;
    USE SIGNAL ;
    PORT
      LAYER M5 ;
        RECT  10.512 0 10.536 0.084 ;
    END
  END bw_d[486]
  PIN bw_d[487]
    DIRECTION OUTPUT ;
    USE SIGNAL ;
    PORT
      LAYER M5 ;
        RECT  10.608 0 10.632 0.084 ;
    END
  END bw_d[487]
  PIN bw_d[488]
    DIRECTION OUTPUT ;
    USE SIGNAL ;
    PORT
      LAYER M5 ;
        RECT  10.704 0 10.728 0.084 ;
    END
  END bw_d[488]
  PIN bw_d[489]
    DIRECTION OUTPUT ;
    USE SIGNAL ;
    PORT
      LAYER M5 ;
        RECT  10.8 0 10.824 0.084 ;
    END
  END bw_d[489]
  PIN bw_d[48]
    DIRECTION OUTPUT ;
    USE SIGNAL ;
    PORT
      LAYER M5 ;
        RECT  21.456 0 21.48 0.084 ;
    END
  END bw_d[48]
  PIN bw_d[490]
    DIRECTION OUTPUT ;
    USE SIGNAL ;
    PORT
      LAYER M5 ;
        RECT  10.896 0 10.92 0.084 ;
    END
  END bw_d[490]
  PIN bw_d[491]
    DIRECTION OUTPUT ;
    USE SIGNAL ;
    PORT
      LAYER M5 ;
        RECT  10.992 0 11.016 0.084 ;
    END
  END bw_d[491]
  PIN bw_d[492]
    DIRECTION OUTPUT ;
    USE SIGNAL ;
    PORT
      LAYER M5 ;
        RECT  11.088 0 11.112 0.084 ;
    END
  END bw_d[492]
  PIN bw_d[493]
    DIRECTION OUTPUT ;
    USE SIGNAL ;
    PORT
      LAYER M5 ;
        RECT  11.184 0 11.208 0.084 ;
    END
  END bw_d[493]
  PIN bw_d[494]
    DIRECTION OUTPUT ;
    USE SIGNAL ;
    PORT
      LAYER M5 ;
        RECT  11.28 0 11.304 0.084 ;
    END
  END bw_d[494]
  PIN bw_d[495]
    DIRECTION OUTPUT ;
    USE SIGNAL ;
    PORT
      LAYER M5 ;
        RECT  11.376 0 11.4 0.084 ;
    END
  END bw_d[495]
  PIN bw_d[496]
    DIRECTION OUTPUT ;
    USE SIGNAL ;
    PORT
      LAYER M5 ;
        RECT  11.472 0 11.496 0.084 ;
    END
  END bw_d[496]
  PIN bw_d[497]
    DIRECTION OUTPUT ;
    USE SIGNAL ;
    PORT
      LAYER M5 ;
        RECT  11.568 0 11.592 0.084 ;
    END
  END bw_d[497]
  PIN bw_d[498]
    DIRECTION OUTPUT ;
    USE SIGNAL ;
    PORT
      LAYER M5 ;
        RECT  11.664 0 11.688 0.084 ;
    END
  END bw_d[498]
  PIN bw_d[499]
    DIRECTION OUTPUT ;
    USE SIGNAL ;
    PORT
      LAYER M5 ;
        RECT  11.76 0 11.784 0.084 ;
    END
  END bw_d[499]
  PIN bw_d[49]
    DIRECTION OUTPUT ;
    USE SIGNAL ;
    PORT
      LAYER M5 ;
        RECT  21.552 0 21.576 0.084 ;
    END
  END bw_d[49]
  PIN bw_d[4]
    DIRECTION OUTPUT ;
    USE SIGNAL ;
    PORT
      LAYER M5 ;
        RECT  23.376 0 23.4 0.084 ;
    END
  END bw_d[4]
  PIN bw_d[500]
    DIRECTION OUTPUT ;
    USE SIGNAL ;
    PORT
      LAYER M5 ;
        RECT  11.856 0 11.88 0.084 ;
    END
  END bw_d[500]
  PIN bw_d[501]
    DIRECTION OUTPUT ;
    USE SIGNAL ;
    PORT
      LAYER M5 ;
        RECT  11.952 0 11.976 0.084 ;
    END
  END bw_d[501]
  PIN bw_d[502]
    DIRECTION OUTPUT ;
    USE SIGNAL ;
    PORT
      LAYER M5 ;
        RECT  12.048 0 12.072 0.084 ;
    END
  END bw_d[502]
  PIN bw_d[503]
    DIRECTION OUTPUT ;
    USE SIGNAL ;
    PORT
      LAYER M5 ;
        RECT  12.144 0 12.168 0.084 ;
    END
  END bw_d[503]
  PIN bw_d[504]
    DIRECTION OUTPUT ;
    USE SIGNAL ;
    PORT
      LAYER M5 ;
        RECT  12.24 0 12.264 0.084 ;
    END
  END bw_d[504]
  PIN bw_d[505]
    DIRECTION OUTPUT ;
    USE SIGNAL ;
    PORT
      LAYER M5 ;
        RECT  12.336 0 12.36 0.084 ;
    END
  END bw_d[505]
  PIN bw_d[506]
    DIRECTION OUTPUT ;
    USE SIGNAL ;
    PORT
      LAYER M5 ;
        RECT  12.432 0 12.456 0.084 ;
    END
  END bw_d[506]
  PIN bw_d[507]
    DIRECTION OUTPUT ;
    USE SIGNAL ;
    PORT
      LAYER M5 ;
        RECT  12.528 0 12.552 0.084 ;
    END
  END bw_d[507]
  PIN bw_d[508]
    DIRECTION OUTPUT ;
    USE SIGNAL ;
    PORT
      LAYER M5 ;
        RECT  12.624 0 12.648 0.084 ;
    END
  END bw_d[508]
  PIN bw_d[509]
    DIRECTION OUTPUT ;
    USE SIGNAL ;
    PORT
      LAYER M5 ;
        RECT  12.72 0 12.744 0.084 ;
    END
  END bw_d[509]
  PIN bw_d[50]
    DIRECTION OUTPUT ;
    USE SIGNAL ;
    PORT
      LAYER M5 ;
        RECT  21.648 0 21.672 0.084 ;
    END
  END bw_d[50]
  PIN bw_d[510]
    DIRECTION OUTPUT ;
    USE SIGNAL ;
    PORT
      LAYER M5 ;
        RECT  12.816 0 12.84 0.084 ;
    END
  END bw_d[510]
  PIN bw_d[511]
    DIRECTION OUTPUT ;
    USE SIGNAL ;
    PORT
      LAYER M5 ;
        RECT  12.912 0 12.936 0.084 ;
    END
  END bw_d[511]
  PIN bw_d[512]
    DIRECTION OUTPUT ;
    USE SIGNAL ;
    PORT
      LAYER M5 ;
        RECT  13.008 0 13.032 0.084 ;
    END
  END bw_d[512]
  PIN bw_d[513]
    DIRECTION OUTPUT ;
    USE SIGNAL ;
    PORT
      LAYER M5 ;
        RECT  13.104 0 13.128 0.084 ;
    END
  END bw_d[513]
  PIN bw_d[514]
    DIRECTION OUTPUT ;
    USE SIGNAL ;
    PORT
      LAYER M5 ;
        RECT  13.2 0 13.224 0.084 ;
    END
  END bw_d[514]
  PIN bw_d[515]
    DIRECTION OUTPUT ;
    USE SIGNAL ;
    PORT
      LAYER M5 ;
        RECT  13.296 0 13.32 0.084 ;
    END
  END bw_d[515]
  PIN bw_d[516]
    DIRECTION OUTPUT ;
    USE SIGNAL ;
    PORT
      LAYER M5 ;
        RECT  13.392 0 13.416 0.084 ;
    END
  END bw_d[516]
  PIN bw_d[517]
    DIRECTION OUTPUT ;
    USE SIGNAL ;
    PORT
      LAYER M5 ;
        RECT  13.488 0 13.512 0.084 ;
    END
  END bw_d[517]
  PIN bw_d[518]
    DIRECTION OUTPUT ;
    USE SIGNAL ;
    PORT
      LAYER M5 ;
        RECT  13.584 0 13.608 0.084 ;
    END
  END bw_d[518]
  PIN bw_d[519]
    DIRECTION OUTPUT ;
    USE SIGNAL ;
    PORT
      LAYER M5 ;
        RECT  13.68 0 13.704 0.084 ;
    END
  END bw_d[519]
  PIN bw_d[51]
    DIRECTION OUTPUT ;
    USE SIGNAL ;
    PORT
      LAYER M5 ;
        RECT  21.744 0 21.768 0.084 ;
    END
  END bw_d[51]
  PIN bw_d[520]
    DIRECTION OUTPUT ;
    USE SIGNAL ;
    PORT
      LAYER M5 ;
        RECT  13.776 0 13.8 0.084 ;
    END
  END bw_d[520]
  PIN bw_d[521]
    DIRECTION OUTPUT ;
    USE SIGNAL ;
    PORT
      LAYER M5 ;
        RECT  13.872 0 13.896 0.084 ;
    END
  END bw_d[521]
  PIN bw_d[522]
    DIRECTION OUTPUT ;
    USE SIGNAL ;
    PORT
      LAYER M5 ;
        RECT  13.968 0 13.992 0.084 ;
    END
  END bw_d[522]
  PIN bw_d[523]
    DIRECTION OUTPUT ;
    USE SIGNAL ;
    PORT
      LAYER M5 ;
        RECT  14.064 0 14.088 0.084 ;
    END
  END bw_d[523]
  PIN bw_d[524]
    DIRECTION OUTPUT ;
    USE SIGNAL ;
    PORT
      LAYER M5 ;
        RECT  14.16 0 14.184 0.084 ;
    END
  END bw_d[524]
  PIN bw_d[525]
    DIRECTION OUTPUT ;
    USE SIGNAL ;
    PORT
      LAYER M5 ;
        RECT  14.256 0 14.28 0.084 ;
    END
  END bw_d[525]
  PIN bw_d[526]
    DIRECTION OUTPUT ;
    USE SIGNAL ;
    PORT
      LAYER M5 ;
        RECT  14.352 0 14.376 0.084 ;
    END
  END bw_d[526]
  PIN bw_d[527]
    DIRECTION OUTPUT ;
    USE SIGNAL ;
    PORT
      LAYER M5 ;
        RECT  14.448 0 14.472 0.084 ;
    END
  END bw_d[527]
  PIN bw_d[528]
    DIRECTION OUTPUT ;
    USE SIGNAL ;
    PORT
      LAYER M5 ;
        RECT  14.544 0 14.568 0.084 ;
    END
  END bw_d[528]
  PIN bw_d[529]
    DIRECTION OUTPUT ;
    USE SIGNAL ;
    PORT
      LAYER M5 ;
        RECT  14.64 0 14.664 0.084 ;
    END
  END bw_d[529]
  PIN bw_d[52]
    DIRECTION OUTPUT ;
    USE SIGNAL ;
    PORT
      LAYER M5 ;
        RECT  21.84 0 21.864 0.084 ;
    END
  END bw_d[52]
  PIN bw_d[530]
    DIRECTION OUTPUT ;
    USE SIGNAL ;
    PORT
      LAYER M5 ;
        RECT  14.736 0 14.76 0.084 ;
    END
  END bw_d[530]
  PIN bw_d[531]
    DIRECTION OUTPUT ;
    USE SIGNAL ;
    PORT
      LAYER M5 ;
        RECT  14.832 0 14.856 0.084 ;
    END
  END bw_d[531]
  PIN bw_d[532]
    DIRECTION OUTPUT ;
    USE SIGNAL ;
    PORT
      LAYER M5 ;
        RECT  14.928 0 14.952 0.084 ;
    END
  END bw_d[532]
  PIN bw_d[533]
    DIRECTION OUTPUT ;
    USE SIGNAL ;
    PORT
      LAYER M5 ;
        RECT  15.024 0 15.048 0.084 ;
    END
  END bw_d[533]
  PIN bw_d[534]
    DIRECTION OUTPUT ;
    USE SIGNAL ;
    PORT
      LAYER M5 ;
        RECT  15.12 0 15.144 0.084 ;
    END
  END bw_d[534]
  PIN bw_d[535]
    DIRECTION OUTPUT ;
    USE SIGNAL ;
    PORT
      LAYER M5 ;
        RECT  15.216 0 15.24 0.084 ;
    END
  END bw_d[535]
  PIN bw_d[536]
    DIRECTION OUTPUT ;
    USE SIGNAL ;
    PORT
      LAYER M5 ;
        RECT  15.312 0 15.336 0.084 ;
    END
  END bw_d[536]
  PIN bw_d[537]
    DIRECTION OUTPUT ;
    USE SIGNAL ;
    PORT
      LAYER M5 ;
        RECT  15.408 0 15.432 0.084 ;
    END
  END bw_d[537]
  PIN bw_d[538]
    DIRECTION OUTPUT ;
    USE SIGNAL ;
    PORT
      LAYER M5 ;
        RECT  15.504 0 15.528 0.084 ;
    END
  END bw_d[538]
  PIN bw_d[539]
    DIRECTION OUTPUT ;
    USE SIGNAL ;
    PORT
      LAYER M5 ;
        RECT  15.6 0 15.624 0.084 ;
    END
  END bw_d[539]
  PIN bw_d[53]
    DIRECTION OUTPUT ;
    USE SIGNAL ;
    PORT
      LAYER M5 ;
        RECT  21.936 0 21.96 0.084 ;
    END
  END bw_d[53]
  PIN bw_d[540]
    DIRECTION OUTPUT ;
    USE SIGNAL ;
    PORT
      LAYER M5 ;
        RECT  15.696 0 15.72 0.084 ;
    END
  END bw_d[540]
  PIN bw_d[541]
    DIRECTION OUTPUT ;
    USE SIGNAL ;
    PORT
      LAYER M5 ;
        RECT  15.792 0 15.816 0.084 ;
    END
  END bw_d[541]
  PIN bw_d[542]
    DIRECTION OUTPUT ;
    USE SIGNAL ;
    PORT
      LAYER M5 ;
        RECT  15.888 0 15.912 0.084 ;
    END
  END bw_d[542]
  PIN bw_d[543]
    DIRECTION OUTPUT ;
    USE SIGNAL ;
    PORT
      LAYER M5 ;
        RECT  15.984 0 16.008 0.084 ;
    END
  END bw_d[543]
  PIN bw_d[544]
    DIRECTION OUTPUT ;
    USE SIGNAL ;
    PORT
      LAYER M5 ;
        RECT  58.32 0 58.344 0.084 ;
    END
  END bw_d[544]
  PIN bw_d[545]
    DIRECTION OUTPUT ;
    USE SIGNAL ;
    PORT
      LAYER M5 ;
        RECT  58.416 0 58.44 0.084 ;
    END
  END bw_d[545]
  PIN bw_d[546]
    DIRECTION OUTPUT ;
    USE SIGNAL ;
    PORT
      LAYER M5 ;
        RECT  58.512 0 58.536 0.084 ;
    END
  END bw_d[546]
  PIN bw_d[547]
    DIRECTION OUTPUT ;
    USE SIGNAL ;
    PORT
      LAYER M5 ;
        RECT  58.608 0 58.632 0.084 ;
    END
  END bw_d[547]
  PIN bw_d[548]
    DIRECTION OUTPUT ;
    USE SIGNAL ;
    PORT
      LAYER M5 ;
        RECT  58.704 0 58.728 0.084 ;
    END
  END bw_d[548]
  PIN bw_d[549]
    DIRECTION OUTPUT ;
    USE SIGNAL ;
    PORT
      LAYER M5 ;
        RECT  58.8 0 58.824 0.084 ;
    END
  END bw_d[549]
  PIN bw_d[54]
    DIRECTION OUTPUT ;
    USE SIGNAL ;
    PORT
      LAYER M5 ;
        RECT  22.032 0 22.056 0.084 ;
    END
  END bw_d[54]
  PIN bw_d[550]
    DIRECTION OUTPUT ;
    USE SIGNAL ;
    PORT
      LAYER M5 ;
        RECT  58.896 0 58.92 0.084 ;
    END
  END bw_d[550]
  PIN bw_d[551]
    DIRECTION OUTPUT ;
    USE SIGNAL ;
    PORT
      LAYER M5 ;
        RECT  58.992 0 59.016 0.084 ;
    END
  END bw_d[551]
  PIN bw_d[552]
    DIRECTION OUTPUT ;
    USE SIGNAL ;
    PORT
      LAYER M5 ;
        RECT  59.088 0 59.112 0.084 ;
    END
  END bw_d[552]
  PIN bw_d[553]
    DIRECTION OUTPUT ;
    USE SIGNAL ;
    PORT
      LAYER M5 ;
        RECT  59.184 0 59.208 0.084 ;
    END
  END bw_d[553]
  PIN bw_d[554]
    DIRECTION OUTPUT ;
    USE SIGNAL ;
    PORT
      LAYER M5 ;
        RECT  59.28 0 59.304 0.084 ;
    END
  END bw_d[554]
  PIN bw_d[555]
    DIRECTION OUTPUT ;
    USE SIGNAL ;
    PORT
      LAYER M5 ;
        RECT  59.376 0 59.4 0.084 ;
    END
  END bw_d[555]
  PIN bw_d[556]
    DIRECTION OUTPUT ;
    USE SIGNAL ;
    PORT
      LAYER M5 ;
        RECT  59.472 0 59.496 0.084 ;
    END
  END bw_d[556]
  PIN bw_d[557]
    DIRECTION OUTPUT ;
    USE SIGNAL ;
    PORT
      LAYER M5 ;
        RECT  59.568 0 59.592 0.084 ;
    END
  END bw_d[557]
  PIN bw_d[558]
    DIRECTION OUTPUT ;
    USE SIGNAL ;
    PORT
      LAYER M5 ;
        RECT  59.664 0 59.688 0.084 ;
    END
  END bw_d[558]
  PIN bw_d[559]
    DIRECTION OUTPUT ;
    USE SIGNAL ;
    PORT
      LAYER M5 ;
        RECT  59.76 0 59.784 0.084 ;
    END
  END bw_d[559]
  PIN bw_d[55]
    DIRECTION OUTPUT ;
    USE SIGNAL ;
    PORT
      LAYER M5 ;
        RECT  22.128 0 22.152 0.084 ;
    END
  END bw_d[55]
  PIN bw_d[560]
    DIRECTION OUTPUT ;
    USE SIGNAL ;
    PORT
      LAYER M5 ;
        RECT  59.856 0 59.88 0.084 ;
    END
  END bw_d[560]
  PIN bw_d[561]
    DIRECTION OUTPUT ;
    USE SIGNAL ;
    PORT
      LAYER M5 ;
        RECT  59.952 0 59.976 0.084 ;
    END
  END bw_d[561]
  PIN bw_d[562]
    DIRECTION OUTPUT ;
    USE SIGNAL ;
    PORT
      LAYER M5 ;
        RECT  60.048 0 60.072 0.084 ;
    END
  END bw_d[562]
  PIN bw_d[56]
    DIRECTION OUTPUT ;
    USE SIGNAL ;
    PORT
      LAYER M5 ;
        RECT  22.224 0 22.248 0.084 ;
    END
  END bw_d[56]
  PIN bw_d[57]
    DIRECTION OUTPUT ;
    USE SIGNAL ;
    PORT
      LAYER M5 ;
        RECT  22.32 0 22.344 0.084 ;
    END
  END bw_d[57]
  PIN bw_d[58]
    DIRECTION OUTPUT ;
    USE SIGNAL ;
    PORT
      LAYER M5 ;
        RECT  22.416 0 22.44 0.084 ;
    END
  END bw_d[58]
  PIN bw_d[59]
    DIRECTION OUTPUT ;
    USE SIGNAL ;
    PORT
      LAYER M5 ;
        RECT  22.512 0 22.536 0.084 ;
    END
  END bw_d[59]
  PIN bw_d[5]
    DIRECTION OUTPUT ;
    USE SIGNAL ;
    PORT
      LAYER M5 ;
        RECT  23.472 0 23.496 0.084 ;
    END
  END bw_d[5]
  PIN bw_d[60]
    DIRECTION OUTPUT ;
    USE SIGNAL ;
    PORT
      LAYER M5 ;
        RECT  22.608 0 22.632 0.084 ;
    END
  END bw_d[60]
  PIN bw_d[61]
    DIRECTION OUTPUT ;
    USE SIGNAL ;
    PORT
      LAYER M5 ;
        RECT  22.704 0 22.728 0.084 ;
    END
  END bw_d[61]
  PIN bw_d[62]
    DIRECTION OUTPUT ;
    USE SIGNAL ;
    PORT
      LAYER M5 ;
        RECT  22.8 0 22.824 0.084 ;
    END
  END bw_d[62]
  PIN bw_d[63]
    DIRECTION OUTPUT ;
    USE SIGNAL ;
    PORT
      LAYER M5 ;
        RECT  22.896 0 22.92 0.084 ;
    END
  END bw_d[63]
  PIN bw_d[64]
    DIRECTION OUTPUT ;
    USE SIGNAL ;
    PORT
      LAYER M5 ;
        RECT  35.28 0 35.304 0.084 ;
    END
  END bw_d[64]
  PIN bw_d[65]
    DIRECTION OUTPUT ;
    USE SIGNAL ;
    PORT
      LAYER M5 ;
        RECT  35.376 0 35.4 0.084 ;
    END
  END bw_d[65]
  PIN bw_d[66]
    DIRECTION OUTPUT ;
    USE SIGNAL ;
    PORT
      LAYER M5 ;
        RECT  35.472 0 35.496 0.084 ;
    END
  END bw_d[66]
  PIN bw_d[67]
    DIRECTION OUTPUT ;
    USE SIGNAL ;
    PORT
      LAYER M5 ;
        RECT  35.568 0 35.592 0.084 ;
    END
  END bw_d[67]
  PIN bw_d[68]
    DIRECTION OUTPUT ;
    USE SIGNAL ;
    PORT
      LAYER M5 ;
        RECT  35.664 0 35.688 0.084 ;
    END
  END bw_d[68]
  PIN bw_d[69]
    DIRECTION OUTPUT ;
    USE SIGNAL ;
    PORT
      LAYER M5 ;
        RECT  35.76 0 35.784 0.084 ;
    END
  END bw_d[69]
  PIN bw_d[6]
    DIRECTION OUTPUT ;
    USE SIGNAL ;
    PORT
      LAYER M5 ;
        RECT  23.568 0 23.592 0.084 ;
    END
  END bw_d[6]
  PIN bw_d[70]
    DIRECTION OUTPUT ;
    USE SIGNAL ;
    PORT
      LAYER M5 ;
        RECT  35.856 0 35.88 0.084 ;
    END
  END bw_d[70]
  PIN bw_d[71]
    DIRECTION OUTPUT ;
    USE SIGNAL ;
    PORT
      LAYER M5 ;
        RECT  35.952 0 35.976 0.084 ;
    END
  END bw_d[71]
  PIN bw_d[72]
    DIRECTION OUTPUT ;
    USE SIGNAL ;
    PORT
      LAYER M5 ;
        RECT  36.048 0 36.072 0.084 ;
    END
  END bw_d[72]
  PIN bw_d[73]
    DIRECTION OUTPUT ;
    USE SIGNAL ;
    PORT
      LAYER M5 ;
        RECT  36.144 0 36.168 0.084 ;
    END
  END bw_d[73]
  PIN bw_d[74]
    DIRECTION OUTPUT ;
    USE SIGNAL ;
    PORT
      LAYER M5 ;
        RECT  36.24 0 36.264 0.084 ;
    END
  END bw_d[74]
  PIN bw_d[75]
    DIRECTION OUTPUT ;
    USE SIGNAL ;
    PORT
      LAYER M5 ;
        RECT  36.336 0 36.36 0.084 ;
    END
  END bw_d[75]
  PIN bw_d[76]
    DIRECTION OUTPUT ;
    USE SIGNAL ;
    PORT
      LAYER M5 ;
        RECT  36.432 0 36.456 0.084 ;
    END
  END bw_d[76]
  PIN bw_d[77]
    DIRECTION OUTPUT ;
    USE SIGNAL ;
    PORT
      LAYER M5 ;
        RECT  36.528 0 36.552 0.084 ;
    END
  END bw_d[77]
  PIN bw_d[78]
    DIRECTION OUTPUT ;
    USE SIGNAL ;
    PORT
      LAYER M5 ;
        RECT  36.624 0 36.648 0.084 ;
    END
  END bw_d[78]
  PIN bw_d[79]
    DIRECTION OUTPUT ;
    USE SIGNAL ;
    PORT
      LAYER M5 ;
        RECT  36.72 0 36.744 0.084 ;
    END
  END bw_d[79]
  PIN bw_d[7]
    DIRECTION OUTPUT ;
    USE SIGNAL ;
    PORT
      LAYER M5 ;
        RECT  23.664 0 23.688 0.084 ;
    END
  END bw_d[7]
  PIN bw_d[80]
    DIRECTION OUTPUT ;
    USE SIGNAL ;
    PORT
      LAYER M5 ;
        RECT  36.816 0 36.84 0.084 ;
    END
  END bw_d[80]
  PIN bw_d[81]
    DIRECTION OUTPUT ;
    USE SIGNAL ;
    PORT
      LAYER M5 ;
        RECT  36.912 0 36.936 0.084 ;
    END
  END bw_d[81]
  PIN bw_d[82]
    DIRECTION OUTPUT ;
    USE SIGNAL ;
    PORT
      LAYER M5 ;
        RECT  37.008 0 37.032 0.084 ;
    END
  END bw_d[82]
  PIN bw_d[83]
    DIRECTION OUTPUT ;
    USE SIGNAL ;
    PORT
      LAYER M5 ;
        RECT  37.104 0 37.128 0.084 ;
    END
  END bw_d[83]
  PIN bw_d[84]
    DIRECTION OUTPUT ;
    USE SIGNAL ;
    PORT
      LAYER M5 ;
        RECT  37.2 0 37.224 0.084 ;
    END
  END bw_d[84]
  PIN bw_d[85]
    DIRECTION OUTPUT ;
    USE SIGNAL ;
    PORT
      LAYER M5 ;
        RECT  37.296 0 37.32 0.084 ;
    END
  END bw_d[85]
  PIN bw_d[86]
    DIRECTION OUTPUT ;
    USE SIGNAL ;
    PORT
      LAYER M5 ;
        RECT  37.392 0 37.416 0.084 ;
    END
  END bw_d[86]
  PIN bw_d[87]
    DIRECTION OUTPUT ;
    USE SIGNAL ;
    PORT
      LAYER M5 ;
        RECT  37.488 0 37.512 0.084 ;
    END
  END bw_d[87]
  PIN bw_d[88]
    DIRECTION OUTPUT ;
    USE SIGNAL ;
    PORT
      LAYER M5 ;
        RECT  37.584 0 37.608 0.084 ;
    END
  END bw_d[88]
  PIN bw_d[89]
    DIRECTION OUTPUT ;
    USE SIGNAL ;
    PORT
      LAYER M5 ;
        RECT  37.68 0 37.704 0.084 ;
    END
  END bw_d[89]
  PIN bw_d[8]
    DIRECTION OUTPUT ;
    USE SIGNAL ;
    PORT
      LAYER M5 ;
        RECT  23.76 0 23.784 0.084 ;
    END
  END bw_d[8]
  PIN bw_d[90]
    DIRECTION OUTPUT ;
    USE SIGNAL ;
    PORT
      LAYER M5 ;
        RECT  37.776 0 37.8 0.084 ;
    END
  END bw_d[90]
  PIN bw_d[91]
    DIRECTION OUTPUT ;
    USE SIGNAL ;
    PORT
      LAYER M5 ;
        RECT  37.872 0 37.896 0.084 ;
    END
  END bw_d[91]
  PIN bw_d[92]
    DIRECTION OUTPUT ;
    USE SIGNAL ;
    PORT
      LAYER M5 ;
        RECT  37.968 0 37.992 0.084 ;
    END
  END bw_d[92]
  PIN bw_d[93]
    DIRECTION OUTPUT ;
    USE SIGNAL ;
    PORT
      LAYER M5 ;
        RECT  38.064 0 38.088 0.084 ;
    END
  END bw_d[93]
  PIN bw_d[94]
    DIRECTION OUTPUT ;
    USE SIGNAL ;
    PORT
      LAYER M5 ;
        RECT  38.16 0 38.184 0.084 ;
    END
  END bw_d[94]
  PIN bw_d[95]
    DIRECTION OUTPUT ;
    USE SIGNAL ;
    PORT
      LAYER M5 ;
        RECT  38.256 0 38.28 0.084 ;
    END
  END bw_d[95]
  PIN bw_d[96]
    DIRECTION OUTPUT ;
    USE SIGNAL ;
    PORT
      LAYER M5 ;
        RECT  26.064 0 26.088 0.084 ;
    END
  END bw_d[96]
  PIN bw_d[97]
    DIRECTION OUTPUT ;
    USE SIGNAL ;
    PORT
      LAYER M5 ;
        RECT  26.16 0 26.184 0.084 ;
    END
  END bw_d[97]
  PIN bw_d[98]
    DIRECTION OUTPUT ;
    USE SIGNAL ;
    PORT
      LAYER M5 ;
        RECT  26.256 0 26.28 0.084 ;
    END
  END bw_d[98]
  PIN bw_d[99]
    DIRECTION OUTPUT ;
    USE SIGNAL ;
    PORT
      LAYER M5 ;
        RECT  26.352 0 26.376 0.084 ;
    END
  END bw_d[99]
  PIN bw_d[9]
    DIRECTION OUTPUT ;
    USE SIGNAL ;
    PORT
      LAYER M5 ;
        RECT  23.856 0 23.88 0.084 ;
    END
  END bw_d[9]
  PIN bw_v
    DIRECTION OUTPUT ;
    USE SIGNAL ;
    PORT
      LAYER M5 ;
        RECT  60.144 0 60.168 0.084 ;
    END
  END bw_v
  PIN ck
    DIRECTION INPUT ;
    USE SIGNAL ;
    PORT
      LAYER M4 ;
        RECT  0 10.32 0.084 10.344 ;
    END
  END ck
  PIN i_d[0]
    DIRECTION INPUT ;
    USE SIGNAL ;
    PORT
      LAYER M5 ;
        RECT  39.984 34.476 40.008 34.56 ;
    END
  END i_d[0]
  PIN i_d[100]
    DIRECTION INPUT ;
    USE SIGNAL ;
    PORT
      LAYER M5 ;
        RECT  37.296 34.476 37.32 34.56 ;
    END
  END i_d[100]
  PIN i_d[101]
    DIRECTION INPUT ;
    USE SIGNAL ;
    PORT
      LAYER M5 ;
        RECT  37.392 34.476 37.416 34.56 ;
    END
  END i_d[101]
  PIN i_d[102]
    DIRECTION INPUT ;
    USE SIGNAL ;
    PORT
      LAYER M5 ;
        RECT  37.488 34.476 37.512 34.56 ;
    END
  END i_d[102]
  PIN i_d[103]
    DIRECTION INPUT ;
    USE SIGNAL ;
    PORT
      LAYER M5 ;
        RECT  37.584 34.476 37.608 34.56 ;
    END
  END i_d[103]
  PIN i_d[104]
    DIRECTION INPUT ;
    USE SIGNAL ;
    PORT
      LAYER M5 ;
        RECT  37.68 34.476 37.704 34.56 ;
    END
  END i_d[104]
  PIN i_d[105]
    DIRECTION INPUT ;
    USE SIGNAL ;
    PORT
      LAYER M5 ;
        RECT  37.776 34.476 37.8 34.56 ;
    END
  END i_d[105]
  PIN i_d[106]
    DIRECTION INPUT ;
    USE SIGNAL ;
    PORT
      LAYER M5 ;
        RECT  37.872 34.476 37.896 34.56 ;
    END
  END i_d[106]
  PIN i_d[107]
    DIRECTION INPUT ;
    USE SIGNAL ;
    PORT
      LAYER M5 ;
        RECT  37.968 34.476 37.992 34.56 ;
    END
  END i_d[107]
  PIN i_d[108]
    DIRECTION INPUT ;
    USE SIGNAL ;
    PORT
      LAYER M5 ;
        RECT  38.064 34.476 38.088 34.56 ;
    END
  END i_d[108]
  PIN i_d[109]
    DIRECTION INPUT ;
    USE SIGNAL ;
    PORT
      LAYER M5 ;
        RECT  38.16 34.476 38.184 34.56 ;
    END
  END i_d[109]
  PIN i_d[10]
    DIRECTION INPUT ;
    USE SIGNAL ;
    PORT
      LAYER M5 ;
        RECT  40.944 34.476 40.968 34.56 ;
    END
  END i_d[10]
  PIN i_d[110]
    DIRECTION INPUT ;
    USE SIGNAL ;
    PORT
      LAYER M5 ;
        RECT  38.256 34.476 38.28 34.56 ;
    END
  END i_d[110]
  PIN i_d[111]
    DIRECTION INPUT ;
    USE SIGNAL ;
    PORT
      LAYER M5 ;
        RECT  38.352 34.476 38.376 34.56 ;
    END
  END i_d[111]
  PIN i_d[112]
    DIRECTION INPUT ;
    USE SIGNAL ;
    PORT
      LAYER M5 ;
        RECT  38.448 34.476 38.472 34.56 ;
    END
  END i_d[112]
  PIN i_d[113]
    DIRECTION INPUT ;
    USE SIGNAL ;
    PORT
      LAYER M5 ;
        RECT  38.544 34.476 38.568 34.56 ;
    END
  END i_d[113]
  PIN i_d[114]
    DIRECTION INPUT ;
    USE SIGNAL ;
    PORT
      LAYER M5 ;
        RECT  38.64 34.476 38.664 34.56 ;
    END
  END i_d[114]
  PIN i_d[115]
    DIRECTION INPUT ;
    USE SIGNAL ;
    PORT
      LAYER M5 ;
        RECT  38.736 34.476 38.76 34.56 ;
    END
  END i_d[115]
  PIN i_d[116]
    DIRECTION INPUT ;
    USE SIGNAL ;
    PORT
      LAYER M5 ;
        RECT  38.832 34.476 38.856 34.56 ;
    END
  END i_d[116]
  PIN i_d[117]
    DIRECTION INPUT ;
    USE SIGNAL ;
    PORT
      LAYER M5 ;
        RECT  38.928 34.476 38.952 34.56 ;
    END
  END i_d[117]
  PIN i_d[118]
    DIRECTION INPUT ;
    USE SIGNAL ;
    PORT
      LAYER M5 ;
        RECT  39.024 34.476 39.048 34.56 ;
    END
  END i_d[118]
  PIN i_d[119]
    DIRECTION INPUT ;
    USE SIGNAL ;
    PORT
      LAYER M5 ;
        RECT  39.12 34.476 39.144 34.56 ;
    END
  END i_d[119]
  PIN i_d[11]
    DIRECTION INPUT ;
    USE SIGNAL ;
    PORT
      LAYER M5 ;
        RECT  41.04 34.476 41.064 34.56 ;
    END
  END i_d[11]
  PIN i_d[120]
    DIRECTION INPUT ;
    USE SIGNAL ;
    PORT
      LAYER M5 ;
        RECT  39.216 34.476 39.24 34.56 ;
    END
  END i_d[120]
  PIN i_d[121]
    DIRECTION INPUT ;
    USE SIGNAL ;
    PORT
      LAYER M5 ;
        RECT  39.312 34.476 39.336 34.56 ;
    END
  END i_d[121]
  PIN i_d[122]
    DIRECTION INPUT ;
    USE SIGNAL ;
    PORT
      LAYER M5 ;
        RECT  39.408 34.476 39.432 34.56 ;
    END
  END i_d[122]
  PIN i_d[123]
    DIRECTION INPUT ;
    USE SIGNAL ;
    PORT
      LAYER M5 ;
        RECT  39.504 34.476 39.528 34.56 ;
    END
  END i_d[123]
  PIN i_d[124]
    DIRECTION INPUT ;
    USE SIGNAL ;
    PORT
      LAYER M5 ;
        RECT  39.6 34.476 39.624 34.56 ;
    END
  END i_d[124]
  PIN i_d[125]
    DIRECTION INPUT ;
    USE SIGNAL ;
    PORT
      LAYER M5 ;
        RECT  39.696 34.476 39.72 34.56 ;
    END
  END i_d[125]
  PIN i_d[126]
    DIRECTION INPUT ;
    USE SIGNAL ;
    PORT
      LAYER M5 ;
        RECT  39.792 34.476 39.816 34.56 ;
    END
  END i_d[126]
  PIN i_d[127]
    DIRECTION INPUT ;
    USE SIGNAL ;
    PORT
      LAYER M5 ;
        RECT  39.888 34.476 39.912 34.56 ;
    END
  END i_d[127]
  PIN i_d[128]
    DIRECTION INPUT ;
    USE SIGNAL ;
    PORT
      LAYER M5 ;
        RECT  30.768 34.476 30.792 34.56 ;
    END
  END i_d[128]
  PIN i_d[129]
    DIRECTION INPUT ;
    USE SIGNAL ;
    PORT
      LAYER M5 ;
        RECT  30.864 34.476 30.888 34.56 ;
    END
  END i_d[129]
  PIN i_d[12]
    DIRECTION INPUT ;
    USE SIGNAL ;
    PORT
      LAYER M5 ;
        RECT  41.136 34.476 41.16 34.56 ;
    END
  END i_d[12]
  PIN i_d[130]
    DIRECTION INPUT ;
    USE SIGNAL ;
    PORT
      LAYER M5 ;
        RECT  30.96 34.476 30.984 34.56 ;
    END
  END i_d[130]
  PIN i_d[131]
    DIRECTION INPUT ;
    USE SIGNAL ;
    PORT
      LAYER M5 ;
        RECT  31.056 34.476 31.08 34.56 ;
    END
  END i_d[131]
  PIN i_d[132]
    DIRECTION INPUT ;
    USE SIGNAL ;
    PORT
      LAYER M5 ;
        RECT  31.152 34.476 31.176 34.56 ;
    END
  END i_d[132]
  PIN i_d[133]
    DIRECTION INPUT ;
    USE SIGNAL ;
    PORT
      LAYER M5 ;
        RECT  31.248 34.476 31.272 34.56 ;
    END
  END i_d[133]
  PIN i_d[134]
    DIRECTION INPUT ;
    USE SIGNAL ;
    PORT
      LAYER M5 ;
        RECT  31.344 34.476 31.368 34.56 ;
    END
  END i_d[134]
  PIN i_d[135]
    DIRECTION INPUT ;
    USE SIGNAL ;
    PORT
      LAYER M5 ;
        RECT  31.44 34.476 31.464 34.56 ;
    END
  END i_d[135]
  PIN i_d[136]
    DIRECTION INPUT ;
    USE SIGNAL ;
    PORT
      LAYER M5 ;
        RECT  31.536 34.476 31.56 34.56 ;
    END
  END i_d[136]
  PIN i_d[137]
    DIRECTION INPUT ;
    USE SIGNAL ;
    PORT
      LAYER M5 ;
        RECT  31.632 34.476 31.656 34.56 ;
    END
  END i_d[137]
  PIN i_d[138]
    DIRECTION INPUT ;
    USE SIGNAL ;
    PORT
      LAYER M5 ;
        RECT  31.728 34.476 31.752 34.56 ;
    END
  END i_d[138]
  PIN i_d[139]
    DIRECTION INPUT ;
    USE SIGNAL ;
    PORT
      LAYER M5 ;
        RECT  31.824 34.476 31.848 34.56 ;
    END
  END i_d[139]
  PIN i_d[13]
    DIRECTION INPUT ;
    USE SIGNAL ;
    PORT
      LAYER M5 ;
        RECT  41.232 34.476 41.256 34.56 ;
    END
  END i_d[13]
  PIN i_d[140]
    DIRECTION INPUT ;
    USE SIGNAL ;
    PORT
      LAYER M5 ;
        RECT  31.92 34.476 31.944 34.56 ;
    END
  END i_d[140]
  PIN i_d[141]
    DIRECTION INPUT ;
    USE SIGNAL ;
    PORT
      LAYER M5 ;
        RECT  32.016 34.476 32.04 34.56 ;
    END
  END i_d[141]
  PIN i_d[142]
    DIRECTION INPUT ;
    USE SIGNAL ;
    PORT
      LAYER M5 ;
        RECT  32.112 34.476 32.136 34.56 ;
    END
  END i_d[142]
  PIN i_d[143]
    DIRECTION INPUT ;
    USE SIGNAL ;
    PORT
      LAYER M5 ;
        RECT  32.208 34.476 32.232 34.56 ;
    END
  END i_d[143]
  PIN i_d[144]
    DIRECTION INPUT ;
    USE SIGNAL ;
    PORT
      LAYER M5 ;
        RECT  32.304 34.476 32.328 34.56 ;
    END
  END i_d[144]
  PIN i_d[145]
    DIRECTION INPUT ;
    USE SIGNAL ;
    PORT
      LAYER M5 ;
        RECT  32.4 34.476 32.424 34.56 ;
    END
  END i_d[145]
  PIN i_d[146]
    DIRECTION INPUT ;
    USE SIGNAL ;
    PORT
      LAYER M5 ;
        RECT  32.496 34.476 32.52 34.56 ;
    END
  END i_d[146]
  PIN i_d[147]
    DIRECTION INPUT ;
    USE SIGNAL ;
    PORT
      LAYER M5 ;
        RECT  32.592 34.476 32.616 34.56 ;
    END
  END i_d[147]
  PIN i_d[148]
    DIRECTION INPUT ;
    USE SIGNAL ;
    PORT
      LAYER M5 ;
        RECT  32.688 34.476 32.712 34.56 ;
    END
  END i_d[148]
  PIN i_d[149]
    DIRECTION INPUT ;
    USE SIGNAL ;
    PORT
      LAYER M5 ;
        RECT  32.784 34.476 32.808 34.56 ;
    END
  END i_d[149]
  PIN i_d[14]
    DIRECTION INPUT ;
    USE SIGNAL ;
    PORT
      LAYER M5 ;
        RECT  41.328 34.476 41.352 34.56 ;
    END
  END i_d[14]
  PIN i_d[150]
    DIRECTION INPUT ;
    USE SIGNAL ;
    PORT
      LAYER M5 ;
        RECT  32.88 34.476 32.904 34.56 ;
    END
  END i_d[150]
  PIN i_d[151]
    DIRECTION INPUT ;
    USE SIGNAL ;
    PORT
      LAYER M5 ;
        RECT  32.976 34.476 33 34.56 ;
    END
  END i_d[151]
  PIN i_d[152]
    DIRECTION INPUT ;
    USE SIGNAL ;
    PORT
      LAYER M5 ;
        RECT  33.072 34.476 33.096 34.56 ;
    END
  END i_d[152]
  PIN i_d[153]
    DIRECTION INPUT ;
    USE SIGNAL ;
    PORT
      LAYER M5 ;
        RECT  33.168 34.476 33.192 34.56 ;
    END
  END i_d[153]
  PIN i_d[154]
    DIRECTION INPUT ;
    USE SIGNAL ;
    PORT
      LAYER M5 ;
        RECT  33.264 34.476 33.288 34.56 ;
    END
  END i_d[154]
  PIN i_d[155]
    DIRECTION INPUT ;
    USE SIGNAL ;
    PORT
      LAYER M5 ;
        RECT  33.36 34.476 33.384 34.56 ;
    END
  END i_d[155]
  PIN i_d[156]
    DIRECTION INPUT ;
    USE SIGNAL ;
    PORT
      LAYER M5 ;
        RECT  33.456 34.476 33.48 34.56 ;
    END
  END i_d[156]
  PIN i_d[157]
    DIRECTION INPUT ;
    USE SIGNAL ;
    PORT
      LAYER M5 ;
        RECT  33.552 34.476 33.576 34.56 ;
    END
  END i_d[157]
  PIN i_d[158]
    DIRECTION INPUT ;
    USE SIGNAL ;
    PORT
      LAYER M5 ;
        RECT  33.648 34.476 33.672 34.56 ;
    END
  END i_d[158]
  PIN i_d[159]
    DIRECTION INPUT ;
    USE SIGNAL ;
    PORT
      LAYER M5 ;
        RECT  33.744 34.476 33.768 34.56 ;
    END
  END i_d[159]
  PIN i_d[15]
    DIRECTION INPUT ;
    USE SIGNAL ;
    PORT
      LAYER M5 ;
        RECT  41.424 34.476 41.448 34.56 ;
    END
  END i_d[15]
  PIN i_d[160]
    DIRECTION INPUT ;
    USE SIGNAL ;
    PORT
      LAYER M5 ;
        RECT  43.056 34.476 43.08 34.56 ;
    END
  END i_d[160]
  PIN i_d[161]
    DIRECTION INPUT ;
    USE SIGNAL ;
    PORT
      LAYER M5 ;
        RECT  43.152 34.476 43.176 34.56 ;
    END
  END i_d[161]
  PIN i_d[162]
    DIRECTION INPUT ;
    USE SIGNAL ;
    PORT
      LAYER M5 ;
        RECT  43.248 34.476 43.272 34.56 ;
    END
  END i_d[162]
  PIN i_d[163]
    DIRECTION INPUT ;
    USE SIGNAL ;
    PORT
      LAYER M5 ;
        RECT  43.344 34.476 43.368 34.56 ;
    END
  END i_d[163]
  PIN i_d[164]
    DIRECTION INPUT ;
    USE SIGNAL ;
    PORT
      LAYER M5 ;
        RECT  43.44 34.476 43.464 34.56 ;
    END
  END i_d[164]
  PIN i_d[165]
    DIRECTION INPUT ;
    USE SIGNAL ;
    PORT
      LAYER M5 ;
        RECT  43.536 34.476 43.56 34.56 ;
    END
  END i_d[165]
  PIN i_d[166]
    DIRECTION INPUT ;
    USE SIGNAL ;
    PORT
      LAYER M5 ;
        RECT  43.632 34.476 43.656 34.56 ;
    END
  END i_d[166]
  PIN i_d[167]
    DIRECTION INPUT ;
    USE SIGNAL ;
    PORT
      LAYER M5 ;
        RECT  43.728 34.476 43.752 34.56 ;
    END
  END i_d[167]
  PIN i_d[168]
    DIRECTION INPUT ;
    USE SIGNAL ;
    PORT
      LAYER M5 ;
        RECT  43.824 34.476 43.848 34.56 ;
    END
  END i_d[168]
  PIN i_d[169]
    DIRECTION INPUT ;
    USE SIGNAL ;
    PORT
      LAYER M5 ;
        RECT  43.92 34.476 43.944 34.56 ;
    END
  END i_d[169]
  PIN i_d[16]
    DIRECTION INPUT ;
    USE SIGNAL ;
    PORT
      LAYER M5 ;
        RECT  41.52 34.476 41.544 34.56 ;
    END
  END i_d[16]
  PIN i_d[170]
    DIRECTION INPUT ;
    USE SIGNAL ;
    PORT
      LAYER M5 ;
        RECT  44.016 34.476 44.04 34.56 ;
    END
  END i_d[170]
  PIN i_d[171]
    DIRECTION INPUT ;
    USE SIGNAL ;
    PORT
      LAYER M5 ;
        RECT  44.112 34.476 44.136 34.56 ;
    END
  END i_d[171]
  PIN i_d[172]
    DIRECTION INPUT ;
    USE SIGNAL ;
    PORT
      LAYER M5 ;
        RECT  44.208 34.476 44.232 34.56 ;
    END
  END i_d[172]
  PIN i_d[173]
    DIRECTION INPUT ;
    USE SIGNAL ;
    PORT
      LAYER M5 ;
        RECT  44.304 34.476 44.328 34.56 ;
    END
  END i_d[173]
  PIN i_d[174]
    DIRECTION INPUT ;
    USE SIGNAL ;
    PORT
      LAYER M5 ;
        RECT  44.4 34.476 44.424 34.56 ;
    END
  END i_d[174]
  PIN i_d[175]
    DIRECTION INPUT ;
    USE SIGNAL ;
    PORT
      LAYER M5 ;
        RECT  44.496 34.476 44.52 34.56 ;
    END
  END i_d[175]
  PIN i_d[176]
    DIRECTION INPUT ;
    USE SIGNAL ;
    PORT
      LAYER M5 ;
        RECT  44.592 34.476 44.616 34.56 ;
    END
  END i_d[176]
  PIN i_d[177]
    DIRECTION INPUT ;
    USE SIGNAL ;
    PORT
      LAYER M5 ;
        RECT  44.688 34.476 44.712 34.56 ;
    END
  END i_d[177]
  PIN i_d[178]
    DIRECTION INPUT ;
    USE SIGNAL ;
    PORT
      LAYER M5 ;
        RECT  44.784 34.476 44.808 34.56 ;
    END
  END i_d[178]
  PIN i_d[179]
    DIRECTION INPUT ;
    USE SIGNAL ;
    PORT
      LAYER M5 ;
        RECT  44.88 34.476 44.904 34.56 ;
    END
  END i_d[179]
  PIN i_d[17]
    DIRECTION INPUT ;
    USE SIGNAL ;
    PORT
      LAYER M5 ;
        RECT  41.616 34.476 41.64 34.56 ;
    END
  END i_d[17]
  PIN i_d[180]
    DIRECTION INPUT ;
    USE SIGNAL ;
    PORT
      LAYER M5 ;
        RECT  44.976 34.476 45 34.56 ;
    END
  END i_d[180]
  PIN i_d[181]
    DIRECTION INPUT ;
    USE SIGNAL ;
    PORT
      LAYER M5 ;
        RECT  45.072 34.476 45.096 34.56 ;
    END
  END i_d[181]
  PIN i_d[182]
    DIRECTION INPUT ;
    USE SIGNAL ;
    PORT
      LAYER M5 ;
        RECT  45.168 34.476 45.192 34.56 ;
    END
  END i_d[182]
  PIN i_d[183]
    DIRECTION INPUT ;
    USE SIGNAL ;
    PORT
      LAYER M5 ;
        RECT  45.264 34.476 45.288 34.56 ;
    END
  END i_d[183]
  PIN i_d[184]
    DIRECTION INPUT ;
    USE SIGNAL ;
    PORT
      LAYER M5 ;
        RECT  45.36 34.476 45.384 34.56 ;
    END
  END i_d[184]
  PIN i_d[185]
    DIRECTION INPUT ;
    USE SIGNAL ;
    PORT
      LAYER M5 ;
        RECT  45.456 34.476 45.48 34.56 ;
    END
  END i_d[185]
  PIN i_d[186]
    DIRECTION INPUT ;
    USE SIGNAL ;
    PORT
      LAYER M5 ;
        RECT  45.552 34.476 45.576 34.56 ;
    END
  END i_d[186]
  PIN i_d[187]
    DIRECTION INPUT ;
    USE SIGNAL ;
    PORT
      LAYER M5 ;
        RECT  45.648 34.476 45.672 34.56 ;
    END
  END i_d[187]
  PIN i_d[188]
    DIRECTION INPUT ;
    USE SIGNAL ;
    PORT
      LAYER M5 ;
        RECT  45.744 34.476 45.768 34.56 ;
    END
  END i_d[188]
  PIN i_d[189]
    DIRECTION INPUT ;
    USE SIGNAL ;
    PORT
      LAYER M5 ;
        RECT  45.84 34.476 45.864 34.56 ;
    END
  END i_d[189]
  PIN i_d[18]
    DIRECTION INPUT ;
    USE SIGNAL ;
    PORT
      LAYER M5 ;
        RECT  41.712 34.476 41.736 34.56 ;
    END
  END i_d[18]
  PIN i_d[190]
    DIRECTION INPUT ;
    USE SIGNAL ;
    PORT
      LAYER M5 ;
        RECT  45.936 34.476 45.96 34.56 ;
    END
  END i_d[190]
  PIN i_d[191]
    DIRECTION INPUT ;
    USE SIGNAL ;
    PORT
      LAYER M5 ;
        RECT  46.032 34.476 46.056 34.56 ;
    END
  END i_d[191]
  PIN i_d[192]
    DIRECTION INPUT ;
    USE SIGNAL ;
    PORT
      LAYER M5 ;
        RECT  11.568 34.476 11.592 34.56 ;
    END
  END i_d[192]
  PIN i_d[193]
    DIRECTION INPUT ;
    USE SIGNAL ;
    PORT
      LAYER M5 ;
        RECT  11.664 34.476 11.688 34.56 ;
    END
  END i_d[193]
  PIN i_d[194]
    DIRECTION INPUT ;
    USE SIGNAL ;
    PORT
      LAYER M5 ;
        RECT  11.76 34.476 11.784 34.56 ;
    END
  END i_d[194]
  PIN i_d[195]
    DIRECTION INPUT ;
    USE SIGNAL ;
    PORT
      LAYER M5 ;
        RECT  11.856 34.476 11.88 34.56 ;
    END
  END i_d[195]
  PIN i_d[196]
    DIRECTION INPUT ;
    USE SIGNAL ;
    PORT
      LAYER M5 ;
        RECT  11.952 34.476 11.976 34.56 ;
    END
  END i_d[196]
  PIN i_d[197]
    DIRECTION INPUT ;
    USE SIGNAL ;
    PORT
      LAYER M5 ;
        RECT  12.048 34.476 12.072 34.56 ;
    END
  END i_d[197]
  PIN i_d[198]
    DIRECTION INPUT ;
    USE SIGNAL ;
    PORT
      LAYER M5 ;
        RECT  12.144 34.476 12.168 34.56 ;
    END
  END i_d[198]
  PIN i_d[199]
    DIRECTION INPUT ;
    USE SIGNAL ;
    PORT
      LAYER M5 ;
        RECT  12.24 34.476 12.264 34.56 ;
    END
  END i_d[199]
  PIN i_d[19]
    DIRECTION INPUT ;
    USE SIGNAL ;
    PORT
      LAYER M5 ;
        RECT  41.808 34.476 41.832 34.56 ;
    END
  END i_d[19]
  PIN i_d[1]
    DIRECTION INPUT ;
    USE SIGNAL ;
    PORT
      LAYER M5 ;
        RECT  40.08 34.476 40.104 34.56 ;
    END
  END i_d[1]
  PIN i_d[200]
    DIRECTION INPUT ;
    USE SIGNAL ;
    PORT
      LAYER M5 ;
        RECT  12.336 34.476 12.36 34.56 ;
    END
  END i_d[200]
  PIN i_d[201]
    DIRECTION INPUT ;
    USE SIGNAL ;
    PORT
      LAYER M5 ;
        RECT  12.432 34.476 12.456 34.56 ;
    END
  END i_d[201]
  PIN i_d[202]
    DIRECTION INPUT ;
    USE SIGNAL ;
    PORT
      LAYER M5 ;
        RECT  12.528 34.476 12.552 34.56 ;
    END
  END i_d[202]
  PIN i_d[203]
    DIRECTION INPUT ;
    USE SIGNAL ;
    PORT
      LAYER M5 ;
        RECT  12.624 34.476 12.648 34.56 ;
    END
  END i_d[203]
  PIN i_d[204]
    DIRECTION INPUT ;
    USE SIGNAL ;
    PORT
      LAYER M5 ;
        RECT  12.72 34.476 12.744 34.56 ;
    END
  END i_d[204]
  PIN i_d[205]
    DIRECTION INPUT ;
    USE SIGNAL ;
    PORT
      LAYER M5 ;
        RECT  12.816 34.476 12.84 34.56 ;
    END
  END i_d[205]
  PIN i_d[206]
    DIRECTION INPUT ;
    USE SIGNAL ;
    PORT
      LAYER M5 ;
        RECT  12.912 34.476 12.936 34.56 ;
    END
  END i_d[206]
  PIN i_d[207]
    DIRECTION INPUT ;
    USE SIGNAL ;
    PORT
      LAYER M5 ;
        RECT  13.008 34.476 13.032 34.56 ;
    END
  END i_d[207]
  PIN i_d[208]
    DIRECTION INPUT ;
    USE SIGNAL ;
    PORT
      LAYER M5 ;
        RECT  13.104 34.476 13.128 34.56 ;
    END
  END i_d[208]
  PIN i_d[209]
    DIRECTION INPUT ;
    USE SIGNAL ;
    PORT
      LAYER M5 ;
        RECT  13.2 34.476 13.224 34.56 ;
    END
  END i_d[209]
  PIN i_d[20]
    DIRECTION INPUT ;
    USE SIGNAL ;
    PORT
      LAYER M5 ;
        RECT  41.904 34.476 41.928 34.56 ;
    END
  END i_d[20]
  PIN i_d[210]
    DIRECTION INPUT ;
    USE SIGNAL ;
    PORT
      LAYER M5 ;
        RECT  13.296 34.476 13.32 34.56 ;
    END
  END i_d[210]
  PIN i_d[211]
    DIRECTION INPUT ;
    USE SIGNAL ;
    PORT
      LAYER M5 ;
        RECT  13.392 34.476 13.416 34.56 ;
    END
  END i_d[211]
  PIN i_d[212]
    DIRECTION INPUT ;
    USE SIGNAL ;
    PORT
      LAYER M5 ;
        RECT  13.488 34.476 13.512 34.56 ;
    END
  END i_d[212]
  PIN i_d[213]
    DIRECTION INPUT ;
    USE SIGNAL ;
    PORT
      LAYER M5 ;
        RECT  13.584 34.476 13.608 34.56 ;
    END
  END i_d[213]
  PIN i_d[214]
    DIRECTION INPUT ;
    USE SIGNAL ;
    PORT
      LAYER M5 ;
        RECT  13.68 34.476 13.704 34.56 ;
    END
  END i_d[214]
  PIN i_d[215]
    DIRECTION INPUT ;
    USE SIGNAL ;
    PORT
      LAYER M5 ;
        RECT  13.776 34.476 13.8 34.56 ;
    END
  END i_d[215]
  PIN i_d[216]
    DIRECTION INPUT ;
    USE SIGNAL ;
    PORT
      LAYER M5 ;
        RECT  13.872 34.476 13.896 34.56 ;
    END
  END i_d[216]
  PIN i_d[217]
    DIRECTION INPUT ;
    USE SIGNAL ;
    PORT
      LAYER M5 ;
        RECT  13.968 34.476 13.992 34.56 ;
    END
  END i_d[217]
  PIN i_d[218]
    DIRECTION INPUT ;
    USE SIGNAL ;
    PORT
      LAYER M5 ;
        RECT  14.064 34.476 14.088 34.56 ;
    END
  END i_d[218]
  PIN i_d[219]
    DIRECTION INPUT ;
    USE SIGNAL ;
    PORT
      LAYER M5 ;
        RECT  14.16 34.476 14.184 34.56 ;
    END
  END i_d[219]
  PIN i_d[21]
    DIRECTION INPUT ;
    USE SIGNAL ;
    PORT
      LAYER M5 ;
        RECT  42 34.476 42.024 34.56 ;
    END
  END i_d[21]
  PIN i_d[220]
    DIRECTION INPUT ;
    USE SIGNAL ;
    PORT
      LAYER M5 ;
        RECT  14.256 34.476 14.28 34.56 ;
    END
  END i_d[220]
  PIN i_d[221]
    DIRECTION INPUT ;
    USE SIGNAL ;
    PORT
      LAYER M5 ;
        RECT  14.352 34.476 14.376 34.56 ;
    END
  END i_d[221]
  PIN i_d[222]
    DIRECTION INPUT ;
    USE SIGNAL ;
    PORT
      LAYER M5 ;
        RECT  14.448 34.476 14.472 34.56 ;
    END
  END i_d[222]
  PIN i_d[223]
    DIRECTION INPUT ;
    USE SIGNAL ;
    PORT
      LAYER M5 ;
        RECT  14.544 34.476 14.568 34.56 ;
    END
  END i_d[223]
  PIN i_d[224]
    DIRECTION INPUT ;
    USE SIGNAL ;
    PORT
      LAYER M5 ;
        RECT  26.928 34.476 26.952 34.56 ;
    END
  END i_d[224]
  PIN i_d[225]
    DIRECTION INPUT ;
    USE SIGNAL ;
    PORT
      LAYER M5 ;
        RECT  27.024 34.476 27.048 34.56 ;
    END
  END i_d[225]
  PIN i_d[226]
    DIRECTION INPUT ;
    USE SIGNAL ;
    PORT
      LAYER M5 ;
        RECT  27.12 34.476 27.144 34.56 ;
    END
  END i_d[226]
  PIN i_d[227]
    DIRECTION INPUT ;
    USE SIGNAL ;
    PORT
      LAYER M5 ;
        RECT  27.216 34.476 27.24 34.56 ;
    END
  END i_d[227]
  PIN i_d[228]
    DIRECTION INPUT ;
    USE SIGNAL ;
    PORT
      LAYER M5 ;
        RECT  27.312 34.476 27.336 34.56 ;
    END
  END i_d[228]
  PIN i_d[229]
    DIRECTION INPUT ;
    USE SIGNAL ;
    PORT
      LAYER M5 ;
        RECT  27.408 34.476 27.432 34.56 ;
    END
  END i_d[229]
  PIN i_d[22]
    DIRECTION INPUT ;
    USE SIGNAL ;
    PORT
      LAYER M5 ;
        RECT  42.096 34.476 42.12 34.56 ;
    END
  END i_d[22]
  PIN i_d[230]
    DIRECTION INPUT ;
    USE SIGNAL ;
    PORT
      LAYER M5 ;
        RECT  27.504 34.476 27.528 34.56 ;
    END
  END i_d[230]
  PIN i_d[231]
    DIRECTION INPUT ;
    USE SIGNAL ;
    PORT
      LAYER M5 ;
        RECT  27.6 34.476 27.624 34.56 ;
    END
  END i_d[231]
  PIN i_d[232]
    DIRECTION INPUT ;
    USE SIGNAL ;
    PORT
      LAYER M5 ;
        RECT  27.696 34.476 27.72 34.56 ;
    END
  END i_d[232]
  PIN i_d[233]
    DIRECTION INPUT ;
    USE SIGNAL ;
    PORT
      LAYER M5 ;
        RECT  27.792 34.476 27.816 34.56 ;
    END
  END i_d[233]
  PIN i_d[234]
    DIRECTION INPUT ;
    USE SIGNAL ;
    PORT
      LAYER M5 ;
        RECT  27.888 34.476 27.912 34.56 ;
    END
  END i_d[234]
  PIN i_d[235]
    DIRECTION INPUT ;
    USE SIGNAL ;
    PORT
      LAYER M5 ;
        RECT  27.984 34.476 28.008 34.56 ;
    END
  END i_d[235]
  PIN i_d[236]
    DIRECTION INPUT ;
    USE SIGNAL ;
    PORT
      LAYER M5 ;
        RECT  28.08 34.476 28.104 34.56 ;
    END
  END i_d[236]
  PIN i_d[237]
    DIRECTION INPUT ;
    USE SIGNAL ;
    PORT
      LAYER M5 ;
        RECT  28.176 34.476 28.2 34.56 ;
    END
  END i_d[237]
  PIN i_d[238]
    DIRECTION INPUT ;
    USE SIGNAL ;
    PORT
      LAYER M5 ;
        RECT  28.272 34.476 28.296 34.56 ;
    END
  END i_d[238]
  PIN i_d[239]
    DIRECTION INPUT ;
    USE SIGNAL ;
    PORT
      LAYER M5 ;
        RECT  28.368 34.476 28.392 34.56 ;
    END
  END i_d[239]
  PIN i_d[23]
    DIRECTION INPUT ;
    USE SIGNAL ;
    PORT
      LAYER M5 ;
        RECT  42.192 34.476 42.216 34.56 ;
    END
  END i_d[23]
  PIN i_d[240]
    DIRECTION INPUT ;
    USE SIGNAL ;
    PORT
      LAYER M5 ;
        RECT  28.464 34.476 28.488 34.56 ;
    END
  END i_d[240]
  PIN i_d[241]
    DIRECTION INPUT ;
    USE SIGNAL ;
    PORT
      LAYER M5 ;
        RECT  28.56 34.476 28.584 34.56 ;
    END
  END i_d[241]
  PIN i_d[242]
    DIRECTION INPUT ;
    USE SIGNAL ;
    PORT
      LAYER M5 ;
        RECT  28.656 34.476 28.68 34.56 ;
    END
  END i_d[242]
  PIN i_d[243]
    DIRECTION INPUT ;
    USE SIGNAL ;
    PORT
      LAYER M5 ;
        RECT  28.752 34.476 28.776 34.56 ;
    END
  END i_d[243]
  PIN i_d[244]
    DIRECTION INPUT ;
    USE SIGNAL ;
    PORT
      LAYER M5 ;
        RECT  28.848 34.476 28.872 34.56 ;
    END
  END i_d[244]
  PIN i_d[245]
    DIRECTION INPUT ;
    USE SIGNAL ;
    PORT
      LAYER M5 ;
        RECT  28.944 34.476 28.968 34.56 ;
    END
  END i_d[245]
  PIN i_d[246]
    DIRECTION INPUT ;
    USE SIGNAL ;
    PORT
      LAYER M5 ;
        RECT  29.04 34.476 29.064 34.56 ;
    END
  END i_d[246]
  PIN i_d[247]
    DIRECTION INPUT ;
    USE SIGNAL ;
    PORT
      LAYER M5 ;
        RECT  29.136 34.476 29.16 34.56 ;
    END
  END i_d[247]
  PIN i_d[248]
    DIRECTION INPUT ;
    USE SIGNAL ;
    PORT
      LAYER M5 ;
        RECT  29.232 34.476 29.256 34.56 ;
    END
  END i_d[248]
  PIN i_d[249]
    DIRECTION INPUT ;
    USE SIGNAL ;
    PORT
      LAYER M5 ;
        RECT  29.328 34.476 29.352 34.56 ;
    END
  END i_d[249]
  PIN i_d[24]
    DIRECTION INPUT ;
    USE SIGNAL ;
    PORT
      LAYER M5 ;
        RECT  42.288 34.476 42.312 34.56 ;
    END
  END i_d[24]
  PIN i_d[250]
    DIRECTION INPUT ;
    USE SIGNAL ;
    PORT
      LAYER M5 ;
        RECT  29.424 34.476 29.448 34.56 ;
    END
  END i_d[250]
  PIN i_d[251]
    DIRECTION INPUT ;
    USE SIGNAL ;
    PORT
      LAYER M5 ;
        RECT  29.52 34.476 29.544 34.56 ;
    END
  END i_d[251]
  PIN i_d[252]
    DIRECTION INPUT ;
    USE SIGNAL ;
    PORT
      LAYER M5 ;
        RECT  29.616 34.476 29.64 34.56 ;
    END
  END i_d[252]
  PIN i_d[253]
    DIRECTION INPUT ;
    USE SIGNAL ;
    PORT
      LAYER M5 ;
        RECT  29.712 34.476 29.736 34.56 ;
    END
  END i_d[253]
  PIN i_d[254]
    DIRECTION INPUT ;
    USE SIGNAL ;
    PORT
      LAYER M5 ;
        RECT  29.808 34.476 29.832 34.56 ;
    END
  END i_d[254]
  PIN i_d[255]
    DIRECTION INPUT ;
    USE SIGNAL ;
    PORT
      LAYER M5 ;
        RECT  29.904 34.476 29.928 34.56 ;
    END
  END i_d[255]
  PIN i_d[256]
    DIRECTION INPUT ;
    USE SIGNAL ;
    PORT
      LAYER M5 ;
        RECT  23.856 34.476 23.88 34.56 ;
    END
  END i_d[256]
  PIN i_d[257]
    DIRECTION INPUT ;
    USE SIGNAL ;
    PORT
      LAYER M5 ;
        RECT  23.952 34.476 23.976 34.56 ;
    END
  END i_d[257]
  PIN i_d[258]
    DIRECTION INPUT ;
    USE SIGNAL ;
    PORT
      LAYER M5 ;
        RECT  24.048 34.476 24.072 34.56 ;
    END
  END i_d[258]
  PIN i_d[259]
    DIRECTION INPUT ;
    USE SIGNAL ;
    PORT
      LAYER M5 ;
        RECT  24.144 34.476 24.168 34.56 ;
    END
  END i_d[259]
  PIN i_d[25]
    DIRECTION INPUT ;
    USE SIGNAL ;
    PORT
      LAYER M5 ;
        RECT  42.384 34.476 42.408 34.56 ;
    END
  END i_d[25]
  PIN i_d[260]
    DIRECTION INPUT ;
    USE SIGNAL ;
    PORT
      LAYER M5 ;
        RECT  24.24 34.476 24.264 34.56 ;
    END
  END i_d[260]
  PIN i_d[261]
    DIRECTION INPUT ;
    USE SIGNAL ;
    PORT
      LAYER M5 ;
        RECT  24.336 34.476 24.36 34.56 ;
    END
  END i_d[261]
  PIN i_d[262]
    DIRECTION INPUT ;
    USE SIGNAL ;
    PORT
      LAYER M5 ;
        RECT  24.432 34.476 24.456 34.56 ;
    END
  END i_d[262]
  PIN i_d[263]
    DIRECTION INPUT ;
    USE SIGNAL ;
    PORT
      LAYER M5 ;
        RECT  24.528 34.476 24.552 34.56 ;
    END
  END i_d[263]
  PIN i_d[264]
    DIRECTION INPUT ;
    USE SIGNAL ;
    PORT
      LAYER M5 ;
        RECT  24.624 34.476 24.648 34.56 ;
    END
  END i_d[264]
  PIN i_d[265]
    DIRECTION INPUT ;
    USE SIGNAL ;
    PORT
      LAYER M5 ;
        RECT  24.72 34.476 24.744 34.56 ;
    END
  END i_d[265]
  PIN i_d[266]
    DIRECTION INPUT ;
    USE SIGNAL ;
    PORT
      LAYER M5 ;
        RECT  24.816 34.476 24.84 34.56 ;
    END
  END i_d[266]
  PIN i_d[267]
    DIRECTION INPUT ;
    USE SIGNAL ;
    PORT
      LAYER M5 ;
        RECT  24.912 34.476 24.936 34.56 ;
    END
  END i_d[267]
  PIN i_d[268]
    DIRECTION INPUT ;
    USE SIGNAL ;
    PORT
      LAYER M5 ;
        RECT  25.008 34.476 25.032 34.56 ;
    END
  END i_d[268]
  PIN i_d[269]
    DIRECTION INPUT ;
    USE SIGNAL ;
    PORT
      LAYER M5 ;
        RECT  25.104 34.476 25.128 34.56 ;
    END
  END i_d[269]
  PIN i_d[26]
    DIRECTION INPUT ;
    USE SIGNAL ;
    PORT
      LAYER M5 ;
        RECT  42.48 34.476 42.504 34.56 ;
    END
  END i_d[26]
  PIN i_d[270]
    DIRECTION INPUT ;
    USE SIGNAL ;
    PORT
      LAYER M5 ;
        RECT  25.2 34.476 25.224 34.56 ;
    END
  END i_d[270]
  PIN i_d[271]
    DIRECTION INPUT ;
    USE SIGNAL ;
    PORT
      LAYER M5 ;
        RECT  25.296 34.476 25.32 34.56 ;
    END
  END i_d[271]
  PIN i_d[272]
    DIRECTION INPUT ;
    USE SIGNAL ;
    PORT
      LAYER M5 ;
        RECT  25.392 34.476 25.416 34.56 ;
    END
  END i_d[272]
  PIN i_d[273]
    DIRECTION INPUT ;
    USE SIGNAL ;
    PORT
      LAYER M5 ;
        RECT  25.488 34.476 25.512 34.56 ;
    END
  END i_d[273]
  PIN i_d[274]
    DIRECTION INPUT ;
    USE SIGNAL ;
    PORT
      LAYER M5 ;
        RECT  25.584 34.476 25.608 34.56 ;
    END
  END i_d[274]
  PIN i_d[275]
    DIRECTION INPUT ;
    USE SIGNAL ;
    PORT
      LAYER M5 ;
        RECT  25.68 34.476 25.704 34.56 ;
    END
  END i_d[275]
  PIN i_d[276]
    DIRECTION INPUT ;
    USE SIGNAL ;
    PORT
      LAYER M5 ;
        RECT  25.776 34.476 25.8 34.56 ;
    END
  END i_d[276]
  PIN i_d[277]
    DIRECTION INPUT ;
    USE SIGNAL ;
    PORT
      LAYER M5 ;
        RECT  25.872 34.476 25.896 34.56 ;
    END
  END i_d[277]
  PIN i_d[278]
    DIRECTION INPUT ;
    USE SIGNAL ;
    PORT
      LAYER M5 ;
        RECT  25.968 34.476 25.992 34.56 ;
    END
  END i_d[278]
  PIN i_d[279]
    DIRECTION INPUT ;
    USE SIGNAL ;
    PORT
      LAYER M5 ;
        RECT  26.064 34.476 26.088 34.56 ;
    END
  END i_d[279]
  PIN i_d[27]
    DIRECTION INPUT ;
    USE SIGNAL ;
    PORT
      LAYER M5 ;
        RECT  42.576 34.476 42.6 34.56 ;
    END
  END i_d[27]
  PIN i_d[280]
    DIRECTION INPUT ;
    USE SIGNAL ;
    PORT
      LAYER M5 ;
        RECT  26.16 34.476 26.184 34.56 ;
    END
  END i_d[280]
  PIN i_d[281]
    DIRECTION INPUT ;
    USE SIGNAL ;
    PORT
      LAYER M5 ;
        RECT  26.256 34.476 26.28 34.56 ;
    END
  END i_d[281]
  PIN i_d[282]
    DIRECTION INPUT ;
    USE SIGNAL ;
    PORT
      LAYER M5 ;
        RECT  26.352 34.476 26.376 34.56 ;
    END
  END i_d[282]
  PIN i_d[283]
    DIRECTION INPUT ;
    USE SIGNAL ;
    PORT
      LAYER M5 ;
        RECT  26.448 34.476 26.472 34.56 ;
    END
  END i_d[283]
  PIN i_d[284]
    DIRECTION INPUT ;
    USE SIGNAL ;
    PORT
      LAYER M5 ;
        RECT  26.544 34.476 26.568 34.56 ;
    END
  END i_d[284]
  PIN i_d[285]
    DIRECTION INPUT ;
    USE SIGNAL ;
    PORT
      LAYER M5 ;
        RECT  26.64 34.476 26.664 34.56 ;
    END
  END i_d[285]
  PIN i_d[286]
    DIRECTION INPUT ;
    USE SIGNAL ;
    PORT
      LAYER M5 ;
        RECT  26.736 34.476 26.76 34.56 ;
    END
  END i_d[286]
  PIN i_d[287]
    DIRECTION INPUT ;
    USE SIGNAL ;
    PORT
      LAYER M5 ;
        RECT  26.832 34.476 26.856 34.56 ;
    END
  END i_d[287]
  PIN i_d[288]
    DIRECTION INPUT ;
    USE SIGNAL ;
    PORT
      LAYER M5 ;
        RECT  17.712 34.476 17.736 34.56 ;
    END
  END i_d[288]
  PIN i_d[289]
    DIRECTION INPUT ;
    USE SIGNAL ;
    PORT
      LAYER M5 ;
        RECT  17.808 34.476 17.832 34.56 ;
    END
  END i_d[289]
  PIN i_d[28]
    DIRECTION INPUT ;
    USE SIGNAL ;
    PORT
      LAYER M5 ;
        RECT  42.672 34.476 42.696 34.56 ;
    END
  END i_d[28]
  PIN i_d[290]
    DIRECTION INPUT ;
    USE SIGNAL ;
    PORT
      LAYER M5 ;
        RECT  17.904 34.476 17.928 34.56 ;
    END
  END i_d[290]
  PIN i_d[291]
    DIRECTION INPUT ;
    USE SIGNAL ;
    PORT
      LAYER M5 ;
        RECT  18 34.476 18.024 34.56 ;
    END
  END i_d[291]
  PIN i_d[292]
    DIRECTION INPUT ;
    USE SIGNAL ;
    PORT
      LAYER M5 ;
        RECT  18.096 34.476 18.12 34.56 ;
    END
  END i_d[292]
  PIN i_d[293]
    DIRECTION INPUT ;
    USE SIGNAL ;
    PORT
      LAYER M5 ;
        RECT  18.192 34.476 18.216 34.56 ;
    END
  END i_d[293]
  PIN i_d[294]
    DIRECTION INPUT ;
    USE SIGNAL ;
    PORT
      LAYER M5 ;
        RECT  18.288 34.476 18.312 34.56 ;
    END
  END i_d[294]
  PIN i_d[295]
    DIRECTION INPUT ;
    USE SIGNAL ;
    PORT
      LAYER M5 ;
        RECT  18.384 34.476 18.408 34.56 ;
    END
  END i_d[295]
  PIN i_d[296]
    DIRECTION INPUT ;
    USE SIGNAL ;
    PORT
      LAYER M5 ;
        RECT  18.48 34.476 18.504 34.56 ;
    END
  END i_d[296]
  PIN i_d[297]
    DIRECTION INPUT ;
    USE SIGNAL ;
    PORT
      LAYER M5 ;
        RECT  18.576 34.476 18.6 34.56 ;
    END
  END i_d[297]
  PIN i_d[298]
    DIRECTION INPUT ;
    USE SIGNAL ;
    PORT
      LAYER M5 ;
        RECT  18.672 34.476 18.696 34.56 ;
    END
  END i_d[298]
  PIN i_d[299]
    DIRECTION INPUT ;
    USE SIGNAL ;
    PORT
      LAYER M5 ;
        RECT  18.768 34.476 18.792 34.56 ;
    END
  END i_d[299]
  PIN i_d[29]
    DIRECTION INPUT ;
    USE SIGNAL ;
    PORT
      LAYER M5 ;
        RECT  42.768 34.476 42.792 34.56 ;
    END
  END i_d[29]
  PIN i_d[2]
    DIRECTION INPUT ;
    USE SIGNAL ;
    PORT
      LAYER M5 ;
        RECT  40.176 34.476 40.2 34.56 ;
    END
  END i_d[2]
  PIN i_d[300]
    DIRECTION INPUT ;
    USE SIGNAL ;
    PORT
      LAYER M5 ;
        RECT  18.864 34.476 18.888 34.56 ;
    END
  END i_d[300]
  PIN i_d[301]
    DIRECTION INPUT ;
    USE SIGNAL ;
    PORT
      LAYER M5 ;
        RECT  18.96 34.476 18.984 34.56 ;
    END
  END i_d[301]
  PIN i_d[302]
    DIRECTION INPUT ;
    USE SIGNAL ;
    PORT
      LAYER M5 ;
        RECT  19.056 34.476 19.08 34.56 ;
    END
  END i_d[302]
  PIN i_d[303]
    DIRECTION INPUT ;
    USE SIGNAL ;
    PORT
      LAYER M5 ;
        RECT  19.152 34.476 19.176 34.56 ;
    END
  END i_d[303]
  PIN i_d[304]
    DIRECTION INPUT ;
    USE SIGNAL ;
    PORT
      LAYER M5 ;
        RECT  19.248 34.476 19.272 34.56 ;
    END
  END i_d[304]
  PIN i_d[305]
    DIRECTION INPUT ;
    USE SIGNAL ;
    PORT
      LAYER M5 ;
        RECT  19.344 34.476 19.368 34.56 ;
    END
  END i_d[305]
  PIN i_d[306]
    DIRECTION INPUT ;
    USE SIGNAL ;
    PORT
      LAYER M5 ;
        RECT  19.44 34.476 19.464 34.56 ;
    END
  END i_d[306]
  PIN i_d[307]
    DIRECTION INPUT ;
    USE SIGNAL ;
    PORT
      LAYER M5 ;
        RECT  19.536 34.476 19.56 34.56 ;
    END
  END i_d[307]
  PIN i_d[308]
    DIRECTION INPUT ;
    USE SIGNAL ;
    PORT
      LAYER M5 ;
        RECT  19.632 34.476 19.656 34.56 ;
    END
  END i_d[308]
  PIN i_d[309]
    DIRECTION INPUT ;
    USE SIGNAL ;
    PORT
      LAYER M5 ;
        RECT  19.728 34.476 19.752 34.56 ;
    END
  END i_d[309]
  PIN i_d[30]
    DIRECTION INPUT ;
    USE SIGNAL ;
    PORT
      LAYER M5 ;
        RECT  42.864 34.476 42.888 34.56 ;
    END
  END i_d[30]
  PIN i_d[310]
    DIRECTION INPUT ;
    USE SIGNAL ;
    PORT
      LAYER M5 ;
        RECT  19.824 34.476 19.848 34.56 ;
    END
  END i_d[310]
  PIN i_d[311]
    DIRECTION INPUT ;
    USE SIGNAL ;
    PORT
      LAYER M5 ;
        RECT  19.92 34.476 19.944 34.56 ;
    END
  END i_d[311]
  PIN i_d[312]
    DIRECTION INPUT ;
    USE SIGNAL ;
    PORT
      LAYER M5 ;
        RECT  20.016 34.476 20.04 34.56 ;
    END
  END i_d[312]
  PIN i_d[313]
    DIRECTION INPUT ;
    USE SIGNAL ;
    PORT
      LAYER M5 ;
        RECT  20.112 34.476 20.136 34.56 ;
    END
  END i_d[313]
  PIN i_d[314]
    DIRECTION INPUT ;
    USE SIGNAL ;
    PORT
      LAYER M5 ;
        RECT  20.208 34.476 20.232 34.56 ;
    END
  END i_d[314]
  PIN i_d[315]
    DIRECTION INPUT ;
    USE SIGNAL ;
    PORT
      LAYER M5 ;
        RECT  20.304 34.476 20.328 34.56 ;
    END
  END i_d[315]
  PIN i_d[316]
    DIRECTION INPUT ;
    USE SIGNAL ;
    PORT
      LAYER M5 ;
        RECT  20.4 34.476 20.424 34.56 ;
    END
  END i_d[316]
  PIN i_d[317]
    DIRECTION INPUT ;
    USE SIGNAL ;
    PORT
      LAYER M5 ;
        RECT  20.496 34.476 20.52 34.56 ;
    END
  END i_d[317]
  PIN i_d[318]
    DIRECTION INPUT ;
    USE SIGNAL ;
    PORT
      LAYER M5 ;
        RECT  20.592 34.476 20.616 34.56 ;
    END
  END i_d[318]
  PIN i_d[319]
    DIRECTION INPUT ;
    USE SIGNAL ;
    PORT
      LAYER M5 ;
        RECT  20.688 34.476 20.712 34.56 ;
    END
  END i_d[319]
  PIN i_d[31]
    DIRECTION INPUT ;
    USE SIGNAL ;
    PORT
      LAYER M5 ;
        RECT  42.96 34.476 42.984 34.56 ;
    END
  END i_d[31]
  PIN i_d[320]
    DIRECTION INPUT ;
    USE SIGNAL ;
    PORT
      LAYER M5 ;
        RECT  20.784 34.476 20.808 34.56 ;
    END
  END i_d[320]
  PIN i_d[321]
    DIRECTION INPUT ;
    USE SIGNAL ;
    PORT
      LAYER M5 ;
        RECT  20.88 34.476 20.904 34.56 ;
    END
  END i_d[321]
  PIN i_d[322]
    DIRECTION INPUT ;
    USE SIGNAL ;
    PORT
      LAYER M5 ;
        RECT  20.976 34.476 21 34.56 ;
    END
  END i_d[322]
  PIN i_d[323]
    DIRECTION INPUT ;
    USE SIGNAL ;
    PORT
      LAYER M5 ;
        RECT  21.072 34.476 21.096 34.56 ;
    END
  END i_d[323]
  PIN i_d[324]
    DIRECTION INPUT ;
    USE SIGNAL ;
    PORT
      LAYER M5 ;
        RECT  21.168 34.476 21.192 34.56 ;
    END
  END i_d[324]
  PIN i_d[325]
    DIRECTION INPUT ;
    USE SIGNAL ;
    PORT
      LAYER M5 ;
        RECT  21.264 34.476 21.288 34.56 ;
    END
  END i_d[325]
  PIN i_d[326]
    DIRECTION INPUT ;
    USE SIGNAL ;
    PORT
      LAYER M5 ;
        RECT  21.36 34.476 21.384 34.56 ;
    END
  END i_d[326]
  PIN i_d[327]
    DIRECTION INPUT ;
    USE SIGNAL ;
    PORT
      LAYER M5 ;
        RECT  21.456 34.476 21.48 34.56 ;
    END
  END i_d[327]
  PIN i_d[328]
    DIRECTION INPUT ;
    USE SIGNAL ;
    PORT
      LAYER M5 ;
        RECT  21.552 34.476 21.576 34.56 ;
    END
  END i_d[328]
  PIN i_d[329]
    DIRECTION INPUT ;
    USE SIGNAL ;
    PORT
      LAYER M5 ;
        RECT  21.648 34.476 21.672 34.56 ;
    END
  END i_d[329]
  PIN i_d[32]
    DIRECTION INPUT ;
    USE SIGNAL ;
    PORT
      LAYER M5 ;
        RECT  46.128 34.476 46.152 34.56 ;
    END
  END i_d[32]
  PIN i_d[330]
    DIRECTION INPUT ;
    USE SIGNAL ;
    PORT
      LAYER M5 ;
        RECT  21.744 34.476 21.768 34.56 ;
    END
  END i_d[330]
  PIN i_d[331]
    DIRECTION INPUT ;
    USE SIGNAL ;
    PORT
      LAYER M5 ;
        RECT  21.84 34.476 21.864 34.56 ;
    END
  END i_d[331]
  PIN i_d[332]
    DIRECTION INPUT ;
    USE SIGNAL ;
    PORT
      LAYER M5 ;
        RECT  21.936 34.476 21.96 34.56 ;
    END
  END i_d[332]
  PIN i_d[333]
    DIRECTION INPUT ;
    USE SIGNAL ;
    PORT
      LAYER M5 ;
        RECT  22.032 34.476 22.056 34.56 ;
    END
  END i_d[333]
  PIN i_d[334]
    DIRECTION INPUT ;
    USE SIGNAL ;
    PORT
      LAYER M5 ;
        RECT  22.128 34.476 22.152 34.56 ;
    END
  END i_d[334]
  PIN i_d[335]
    DIRECTION INPUT ;
    USE SIGNAL ;
    PORT
      LAYER M5 ;
        RECT  22.224 34.476 22.248 34.56 ;
    END
  END i_d[335]
  PIN i_d[336]
    DIRECTION INPUT ;
    USE SIGNAL ;
    PORT
      LAYER M5 ;
        RECT  22.32 34.476 22.344 34.56 ;
    END
  END i_d[336]
  PIN i_d[337]
    DIRECTION INPUT ;
    USE SIGNAL ;
    PORT
      LAYER M5 ;
        RECT  22.416 34.476 22.44 34.56 ;
    END
  END i_d[337]
  PIN i_d[338]
    DIRECTION INPUT ;
    USE SIGNAL ;
    PORT
      LAYER M5 ;
        RECT  22.512 34.476 22.536 34.56 ;
    END
  END i_d[338]
  PIN i_d[339]
    DIRECTION INPUT ;
    USE SIGNAL ;
    PORT
      LAYER M5 ;
        RECT  22.608 34.476 22.632 34.56 ;
    END
  END i_d[339]
  PIN i_d[33]
    DIRECTION INPUT ;
    USE SIGNAL ;
    PORT
      LAYER M5 ;
        RECT  46.224 34.476 46.248 34.56 ;
    END
  END i_d[33]
  PIN i_d[340]
    DIRECTION INPUT ;
    USE SIGNAL ;
    PORT
      LAYER M5 ;
        RECT  22.704 34.476 22.728 34.56 ;
    END
  END i_d[340]
  PIN i_d[341]
    DIRECTION INPUT ;
    USE SIGNAL ;
    PORT
      LAYER M5 ;
        RECT  22.8 34.476 22.824 34.56 ;
    END
  END i_d[341]
  PIN i_d[342]
    DIRECTION INPUT ;
    USE SIGNAL ;
    PORT
      LAYER M5 ;
        RECT  22.896 34.476 22.92 34.56 ;
    END
  END i_d[342]
  PIN i_d[343]
    DIRECTION INPUT ;
    USE SIGNAL ;
    PORT
      LAYER M5 ;
        RECT  22.992 34.476 23.016 34.56 ;
    END
  END i_d[343]
  PIN i_d[344]
    DIRECTION INPUT ;
    USE SIGNAL ;
    PORT
      LAYER M5 ;
        RECT  23.088 34.476 23.112 34.56 ;
    END
  END i_d[344]
  PIN i_d[345]
    DIRECTION INPUT ;
    USE SIGNAL ;
    PORT
      LAYER M5 ;
        RECT  23.184 34.476 23.208 34.56 ;
    END
  END i_d[345]
  PIN i_d[346]
    DIRECTION INPUT ;
    USE SIGNAL ;
    PORT
      LAYER M5 ;
        RECT  23.28 34.476 23.304 34.56 ;
    END
  END i_d[346]
  PIN i_d[347]
    DIRECTION INPUT ;
    USE SIGNAL ;
    PORT
      LAYER M5 ;
        RECT  23.376 34.476 23.4 34.56 ;
    END
  END i_d[347]
  PIN i_d[348]
    DIRECTION INPUT ;
    USE SIGNAL ;
    PORT
      LAYER M5 ;
        RECT  23.472 34.476 23.496 34.56 ;
    END
  END i_d[348]
  PIN i_d[349]
    DIRECTION INPUT ;
    USE SIGNAL ;
    PORT
      LAYER M5 ;
        RECT  23.568 34.476 23.592 34.56 ;
    END
  END i_d[349]
  PIN i_d[34]
    DIRECTION INPUT ;
    USE SIGNAL ;
    PORT
      LAYER M5 ;
        RECT  46.32 34.476 46.344 34.56 ;
    END
  END i_d[34]
  PIN i_d[350]
    DIRECTION INPUT ;
    USE SIGNAL ;
    PORT
      LAYER M5 ;
        RECT  23.664 34.476 23.688 34.56 ;
    END
  END i_d[350]
  PIN i_d[351]
    DIRECTION INPUT ;
    USE SIGNAL ;
    PORT
      LAYER M5 ;
        RECT  23.76 34.476 23.784 34.56 ;
    END
  END i_d[351]
  PIN i_d[352]
    DIRECTION INPUT ;
    USE SIGNAL ;
    PORT
      LAYER M5 ;
        RECT  14.64 34.476 14.664 34.56 ;
    END
  END i_d[352]
  PIN i_d[353]
    DIRECTION INPUT ;
    USE SIGNAL ;
    PORT
      LAYER M5 ;
        RECT  14.736 34.476 14.76 34.56 ;
    END
  END i_d[353]
  PIN i_d[354]
    DIRECTION INPUT ;
    USE SIGNAL ;
    PORT
      LAYER M5 ;
        RECT  14.832 34.476 14.856 34.56 ;
    END
  END i_d[354]
  PIN i_d[355]
    DIRECTION INPUT ;
    USE SIGNAL ;
    PORT
      LAYER M5 ;
        RECT  14.928 34.476 14.952 34.56 ;
    END
  END i_d[355]
  PIN i_d[356]
    DIRECTION INPUT ;
    USE SIGNAL ;
    PORT
      LAYER M5 ;
        RECT  15.024 34.476 15.048 34.56 ;
    END
  END i_d[356]
  PIN i_d[357]
    DIRECTION INPUT ;
    USE SIGNAL ;
    PORT
      LAYER M5 ;
        RECT  15.12 34.476 15.144 34.56 ;
    END
  END i_d[357]
  PIN i_d[358]
    DIRECTION INPUT ;
    USE SIGNAL ;
    PORT
      LAYER M5 ;
        RECT  15.216 34.476 15.24 34.56 ;
    END
  END i_d[358]
  PIN i_d[359]
    DIRECTION INPUT ;
    USE SIGNAL ;
    PORT
      LAYER M5 ;
        RECT  15.312 34.476 15.336 34.56 ;
    END
  END i_d[359]
  PIN i_d[35]
    DIRECTION INPUT ;
    USE SIGNAL ;
    PORT
      LAYER M5 ;
        RECT  46.416 34.476 46.44 34.56 ;
    END
  END i_d[35]
  PIN i_d[360]
    DIRECTION INPUT ;
    USE SIGNAL ;
    PORT
      LAYER M5 ;
        RECT  15.408 34.476 15.432 34.56 ;
    END
  END i_d[360]
  PIN i_d[361]
    DIRECTION INPUT ;
    USE SIGNAL ;
    PORT
      LAYER M5 ;
        RECT  15.504 34.476 15.528 34.56 ;
    END
  END i_d[361]
  PIN i_d[362]
    DIRECTION INPUT ;
    USE SIGNAL ;
    PORT
      LAYER M5 ;
        RECT  15.6 34.476 15.624 34.56 ;
    END
  END i_d[362]
  PIN i_d[363]
    DIRECTION INPUT ;
    USE SIGNAL ;
    PORT
      LAYER M5 ;
        RECT  15.696 34.476 15.72 34.56 ;
    END
  END i_d[363]
  PIN i_d[364]
    DIRECTION INPUT ;
    USE SIGNAL ;
    PORT
      LAYER M5 ;
        RECT  15.792 34.476 15.816 34.56 ;
    END
  END i_d[364]
  PIN i_d[365]
    DIRECTION INPUT ;
    USE SIGNAL ;
    PORT
      LAYER M5 ;
        RECT  15.888 34.476 15.912 34.56 ;
    END
  END i_d[365]
  PIN i_d[366]
    DIRECTION INPUT ;
    USE SIGNAL ;
    PORT
      LAYER M5 ;
        RECT  15.984 34.476 16.008 34.56 ;
    END
  END i_d[366]
  PIN i_d[367]
    DIRECTION INPUT ;
    USE SIGNAL ;
    PORT
      LAYER M5 ;
        RECT  16.08 34.476 16.104 34.56 ;
    END
  END i_d[367]
  PIN i_d[368]
    DIRECTION INPUT ;
    USE SIGNAL ;
    PORT
      LAYER M5 ;
        RECT  16.176 34.476 16.2 34.56 ;
    END
  END i_d[368]
  PIN i_d[369]
    DIRECTION INPUT ;
    USE SIGNAL ;
    PORT
      LAYER M5 ;
        RECT  16.272 34.476 16.296 34.56 ;
    END
  END i_d[369]
  PIN i_d[36]
    DIRECTION INPUT ;
    USE SIGNAL ;
    PORT
      LAYER M5 ;
        RECT  46.512 34.476 46.536 34.56 ;
    END
  END i_d[36]
  PIN i_d[370]
    DIRECTION INPUT ;
    USE SIGNAL ;
    PORT
      LAYER M5 ;
        RECT  16.368 34.476 16.392 34.56 ;
    END
  END i_d[370]
  PIN i_d[371]
    DIRECTION INPUT ;
    USE SIGNAL ;
    PORT
      LAYER M5 ;
        RECT  16.464 34.476 16.488 34.56 ;
    END
  END i_d[371]
  PIN i_d[372]
    DIRECTION INPUT ;
    USE SIGNAL ;
    PORT
      LAYER M5 ;
        RECT  16.56 34.476 16.584 34.56 ;
    END
  END i_d[372]
  PIN i_d[373]
    DIRECTION INPUT ;
    USE SIGNAL ;
    PORT
      LAYER M5 ;
        RECT  16.656 34.476 16.68 34.56 ;
    END
  END i_d[373]
  PIN i_d[374]
    DIRECTION INPUT ;
    USE SIGNAL ;
    PORT
      LAYER M5 ;
        RECT  16.752 34.476 16.776 34.56 ;
    END
  END i_d[374]
  PIN i_d[375]
    DIRECTION INPUT ;
    USE SIGNAL ;
    PORT
      LAYER M5 ;
        RECT  16.848 34.476 16.872 34.56 ;
    END
  END i_d[375]
  PIN i_d[376]
    DIRECTION INPUT ;
    USE SIGNAL ;
    PORT
      LAYER M5 ;
        RECT  16.944 34.476 16.968 34.56 ;
    END
  END i_d[376]
  PIN i_d[377]
    DIRECTION INPUT ;
    USE SIGNAL ;
    PORT
      LAYER M5 ;
        RECT  17.04 34.476 17.064 34.56 ;
    END
  END i_d[377]
  PIN i_d[378]
    DIRECTION INPUT ;
    USE SIGNAL ;
    PORT
      LAYER M5 ;
        RECT  17.136 34.476 17.16 34.56 ;
    END
  END i_d[378]
  PIN i_d[379]
    DIRECTION INPUT ;
    USE SIGNAL ;
    PORT
      LAYER M5 ;
        RECT  17.232 34.476 17.256 34.56 ;
    END
  END i_d[379]
  PIN i_d[37]
    DIRECTION INPUT ;
    USE SIGNAL ;
    PORT
      LAYER M5 ;
        RECT  46.608 34.476 46.632 34.56 ;
    END
  END i_d[37]
  PIN i_d[380]
    DIRECTION INPUT ;
    USE SIGNAL ;
    PORT
      LAYER M5 ;
        RECT  17.328 34.476 17.352 34.56 ;
    END
  END i_d[380]
  PIN i_d[381]
    DIRECTION INPUT ;
    USE SIGNAL ;
    PORT
      LAYER M5 ;
        RECT  17.424 34.476 17.448 34.56 ;
    END
  END i_d[381]
  PIN i_d[382]
    DIRECTION INPUT ;
    USE SIGNAL ;
    PORT
      LAYER M5 ;
        RECT  17.52 34.476 17.544 34.56 ;
    END
  END i_d[382]
  PIN i_d[383]
    DIRECTION INPUT ;
    USE SIGNAL ;
    PORT
      LAYER M5 ;
        RECT  17.616 34.476 17.64 34.56 ;
    END
  END i_d[383]
  PIN i_d[384]
    DIRECTION INPUT ;
    USE SIGNAL ;
    PORT
      LAYER M5 ;
        RECT  59.184 34.476 59.208 34.56 ;
    END
  END i_d[384]
  PIN i_d[385]
    DIRECTION INPUT ;
    USE SIGNAL ;
    PORT
      LAYER M5 ;
        RECT  59.28 34.476 59.304 34.56 ;
    END
  END i_d[385]
  PIN i_d[386]
    DIRECTION INPUT ;
    USE SIGNAL ;
    PORT
      LAYER M5 ;
        RECT  59.376 34.476 59.4 34.56 ;
    END
  END i_d[386]
  PIN i_d[387]
    DIRECTION INPUT ;
    USE SIGNAL ;
    PORT
      LAYER M5 ;
        RECT  59.472 34.476 59.496 34.56 ;
    END
  END i_d[387]
  PIN i_d[388]
    DIRECTION INPUT ;
    USE SIGNAL ;
    PORT
      LAYER M5 ;
        RECT  59.568 34.476 59.592 34.56 ;
    END
  END i_d[388]
  PIN i_d[389]
    DIRECTION INPUT ;
    USE SIGNAL ;
    PORT
      LAYER M5 ;
        RECT  59.664 34.476 59.688 34.56 ;
    END
  END i_d[389]
  PIN i_d[38]
    DIRECTION INPUT ;
    USE SIGNAL ;
    PORT
      LAYER M5 ;
        RECT  46.704 34.476 46.728 34.56 ;
    END
  END i_d[38]
  PIN i_d[390]
    DIRECTION INPUT ;
    USE SIGNAL ;
    PORT
      LAYER M5 ;
        RECT  59.76 34.476 59.784 34.56 ;
    END
  END i_d[390]
  PIN i_d[391]
    DIRECTION INPUT ;
    USE SIGNAL ;
    PORT
      LAYER M5 ;
        RECT  59.856 34.476 59.88 34.56 ;
    END
  END i_d[391]
  PIN i_d[392]
    DIRECTION INPUT ;
    USE SIGNAL ;
    PORT
      LAYER M5 ;
        RECT  59.952 34.476 59.976 34.56 ;
    END
  END i_d[392]
  PIN i_d[393]
    DIRECTION INPUT ;
    USE SIGNAL ;
    PORT
      LAYER M5 ;
        RECT  60.048 34.476 60.072 34.56 ;
    END
  END i_d[393]
  PIN i_d[394]
    DIRECTION INPUT ;
    USE SIGNAL ;
    PORT
      LAYER M5 ;
        RECT  60.144 34.476 60.168 34.56 ;
    END
  END i_d[394]
  PIN i_d[395]
    DIRECTION INPUT ;
    USE SIGNAL ;
    PORT
      LAYER M5 ;
        RECT  60.24 34.476 60.264 34.56 ;
    END
  END i_d[395]
  PIN i_d[396]
    DIRECTION INPUT ;
    USE SIGNAL ;
    PORT
      LAYER M5 ;
        RECT  60.336 34.476 60.36 34.56 ;
    END
  END i_d[396]
  PIN i_d[397]
    DIRECTION INPUT ;
    USE SIGNAL ;
    PORT
      LAYER M5 ;
        RECT  60.432 34.476 60.456 34.56 ;
    END
  END i_d[397]
  PIN i_d[398]
    DIRECTION INPUT ;
    USE SIGNAL ;
    PORT
      LAYER M5 ;
        RECT  60.528 34.476 60.552 34.56 ;
    END
  END i_d[398]
  PIN i_d[399]
    DIRECTION INPUT ;
    USE SIGNAL ;
    PORT
      LAYER M5 ;
        RECT  60.624 34.476 60.648 34.56 ;
    END
  END i_d[399]
  PIN i_d[39]
    DIRECTION INPUT ;
    USE SIGNAL ;
    PORT
      LAYER M5 ;
        RECT  46.8 34.476 46.824 34.56 ;
    END
  END i_d[39]
  PIN i_d[3]
    DIRECTION INPUT ;
    USE SIGNAL ;
    PORT
      LAYER M5 ;
        RECT  40.272 34.476 40.296 34.56 ;
    END
  END i_d[3]
  PIN i_d[400]
    DIRECTION INPUT ;
    USE SIGNAL ;
    PORT
      LAYER M5 ;
        RECT  60.72 34.476 60.744 34.56 ;
    END
  END i_d[400]
  PIN i_d[401]
    DIRECTION INPUT ;
    USE SIGNAL ;
    PORT
      LAYER M5 ;
        RECT  60.816 34.476 60.84 34.56 ;
    END
  END i_d[401]
  PIN i_d[402]
    DIRECTION INPUT ;
    USE SIGNAL ;
    PORT
      LAYER M5 ;
        RECT  60.912 34.476 60.936 34.56 ;
    END
  END i_d[402]
  PIN i_d[403]
    DIRECTION INPUT ;
    USE SIGNAL ;
    PORT
      LAYER M5 ;
        RECT  61.008 34.476 61.032 34.56 ;
    END
  END i_d[403]
  PIN i_d[404]
    DIRECTION INPUT ;
    USE SIGNAL ;
    PORT
      LAYER M5 ;
        RECT  61.104 34.476 61.128 34.56 ;
    END
  END i_d[404]
  PIN i_d[405]
    DIRECTION INPUT ;
    USE SIGNAL ;
    PORT
      LAYER M5 ;
        RECT  61.2 34.476 61.224 34.56 ;
    END
  END i_d[405]
  PIN i_d[406]
    DIRECTION INPUT ;
    USE SIGNAL ;
    PORT
      LAYER M5 ;
        RECT  61.296 34.476 61.32 34.56 ;
    END
  END i_d[406]
  PIN i_d[407]
    DIRECTION INPUT ;
    USE SIGNAL ;
    PORT
      LAYER M5 ;
        RECT  61.392 34.476 61.416 34.56 ;
    END
  END i_d[407]
  PIN i_d[408]
    DIRECTION INPUT ;
    USE SIGNAL ;
    PORT
      LAYER M5 ;
        RECT  61.488 34.476 61.512 34.56 ;
    END
  END i_d[408]
  PIN i_d[409]
    DIRECTION INPUT ;
    USE SIGNAL ;
    PORT
      LAYER M5 ;
        RECT  61.584 34.476 61.608 34.56 ;
    END
  END i_d[409]
  PIN i_d[40]
    DIRECTION INPUT ;
    USE SIGNAL ;
    PORT
      LAYER M5 ;
        RECT  46.896 34.476 46.92 34.56 ;
    END
  END i_d[40]
  PIN i_d[410]
    DIRECTION INPUT ;
    USE SIGNAL ;
    PORT
      LAYER M5 ;
        RECT  61.68 34.476 61.704 34.56 ;
    END
  END i_d[410]
  PIN i_d[411]
    DIRECTION INPUT ;
    USE SIGNAL ;
    PORT
      LAYER M5 ;
        RECT  61.776 34.476 61.8 34.56 ;
    END
  END i_d[411]
  PIN i_d[412]
    DIRECTION INPUT ;
    USE SIGNAL ;
    PORT
      LAYER M5 ;
        RECT  61.872 34.476 61.896 34.56 ;
    END
  END i_d[412]
  PIN i_d[413]
    DIRECTION INPUT ;
    USE SIGNAL ;
    PORT
      LAYER M5 ;
        RECT  61.968 34.476 61.992 34.56 ;
    END
  END i_d[413]
  PIN i_d[414]
    DIRECTION INPUT ;
    USE SIGNAL ;
    PORT
      LAYER M5 ;
        RECT  62.064 34.476 62.088 34.56 ;
    END
  END i_d[414]
  PIN i_d[415]
    DIRECTION INPUT ;
    USE SIGNAL ;
    PORT
      LAYER M5 ;
        RECT  62.16 34.476 62.184 34.56 ;
    END
  END i_d[415]
  PIN i_d[416]
    DIRECTION INPUT ;
    USE SIGNAL ;
    PORT
      LAYER M5 ;
        RECT  56.112 34.476 56.136 34.56 ;
    END
  END i_d[416]
  PIN i_d[417]
    DIRECTION INPUT ;
    USE SIGNAL ;
    PORT
      LAYER M5 ;
        RECT  56.208 34.476 56.232 34.56 ;
    END
  END i_d[417]
  PIN i_d[418]
    DIRECTION INPUT ;
    USE SIGNAL ;
    PORT
      LAYER M5 ;
        RECT  56.304 34.476 56.328 34.56 ;
    END
  END i_d[418]
  PIN i_d[419]
    DIRECTION INPUT ;
    USE SIGNAL ;
    PORT
      LAYER M5 ;
        RECT  56.4 34.476 56.424 34.56 ;
    END
  END i_d[419]
  PIN i_d[41]
    DIRECTION INPUT ;
    USE SIGNAL ;
    PORT
      LAYER M5 ;
        RECT  46.992 34.476 47.016 34.56 ;
    END
  END i_d[41]
  PIN i_d[420]
    DIRECTION INPUT ;
    USE SIGNAL ;
    PORT
      LAYER M5 ;
        RECT  56.496 34.476 56.52 34.56 ;
    END
  END i_d[420]
  PIN i_d[421]
    DIRECTION INPUT ;
    USE SIGNAL ;
    PORT
      LAYER M5 ;
        RECT  56.592 34.476 56.616 34.56 ;
    END
  END i_d[421]
  PIN i_d[422]
    DIRECTION INPUT ;
    USE SIGNAL ;
    PORT
      LAYER M5 ;
        RECT  56.688 34.476 56.712 34.56 ;
    END
  END i_d[422]
  PIN i_d[423]
    DIRECTION INPUT ;
    USE SIGNAL ;
    PORT
      LAYER M5 ;
        RECT  56.784 34.476 56.808 34.56 ;
    END
  END i_d[423]
  PIN i_d[424]
    DIRECTION INPUT ;
    USE SIGNAL ;
    PORT
      LAYER M5 ;
        RECT  56.88 34.476 56.904 34.56 ;
    END
  END i_d[424]
  PIN i_d[425]
    DIRECTION INPUT ;
    USE SIGNAL ;
    PORT
      LAYER M5 ;
        RECT  56.976 34.476 57 34.56 ;
    END
  END i_d[425]
  PIN i_d[426]
    DIRECTION INPUT ;
    USE SIGNAL ;
    PORT
      LAYER M5 ;
        RECT  57.072 34.476 57.096 34.56 ;
    END
  END i_d[426]
  PIN i_d[427]
    DIRECTION INPUT ;
    USE SIGNAL ;
    PORT
      LAYER M5 ;
        RECT  57.168 34.476 57.192 34.56 ;
    END
  END i_d[427]
  PIN i_d[428]
    DIRECTION INPUT ;
    USE SIGNAL ;
    PORT
      LAYER M5 ;
        RECT  57.264 34.476 57.288 34.56 ;
    END
  END i_d[428]
  PIN i_d[429]
    DIRECTION INPUT ;
    USE SIGNAL ;
    PORT
      LAYER M5 ;
        RECT  57.36 34.476 57.384 34.56 ;
    END
  END i_d[429]
  PIN i_d[42]
    DIRECTION INPUT ;
    USE SIGNAL ;
    PORT
      LAYER M5 ;
        RECT  47.088 34.476 47.112 34.56 ;
    END
  END i_d[42]
  PIN i_d[430]
    DIRECTION INPUT ;
    USE SIGNAL ;
    PORT
      LAYER M5 ;
        RECT  57.456 34.476 57.48 34.56 ;
    END
  END i_d[430]
  PIN i_d[431]
    DIRECTION INPUT ;
    USE SIGNAL ;
    PORT
      LAYER M5 ;
        RECT  57.552 34.476 57.576 34.56 ;
    END
  END i_d[431]
  PIN i_d[432]
    DIRECTION INPUT ;
    USE SIGNAL ;
    PORT
      LAYER M5 ;
        RECT  57.648 34.476 57.672 34.56 ;
    END
  END i_d[432]
  PIN i_d[433]
    DIRECTION INPUT ;
    USE SIGNAL ;
    PORT
      LAYER M5 ;
        RECT  57.744 34.476 57.768 34.56 ;
    END
  END i_d[433]
  PIN i_d[434]
    DIRECTION INPUT ;
    USE SIGNAL ;
    PORT
      LAYER M5 ;
        RECT  57.84 34.476 57.864 34.56 ;
    END
  END i_d[434]
  PIN i_d[435]
    DIRECTION INPUT ;
    USE SIGNAL ;
    PORT
      LAYER M5 ;
        RECT  57.936 34.476 57.96 34.56 ;
    END
  END i_d[435]
  PIN i_d[436]
    DIRECTION INPUT ;
    USE SIGNAL ;
    PORT
      LAYER M5 ;
        RECT  58.032 34.476 58.056 34.56 ;
    END
  END i_d[436]
  PIN i_d[437]
    DIRECTION INPUT ;
    USE SIGNAL ;
    PORT
      LAYER M5 ;
        RECT  58.128 34.476 58.152 34.56 ;
    END
  END i_d[437]
  PIN i_d[438]
    DIRECTION INPUT ;
    USE SIGNAL ;
    PORT
      LAYER M5 ;
        RECT  58.224 34.476 58.248 34.56 ;
    END
  END i_d[438]
  PIN i_d[439]
    DIRECTION INPUT ;
    USE SIGNAL ;
    PORT
      LAYER M5 ;
        RECT  58.32 34.476 58.344 34.56 ;
    END
  END i_d[439]
  PIN i_d[43]
    DIRECTION INPUT ;
    USE SIGNAL ;
    PORT
      LAYER M5 ;
        RECT  47.184 34.476 47.208 34.56 ;
    END
  END i_d[43]
  PIN i_d[440]
    DIRECTION INPUT ;
    USE SIGNAL ;
    PORT
      LAYER M5 ;
        RECT  58.416 34.476 58.44 34.56 ;
    END
  END i_d[440]
  PIN i_d[441]
    DIRECTION INPUT ;
    USE SIGNAL ;
    PORT
      LAYER M5 ;
        RECT  58.512 34.476 58.536 34.56 ;
    END
  END i_d[441]
  PIN i_d[442]
    DIRECTION INPUT ;
    USE SIGNAL ;
    PORT
      LAYER M5 ;
        RECT  58.608 34.476 58.632 34.56 ;
    END
  END i_d[442]
  PIN i_d[443]
    DIRECTION INPUT ;
    USE SIGNAL ;
    PORT
      LAYER M5 ;
        RECT  58.704 34.476 58.728 34.56 ;
    END
  END i_d[443]
  PIN i_d[444]
    DIRECTION INPUT ;
    USE SIGNAL ;
    PORT
      LAYER M5 ;
        RECT  58.8 34.476 58.824 34.56 ;
    END
  END i_d[444]
  PIN i_d[445]
    DIRECTION INPUT ;
    USE SIGNAL ;
    PORT
      LAYER M5 ;
        RECT  58.896 34.476 58.92 34.56 ;
    END
  END i_d[445]
  PIN i_d[446]
    DIRECTION INPUT ;
    USE SIGNAL ;
    PORT
      LAYER M5 ;
        RECT  58.992 34.476 59.016 34.56 ;
    END
  END i_d[446]
  PIN i_d[447]
    DIRECTION INPUT ;
    USE SIGNAL ;
    PORT
      LAYER M5 ;
        RECT  59.088 34.476 59.112 34.56 ;
    END
  END i_d[447]
  PIN i_d[448]
    DIRECTION INPUT ;
    USE SIGNAL ;
    PORT
      LAYER M5 ;
        RECT  53.04 34.476 53.064 34.56 ;
    END
  END i_d[448]
  PIN i_d[449]
    DIRECTION INPUT ;
    USE SIGNAL ;
    PORT
      LAYER M5 ;
        RECT  53.136 34.476 53.16 34.56 ;
    END
  END i_d[449]
  PIN i_d[44]
    DIRECTION INPUT ;
    USE SIGNAL ;
    PORT
      LAYER M5 ;
        RECT  47.28 34.476 47.304 34.56 ;
    END
  END i_d[44]
  PIN i_d[450]
    DIRECTION INPUT ;
    USE SIGNAL ;
    PORT
      LAYER M5 ;
        RECT  53.232 34.476 53.256 34.56 ;
    END
  END i_d[450]
  PIN i_d[451]
    DIRECTION INPUT ;
    USE SIGNAL ;
    PORT
      LAYER M5 ;
        RECT  53.328 34.476 53.352 34.56 ;
    END
  END i_d[451]
  PIN i_d[452]
    DIRECTION INPUT ;
    USE SIGNAL ;
    PORT
      LAYER M5 ;
        RECT  53.424 34.476 53.448 34.56 ;
    END
  END i_d[452]
  PIN i_d[453]
    DIRECTION INPUT ;
    USE SIGNAL ;
    PORT
      LAYER M5 ;
        RECT  53.52 34.476 53.544 34.56 ;
    END
  END i_d[453]
  PIN i_d[454]
    DIRECTION INPUT ;
    USE SIGNAL ;
    PORT
      LAYER M5 ;
        RECT  53.616 34.476 53.64 34.56 ;
    END
  END i_d[454]
  PIN i_d[455]
    DIRECTION INPUT ;
    USE SIGNAL ;
    PORT
      LAYER M5 ;
        RECT  53.712 34.476 53.736 34.56 ;
    END
  END i_d[455]
  PIN i_d[456]
    DIRECTION INPUT ;
    USE SIGNAL ;
    PORT
      LAYER M5 ;
        RECT  53.808 34.476 53.832 34.56 ;
    END
  END i_d[456]
  PIN i_d[457]
    DIRECTION INPUT ;
    USE SIGNAL ;
    PORT
      LAYER M5 ;
        RECT  53.904 34.476 53.928 34.56 ;
    END
  END i_d[457]
  PIN i_d[458]
    DIRECTION INPUT ;
    USE SIGNAL ;
    PORT
      LAYER M5 ;
        RECT  54 34.476 54.024 34.56 ;
    END
  END i_d[458]
  PIN i_d[459]
    DIRECTION INPUT ;
    USE SIGNAL ;
    PORT
      LAYER M5 ;
        RECT  54.096 34.476 54.12 34.56 ;
    END
  END i_d[459]
  PIN i_d[45]
    DIRECTION INPUT ;
    USE SIGNAL ;
    PORT
      LAYER M5 ;
        RECT  47.376 34.476 47.4 34.56 ;
    END
  END i_d[45]
  PIN i_d[460]
    DIRECTION INPUT ;
    USE SIGNAL ;
    PORT
      LAYER M5 ;
        RECT  54.192 34.476 54.216 34.56 ;
    END
  END i_d[460]
  PIN i_d[461]
    DIRECTION INPUT ;
    USE SIGNAL ;
    PORT
      LAYER M5 ;
        RECT  54.288 34.476 54.312 34.56 ;
    END
  END i_d[461]
  PIN i_d[462]
    DIRECTION INPUT ;
    USE SIGNAL ;
    PORT
      LAYER M5 ;
        RECT  54.384 34.476 54.408 34.56 ;
    END
  END i_d[462]
  PIN i_d[463]
    DIRECTION INPUT ;
    USE SIGNAL ;
    PORT
      LAYER M5 ;
        RECT  54.48 34.476 54.504 34.56 ;
    END
  END i_d[463]
  PIN i_d[464]
    DIRECTION INPUT ;
    USE SIGNAL ;
    PORT
      LAYER M5 ;
        RECT  54.576 34.476 54.6 34.56 ;
    END
  END i_d[464]
  PIN i_d[465]
    DIRECTION INPUT ;
    USE SIGNAL ;
    PORT
      LAYER M5 ;
        RECT  54.672 34.476 54.696 34.56 ;
    END
  END i_d[465]
  PIN i_d[466]
    DIRECTION INPUT ;
    USE SIGNAL ;
    PORT
      LAYER M5 ;
        RECT  54.768 34.476 54.792 34.56 ;
    END
  END i_d[466]
  PIN i_d[467]
    DIRECTION INPUT ;
    USE SIGNAL ;
    PORT
      LAYER M5 ;
        RECT  54.864 34.476 54.888 34.56 ;
    END
  END i_d[467]
  PIN i_d[468]
    DIRECTION INPUT ;
    USE SIGNAL ;
    PORT
      LAYER M5 ;
        RECT  54.96 34.476 54.984 34.56 ;
    END
  END i_d[468]
  PIN i_d[469]
    DIRECTION INPUT ;
    USE SIGNAL ;
    PORT
      LAYER M5 ;
        RECT  55.056 34.476 55.08 34.56 ;
    END
  END i_d[469]
  PIN i_d[46]
    DIRECTION INPUT ;
    USE SIGNAL ;
    PORT
      LAYER M5 ;
        RECT  47.472 34.476 47.496 34.56 ;
    END
  END i_d[46]
  PIN i_d[470]
    DIRECTION INPUT ;
    USE SIGNAL ;
    PORT
      LAYER M5 ;
        RECT  55.152 34.476 55.176 34.56 ;
    END
  END i_d[470]
  PIN i_d[471]
    DIRECTION INPUT ;
    USE SIGNAL ;
    PORT
      LAYER M5 ;
        RECT  55.248 34.476 55.272 34.56 ;
    END
  END i_d[471]
  PIN i_d[472]
    DIRECTION INPUT ;
    USE SIGNAL ;
    PORT
      LAYER M5 ;
        RECT  55.344 34.476 55.368 34.56 ;
    END
  END i_d[472]
  PIN i_d[473]
    DIRECTION INPUT ;
    USE SIGNAL ;
    PORT
      LAYER M5 ;
        RECT  55.44 34.476 55.464 34.56 ;
    END
  END i_d[473]
  PIN i_d[474]
    DIRECTION INPUT ;
    USE SIGNAL ;
    PORT
      LAYER M5 ;
        RECT  55.536 34.476 55.56 34.56 ;
    END
  END i_d[474]
  PIN i_d[475]
    DIRECTION INPUT ;
    USE SIGNAL ;
    PORT
      LAYER M5 ;
        RECT  55.632 34.476 55.656 34.56 ;
    END
  END i_d[475]
  PIN i_d[476]
    DIRECTION INPUT ;
    USE SIGNAL ;
    PORT
      LAYER M5 ;
        RECT  55.728 34.476 55.752 34.56 ;
    END
  END i_d[476]
  PIN i_d[477]
    DIRECTION INPUT ;
    USE SIGNAL ;
    PORT
      LAYER M5 ;
        RECT  55.824 34.476 55.848 34.56 ;
    END
  END i_d[477]
  PIN i_d[478]
    DIRECTION INPUT ;
    USE SIGNAL ;
    PORT
      LAYER M5 ;
        RECT  55.92 34.476 55.944 34.56 ;
    END
  END i_d[478]
  PIN i_d[479]
    DIRECTION INPUT ;
    USE SIGNAL ;
    PORT
      LAYER M5 ;
        RECT  56.016 34.476 56.04 34.56 ;
    END
  END i_d[479]
  PIN i_d[47]
    DIRECTION INPUT ;
    USE SIGNAL ;
    PORT
      LAYER M5 ;
        RECT  47.568 34.476 47.592 34.56 ;
    END
  END i_d[47]
  PIN i_d[480]
    DIRECTION INPUT ;
    USE SIGNAL ;
    PORT
      LAYER M5 ;
        RECT  49.968 34.476 49.992 34.56 ;
    END
  END i_d[480]
  PIN i_d[481]
    DIRECTION INPUT ;
    USE SIGNAL ;
    PORT
      LAYER M5 ;
        RECT  50.064 34.476 50.088 34.56 ;
    END
  END i_d[481]
  PIN i_d[482]
    DIRECTION INPUT ;
    USE SIGNAL ;
    PORT
      LAYER M5 ;
        RECT  50.16 34.476 50.184 34.56 ;
    END
  END i_d[482]
  PIN i_d[483]
    DIRECTION INPUT ;
    USE SIGNAL ;
    PORT
      LAYER M5 ;
        RECT  50.256 34.476 50.28 34.56 ;
    END
  END i_d[483]
  PIN i_d[484]
    DIRECTION INPUT ;
    USE SIGNAL ;
    PORT
      LAYER M5 ;
        RECT  50.352 34.476 50.376 34.56 ;
    END
  END i_d[484]
  PIN i_d[485]
    DIRECTION INPUT ;
    USE SIGNAL ;
    PORT
      LAYER M5 ;
        RECT  50.448 34.476 50.472 34.56 ;
    END
  END i_d[485]
  PIN i_d[486]
    DIRECTION INPUT ;
    USE SIGNAL ;
    PORT
      LAYER M5 ;
        RECT  50.544 34.476 50.568 34.56 ;
    END
  END i_d[486]
  PIN i_d[487]
    DIRECTION INPUT ;
    USE SIGNAL ;
    PORT
      LAYER M5 ;
        RECT  50.64 34.476 50.664 34.56 ;
    END
  END i_d[487]
  PIN i_d[488]
    DIRECTION INPUT ;
    USE SIGNAL ;
    PORT
      LAYER M5 ;
        RECT  50.736 34.476 50.76 34.56 ;
    END
  END i_d[488]
  PIN i_d[489]
    DIRECTION INPUT ;
    USE SIGNAL ;
    PORT
      LAYER M5 ;
        RECT  50.832 34.476 50.856 34.56 ;
    END
  END i_d[489]
  PIN i_d[48]
    DIRECTION INPUT ;
    USE SIGNAL ;
    PORT
      LAYER M5 ;
        RECT  47.664 34.476 47.688 34.56 ;
    END
  END i_d[48]
  PIN i_d[490]
    DIRECTION INPUT ;
    USE SIGNAL ;
    PORT
      LAYER M5 ;
        RECT  50.928 34.476 50.952 34.56 ;
    END
  END i_d[490]
  PIN i_d[491]
    DIRECTION INPUT ;
    USE SIGNAL ;
    PORT
      LAYER M5 ;
        RECT  51.024 34.476 51.048 34.56 ;
    END
  END i_d[491]
  PIN i_d[492]
    DIRECTION INPUT ;
    USE SIGNAL ;
    PORT
      LAYER M5 ;
        RECT  51.12 34.476 51.144 34.56 ;
    END
  END i_d[492]
  PIN i_d[493]
    DIRECTION INPUT ;
    USE SIGNAL ;
    PORT
      LAYER M5 ;
        RECT  51.216 34.476 51.24 34.56 ;
    END
  END i_d[493]
  PIN i_d[494]
    DIRECTION INPUT ;
    USE SIGNAL ;
    PORT
      LAYER M5 ;
        RECT  51.312 34.476 51.336 34.56 ;
    END
  END i_d[494]
  PIN i_d[495]
    DIRECTION INPUT ;
    USE SIGNAL ;
    PORT
      LAYER M5 ;
        RECT  51.408 34.476 51.432 34.56 ;
    END
  END i_d[495]
  PIN i_d[496]
    DIRECTION INPUT ;
    USE SIGNAL ;
    PORT
      LAYER M5 ;
        RECT  51.504 34.476 51.528 34.56 ;
    END
  END i_d[496]
  PIN i_d[497]
    DIRECTION INPUT ;
    USE SIGNAL ;
    PORT
      LAYER M5 ;
        RECT  51.6 34.476 51.624 34.56 ;
    END
  END i_d[497]
  PIN i_d[498]
    DIRECTION INPUT ;
    USE SIGNAL ;
    PORT
      LAYER M5 ;
        RECT  51.696 34.476 51.72 34.56 ;
    END
  END i_d[498]
  PIN i_d[499]
    DIRECTION INPUT ;
    USE SIGNAL ;
    PORT
      LAYER M5 ;
        RECT  51.792 34.476 51.816 34.56 ;
    END
  END i_d[499]
  PIN i_d[49]
    DIRECTION INPUT ;
    USE SIGNAL ;
    PORT
      LAYER M5 ;
        RECT  47.76 34.476 47.784 34.56 ;
    END
  END i_d[49]
  PIN i_d[4]
    DIRECTION INPUT ;
    USE SIGNAL ;
    PORT
      LAYER M5 ;
        RECT  40.368 34.476 40.392 34.56 ;
    END
  END i_d[4]
  PIN i_d[500]
    DIRECTION INPUT ;
    USE SIGNAL ;
    PORT
      LAYER M5 ;
        RECT  51.888 34.476 51.912 34.56 ;
    END
  END i_d[500]
  PIN i_d[501]
    DIRECTION INPUT ;
    USE SIGNAL ;
    PORT
      LAYER M5 ;
        RECT  51.984 34.476 52.008 34.56 ;
    END
  END i_d[501]
  PIN i_d[502]
    DIRECTION INPUT ;
    USE SIGNAL ;
    PORT
      LAYER M5 ;
        RECT  52.08 34.476 52.104 34.56 ;
    END
  END i_d[502]
  PIN i_d[503]
    DIRECTION INPUT ;
    USE SIGNAL ;
    PORT
      LAYER M5 ;
        RECT  52.176 34.476 52.2 34.56 ;
    END
  END i_d[503]
  PIN i_d[504]
    DIRECTION INPUT ;
    USE SIGNAL ;
    PORT
      LAYER M5 ;
        RECT  52.272 34.476 52.296 34.56 ;
    END
  END i_d[504]
  PIN i_d[505]
    DIRECTION INPUT ;
    USE SIGNAL ;
    PORT
      LAYER M5 ;
        RECT  52.368 34.476 52.392 34.56 ;
    END
  END i_d[505]
  PIN i_d[506]
    DIRECTION INPUT ;
    USE SIGNAL ;
    PORT
      LAYER M5 ;
        RECT  52.464 34.476 52.488 34.56 ;
    END
  END i_d[506]
  PIN i_d[507]
    DIRECTION INPUT ;
    USE SIGNAL ;
    PORT
      LAYER M5 ;
        RECT  52.56 34.476 52.584 34.56 ;
    END
  END i_d[507]
  PIN i_d[508]
    DIRECTION INPUT ;
    USE SIGNAL ;
    PORT
      LAYER M5 ;
        RECT  52.656 34.476 52.68 34.56 ;
    END
  END i_d[508]
  PIN i_d[509]
    DIRECTION INPUT ;
    USE SIGNAL ;
    PORT
      LAYER M5 ;
        RECT  52.752 34.476 52.776 34.56 ;
    END
  END i_d[509]
  PIN i_d[50]
    DIRECTION INPUT ;
    USE SIGNAL ;
    PORT
      LAYER M5 ;
        RECT  47.856 34.476 47.88 34.56 ;
    END
  END i_d[50]
  PIN i_d[510]
    DIRECTION INPUT ;
    USE SIGNAL ;
    PORT
      LAYER M5 ;
        RECT  52.848 34.476 52.872 34.56 ;
    END
  END i_d[510]
  PIN i_d[511]
    DIRECTION INPUT ;
    USE SIGNAL ;
    PORT
      LAYER M5 ;
        RECT  52.944 34.476 52.968 34.56 ;
    END
  END i_d[511]
  PIN i_d[51]
    DIRECTION INPUT ;
    USE SIGNAL ;
    PORT
      LAYER M5 ;
        RECT  47.952 34.476 47.976 34.56 ;
    END
  END i_d[51]
  PIN i_d[52]
    DIRECTION INPUT ;
    USE SIGNAL ;
    PORT
      LAYER M5 ;
        RECT  48.048 34.476 48.072 34.56 ;
    END
  END i_d[52]
  PIN i_d[53]
    DIRECTION INPUT ;
    USE SIGNAL ;
    PORT
      LAYER M5 ;
        RECT  48.144 34.476 48.168 34.56 ;
    END
  END i_d[53]
  PIN i_d[54]
    DIRECTION INPUT ;
    USE SIGNAL ;
    PORT
      LAYER M5 ;
        RECT  48.24 34.476 48.264 34.56 ;
    END
  END i_d[54]
  PIN i_d[55]
    DIRECTION INPUT ;
    USE SIGNAL ;
    PORT
      LAYER M5 ;
        RECT  48.336 34.476 48.36 34.56 ;
    END
  END i_d[55]
  PIN i_d[56]
    DIRECTION INPUT ;
    USE SIGNAL ;
    PORT
      LAYER M5 ;
        RECT  48.432 34.476 48.456 34.56 ;
    END
  END i_d[56]
  PIN i_d[57]
    DIRECTION INPUT ;
    USE SIGNAL ;
    PORT
      LAYER M5 ;
        RECT  48.528 34.476 48.552 34.56 ;
    END
  END i_d[57]
  PIN i_d[58]
    DIRECTION INPUT ;
    USE SIGNAL ;
    PORT
      LAYER M5 ;
        RECT  48.624 34.476 48.648 34.56 ;
    END
  END i_d[58]
  PIN i_d[59]
    DIRECTION INPUT ;
    USE SIGNAL ;
    PORT
      LAYER M5 ;
        RECT  48.72 34.476 48.744 34.56 ;
    END
  END i_d[59]
  PIN i_d[5]
    DIRECTION INPUT ;
    USE SIGNAL ;
    PORT
      LAYER M5 ;
        RECT  40.464 34.476 40.488 34.56 ;
    END
  END i_d[5]
  PIN i_d[60]
    DIRECTION INPUT ;
    USE SIGNAL ;
    PORT
      LAYER M5 ;
        RECT  48.816 34.476 48.84 34.56 ;
    END
  END i_d[60]
  PIN i_d[61]
    DIRECTION INPUT ;
    USE SIGNAL ;
    PORT
      LAYER M5 ;
        RECT  48.912 34.476 48.936 34.56 ;
    END
  END i_d[61]
  PIN i_d[62]
    DIRECTION INPUT ;
    USE SIGNAL ;
    PORT
      LAYER M5 ;
        RECT  49.008 34.476 49.032 34.56 ;
    END
  END i_d[62]
  PIN i_d[63]
    DIRECTION INPUT ;
    USE SIGNAL ;
    PORT
      LAYER M5 ;
        RECT  49.104 34.476 49.128 34.56 ;
    END
  END i_d[63]
  PIN i_d[64]
    DIRECTION INPUT ;
    USE SIGNAL ;
    PORT
      LAYER M5 ;
        RECT  33.84 34.476 33.864 34.56 ;
    END
  END i_d[64]
  PIN i_d[65]
    DIRECTION INPUT ;
    USE SIGNAL ;
    PORT
      LAYER M5 ;
        RECT  33.936 34.476 33.96 34.56 ;
    END
  END i_d[65]
  PIN i_d[66]
    DIRECTION INPUT ;
    USE SIGNAL ;
    PORT
      LAYER M5 ;
        RECT  34.032 34.476 34.056 34.56 ;
    END
  END i_d[66]
  PIN i_d[67]
    DIRECTION INPUT ;
    USE SIGNAL ;
    PORT
      LAYER M5 ;
        RECT  34.128 34.476 34.152 34.56 ;
    END
  END i_d[67]
  PIN i_d[68]
    DIRECTION INPUT ;
    USE SIGNAL ;
    PORT
      LAYER M5 ;
        RECT  34.224 34.476 34.248 34.56 ;
    END
  END i_d[68]
  PIN i_d[69]
    DIRECTION INPUT ;
    USE SIGNAL ;
    PORT
      LAYER M5 ;
        RECT  34.32 34.476 34.344 34.56 ;
    END
  END i_d[69]
  PIN i_d[6]
    DIRECTION INPUT ;
    USE SIGNAL ;
    PORT
      LAYER M5 ;
        RECT  40.56 34.476 40.584 34.56 ;
    END
  END i_d[6]
  PIN i_d[70]
    DIRECTION INPUT ;
    USE SIGNAL ;
    PORT
      LAYER M5 ;
        RECT  34.416 34.476 34.44 34.56 ;
    END
  END i_d[70]
  PIN i_d[71]
    DIRECTION INPUT ;
    USE SIGNAL ;
    PORT
      LAYER M5 ;
        RECT  34.512 34.476 34.536 34.56 ;
    END
  END i_d[71]
  PIN i_d[72]
    DIRECTION INPUT ;
    USE SIGNAL ;
    PORT
      LAYER M5 ;
        RECT  34.608 34.476 34.632 34.56 ;
    END
  END i_d[72]
  PIN i_d[73]
    DIRECTION INPUT ;
    USE SIGNAL ;
    PORT
      LAYER M5 ;
        RECT  34.704 34.476 34.728 34.56 ;
    END
  END i_d[73]
  PIN i_d[74]
    DIRECTION INPUT ;
    USE SIGNAL ;
    PORT
      LAYER M5 ;
        RECT  34.8 34.476 34.824 34.56 ;
    END
  END i_d[74]
  PIN i_d[75]
    DIRECTION INPUT ;
    USE SIGNAL ;
    PORT
      LAYER M5 ;
        RECT  34.896 34.476 34.92 34.56 ;
    END
  END i_d[75]
  PIN i_d[76]
    DIRECTION INPUT ;
    USE SIGNAL ;
    PORT
      LAYER M5 ;
        RECT  34.992 34.476 35.016 34.56 ;
    END
  END i_d[76]
  PIN i_d[77]
    DIRECTION INPUT ;
    USE SIGNAL ;
    PORT
      LAYER M5 ;
        RECT  35.088 34.476 35.112 34.56 ;
    END
  END i_d[77]
  PIN i_d[78]
    DIRECTION INPUT ;
    USE SIGNAL ;
    PORT
      LAYER M5 ;
        RECT  35.184 34.476 35.208 34.56 ;
    END
  END i_d[78]
  PIN i_d[79]
    DIRECTION INPUT ;
    USE SIGNAL ;
    PORT
      LAYER M5 ;
        RECT  35.28 34.476 35.304 34.56 ;
    END
  END i_d[79]
  PIN i_d[7]
    DIRECTION INPUT ;
    USE SIGNAL ;
    PORT
      LAYER M5 ;
        RECT  40.656 34.476 40.68 34.56 ;
    END
  END i_d[7]
  PIN i_d[80]
    DIRECTION INPUT ;
    USE SIGNAL ;
    PORT
      LAYER M5 ;
        RECT  35.376 34.476 35.4 34.56 ;
    END
  END i_d[80]
  PIN i_d[81]
    DIRECTION INPUT ;
    USE SIGNAL ;
    PORT
      LAYER M5 ;
        RECT  35.472 34.476 35.496 34.56 ;
    END
  END i_d[81]
  PIN i_d[82]
    DIRECTION INPUT ;
    USE SIGNAL ;
    PORT
      LAYER M5 ;
        RECT  35.568 34.476 35.592 34.56 ;
    END
  END i_d[82]
  PIN i_d[83]
    DIRECTION INPUT ;
    USE SIGNAL ;
    PORT
      LAYER M5 ;
        RECT  35.664 34.476 35.688 34.56 ;
    END
  END i_d[83]
  PIN i_d[84]
    DIRECTION INPUT ;
    USE SIGNAL ;
    PORT
      LAYER M5 ;
        RECT  35.76 34.476 35.784 34.56 ;
    END
  END i_d[84]
  PIN i_d[85]
    DIRECTION INPUT ;
    USE SIGNAL ;
    PORT
      LAYER M5 ;
        RECT  35.856 34.476 35.88 34.56 ;
    END
  END i_d[85]
  PIN i_d[86]
    DIRECTION INPUT ;
    USE SIGNAL ;
    PORT
      LAYER M5 ;
        RECT  35.952 34.476 35.976 34.56 ;
    END
  END i_d[86]
  PIN i_d[87]
    DIRECTION INPUT ;
    USE SIGNAL ;
    PORT
      LAYER M5 ;
        RECT  36.048 34.476 36.072 34.56 ;
    END
  END i_d[87]
  PIN i_d[88]
    DIRECTION INPUT ;
    USE SIGNAL ;
    PORT
      LAYER M5 ;
        RECT  36.144 34.476 36.168 34.56 ;
    END
  END i_d[88]
  PIN i_d[89]
    DIRECTION INPUT ;
    USE SIGNAL ;
    PORT
      LAYER M5 ;
        RECT  36.24 34.476 36.264 34.56 ;
    END
  END i_d[89]
  PIN i_d[8]
    DIRECTION INPUT ;
    USE SIGNAL ;
    PORT
      LAYER M5 ;
        RECT  40.752 34.476 40.776 34.56 ;
    END
  END i_d[8]
  PIN i_d[90]
    DIRECTION INPUT ;
    USE SIGNAL ;
    PORT
      LAYER M5 ;
        RECT  36.336 34.476 36.36 34.56 ;
    END
  END i_d[90]
  PIN i_d[91]
    DIRECTION INPUT ;
    USE SIGNAL ;
    PORT
      LAYER M5 ;
        RECT  36.432 34.476 36.456 34.56 ;
    END
  END i_d[91]
  PIN i_d[92]
    DIRECTION INPUT ;
    USE SIGNAL ;
    PORT
      LAYER M5 ;
        RECT  36.528 34.476 36.552 34.56 ;
    END
  END i_d[92]
  PIN i_d[93]
    DIRECTION INPUT ;
    USE SIGNAL ;
    PORT
      LAYER M5 ;
        RECT  36.624 34.476 36.648 34.56 ;
    END
  END i_d[93]
  PIN i_d[94]
    DIRECTION INPUT ;
    USE SIGNAL ;
    PORT
      LAYER M5 ;
        RECT  36.72 34.476 36.744 34.56 ;
    END
  END i_d[94]
  PIN i_d[95]
    DIRECTION INPUT ;
    USE SIGNAL ;
    PORT
      LAYER M5 ;
        RECT  36.816 34.476 36.84 34.56 ;
    END
  END i_d[95]
  PIN i_d[96]
    DIRECTION INPUT ;
    USE SIGNAL ;
    PORT
      LAYER M5 ;
        RECT  36.912 34.476 36.936 34.56 ;
    END
  END i_d[96]
  PIN i_d[97]
    DIRECTION INPUT ;
    USE SIGNAL ;
    PORT
      LAYER M5 ;
        RECT  37.008 34.476 37.032 34.56 ;
    END
  END i_d[97]
  PIN i_d[98]
    DIRECTION INPUT ;
    USE SIGNAL ;
    PORT
      LAYER M5 ;
        RECT  37.104 34.476 37.128 34.56 ;
    END
  END i_d[98]
  PIN i_d[99]
    DIRECTION INPUT ;
    USE SIGNAL ;
    PORT
      LAYER M5 ;
        RECT  37.2 34.476 37.224 34.56 ;
    END
  END i_d[99]
  PIN i_d[9]
    DIRECTION INPUT ;
    USE SIGNAL ;
    PORT
      LAYER M5 ;
        RECT  40.848 34.476 40.872 34.56 ;
    END
  END i_d[9]
  PIN i_h[0]
    DIRECTION INPUT ;
    USE SIGNAL ;
    PORT
      LAYER M5 ;
        RECT  7.728 34.476 7.752 34.56 ;
    END
  END i_h[0]
  PIN i_h[10]
    DIRECTION INPUT ;
    USE SIGNAL ;
    PORT
      LAYER M5 ;
        RECT  8.688 34.476 8.712 34.56 ;
    END
  END i_h[10]
  PIN i_h[11]
    DIRECTION INPUT ;
    USE SIGNAL ;
    PORT
      LAYER M5 ;
        RECT  8.784 34.476 8.808 34.56 ;
    END
  END i_h[11]
  PIN i_h[12]
    DIRECTION INPUT ;
    USE SIGNAL ;
    PORT
      LAYER M5 ;
        RECT  8.88 34.476 8.904 34.56 ;
    END
  END i_h[12]
  PIN i_h[13]
    DIRECTION INPUT ;
    USE SIGNAL ;
    PORT
      LAYER M5 ;
        RECT  8.976 34.476 9 34.56 ;
    END
  END i_h[13]
  PIN i_h[14]
    DIRECTION INPUT ;
    USE SIGNAL ;
    PORT
      LAYER M5 ;
        RECT  9.072 34.476 9.096 34.56 ;
    END
  END i_h[14]
  PIN i_h[15]
    DIRECTION INPUT ;
    USE SIGNAL ;
    PORT
      LAYER M5 ;
        RECT  9.168 34.476 9.192 34.56 ;
    END
  END i_h[15]
  PIN i_h[16]
    DIRECTION INPUT ;
    USE SIGNAL ;
    PORT
      LAYER M5 ;
        RECT  9.264 34.476 9.288 34.56 ;
    END
  END i_h[16]
  PIN i_h[17]
    DIRECTION INPUT ;
    USE SIGNAL ;
    PORT
      LAYER M5 ;
        RECT  9.36 34.476 9.384 34.56 ;
    END
  END i_h[17]
  PIN i_h[18]
    DIRECTION INPUT ;
    USE SIGNAL ;
    PORT
      LAYER M5 ;
        RECT  9.456 34.476 9.48 34.56 ;
    END
  END i_h[18]
  PIN i_h[19]
    DIRECTION INPUT ;
    USE SIGNAL ;
    PORT
      LAYER M5 ;
        RECT  9.552 34.476 9.576 34.56 ;
    END
  END i_h[19]
  PIN i_h[1]
    DIRECTION INPUT ;
    USE SIGNAL ;
    PORT
      LAYER M5 ;
        RECT  7.824 34.476 7.848 34.56 ;
    END
  END i_h[1]
  PIN i_h[20]
    DIRECTION INPUT ;
    USE SIGNAL ;
    PORT
      LAYER M5 ;
        RECT  9.648 34.476 9.672 34.56 ;
    END
  END i_h[20]
  PIN i_h[21]
    DIRECTION INPUT ;
    USE SIGNAL ;
    PORT
      LAYER M5 ;
        RECT  9.744 34.476 9.768 34.56 ;
    END
  END i_h[21]
  PIN i_h[22]
    DIRECTION INPUT ;
    USE SIGNAL ;
    PORT
      LAYER M5 ;
        RECT  9.84 34.476 9.864 34.56 ;
    END
  END i_h[22]
  PIN i_h[23]
    DIRECTION INPUT ;
    USE SIGNAL ;
    PORT
      LAYER M5 ;
        RECT  9.936 34.476 9.96 34.56 ;
    END
  END i_h[23]
  PIN i_h[24]
    DIRECTION INPUT ;
    USE SIGNAL ;
    PORT
      LAYER M5 ;
        RECT  10.032 34.476 10.056 34.56 ;
    END
  END i_h[24]
  PIN i_h[25]
    DIRECTION INPUT ;
    USE SIGNAL ;
    PORT
      LAYER M5 ;
        RECT  10.128 34.476 10.152 34.56 ;
    END
  END i_h[25]
  PIN i_h[26]
    DIRECTION INPUT ;
    USE SIGNAL ;
    PORT
      LAYER M5 ;
        RECT  10.224 34.476 10.248 34.56 ;
    END
  END i_h[26]
  PIN i_h[27]
    DIRECTION INPUT ;
    USE SIGNAL ;
    PORT
      LAYER M5 ;
        RECT  10.32 34.476 10.344 34.56 ;
    END
  END i_h[27]
  PIN i_h[28]
    DIRECTION INPUT ;
    USE SIGNAL ;
    PORT
      LAYER M5 ;
        RECT  10.416 34.476 10.44 34.56 ;
    END
  END i_h[28]
  PIN i_h[29]
    DIRECTION INPUT ;
    USE SIGNAL ;
    PORT
      LAYER M5 ;
        RECT  10.512 34.476 10.536 34.56 ;
    END
  END i_h[29]
  PIN i_h[2]
    DIRECTION INPUT ;
    USE SIGNAL ;
    PORT
      LAYER M5 ;
        RECT  7.92 34.476 7.944 34.56 ;
    END
  END i_h[2]
  PIN i_h[30]
    DIRECTION INPUT ;
    USE SIGNAL ;
    PORT
      LAYER M5 ;
        RECT  10.608 34.476 10.632 34.56 ;
    END
  END i_h[30]
  PIN i_h[31]
    DIRECTION INPUT ;
    USE SIGNAL ;
    PORT
      LAYER M5 ;
        RECT  10.704 34.476 10.728 34.56 ;
    END
  END i_h[31]
  PIN i_h[32]
    DIRECTION INPUT ;
    USE SIGNAL ;
    PORT
      LAYER M5 ;
        RECT  63.408 34.476 63.432 34.56 ;
    END
  END i_h[32]
  PIN i_h[33]
    DIRECTION INPUT ;
    USE SIGNAL ;
    PORT
      LAYER M5 ;
        RECT  63.504 34.476 63.528 34.56 ;
    END
  END i_h[33]
  PIN i_h[34]
    DIRECTION INPUT ;
    USE SIGNAL ;
    PORT
      LAYER M5 ;
        RECT  63.6 34.476 63.624 34.56 ;
    END
  END i_h[34]
  PIN i_h[35]
    DIRECTION INPUT ;
    USE SIGNAL ;
    PORT
      LAYER M5 ;
        RECT  63.696 34.476 63.72 34.56 ;
    END
  END i_h[35]
  PIN i_h[36]
    DIRECTION INPUT ;
    USE SIGNAL ;
    PORT
      LAYER M5 ;
        RECT  63.792 34.476 63.816 34.56 ;
    END
  END i_h[36]
  PIN i_h[37]
    DIRECTION INPUT ;
    USE SIGNAL ;
    PORT
      LAYER M5 ;
        RECT  63.888 34.476 63.912 34.56 ;
    END
  END i_h[37]
  PIN i_h[38]
    DIRECTION INPUT ;
    USE SIGNAL ;
    PORT
      LAYER M5 ;
        RECT  63.984 34.476 64.008 34.56 ;
    END
  END i_h[38]
  PIN i_h[39]
    DIRECTION INPUT ;
    USE SIGNAL ;
    PORT
      LAYER M5 ;
        RECT  64.08 34.476 64.104 34.56 ;
    END
  END i_h[39]
  PIN i_h[3]
    DIRECTION INPUT ;
    USE SIGNAL ;
    PORT
      LAYER M5 ;
        RECT  8.016 34.476 8.04 34.56 ;
    END
  END i_h[3]
  PIN i_h[40]
    DIRECTION INPUT ;
    USE SIGNAL ;
    PORT
      LAYER M5 ;
        RECT  64.176 34.476 64.2 34.56 ;
    END
  END i_h[40]
  PIN i_h[41]
    DIRECTION INPUT ;
    USE SIGNAL ;
    PORT
      LAYER M5 ;
        RECT  64.272 34.476 64.296 34.56 ;
    END
  END i_h[41]
  PIN i_h[42]
    DIRECTION INPUT ;
    USE SIGNAL ;
    PORT
      LAYER M5 ;
        RECT  64.368 34.476 64.392 34.56 ;
    END
  END i_h[42]
  PIN i_h[43]
    DIRECTION INPUT ;
    USE SIGNAL ;
    PORT
      LAYER M5 ;
        RECT  64.464 34.476 64.488 34.56 ;
    END
  END i_h[43]
  PIN i_h[44]
    DIRECTION INPUT ;
    USE SIGNAL ;
    PORT
      LAYER M5 ;
        RECT  64.56 34.476 64.584 34.56 ;
    END
  END i_h[44]
  PIN i_h[45]
    DIRECTION INPUT ;
    USE SIGNAL ;
    PORT
      LAYER M5 ;
        RECT  64.656 34.476 64.68 34.56 ;
    END
  END i_h[45]
  PIN i_h[46]
    DIRECTION INPUT ;
    USE SIGNAL ;
    PORT
      LAYER M5 ;
        RECT  64.752 34.476 64.776 34.56 ;
    END
  END i_h[46]
  PIN i_h[47]
    DIRECTION INPUT ;
    USE SIGNAL ;
    PORT
      LAYER M5 ;
        RECT  64.848 34.476 64.872 34.56 ;
    END
  END i_h[47]
  PIN i_h[48]
    DIRECTION INPUT ;
    USE SIGNAL ;
    PORT
      LAYER M5 ;
        RECT  64.944 34.476 64.968 34.56 ;
    END
  END i_h[48]
  PIN i_h[49]
    DIRECTION INPUT ;
    USE SIGNAL ;
    PORT
      LAYER M5 ;
        RECT  65.04 34.476 65.064 34.56 ;
    END
  END i_h[49]
  PIN i_h[4]
    DIRECTION INPUT ;
    USE SIGNAL ;
    PORT
      LAYER M5 ;
        RECT  8.112 34.476 8.136 34.56 ;
    END
  END i_h[4]
  PIN i_h[50]
    DIRECTION INPUT ;
    USE SIGNAL ;
    PORT
      LAYER M5 ;
        RECT  65.136 34.476 65.16 34.56 ;
    END
  END i_h[50]
  PIN i_h[5]
    DIRECTION INPUT ;
    USE SIGNAL ;
    PORT
      LAYER M5 ;
        RECT  8.208 34.476 8.232 34.56 ;
    END
  END i_h[5]
  PIN i_h[6]
    DIRECTION INPUT ;
    USE SIGNAL ;
    PORT
      LAYER M5 ;
        RECT  8.304 34.476 8.328 34.56 ;
    END
  END i_h[6]
  PIN i_h[7]
    DIRECTION INPUT ;
    USE SIGNAL ;
    PORT
      LAYER M5 ;
        RECT  8.4 34.476 8.424 34.56 ;
    END
  END i_h[7]
  PIN i_h[8]
    DIRECTION INPUT ;
    USE SIGNAL ;
    PORT
      LAYER M5 ;
        RECT  8.496 34.476 8.52 34.56 ;
    END
  END i_h[8]
  PIN i_h[9]
    DIRECTION INPUT ;
    USE SIGNAL ;
    PORT
      LAYER M5 ;
        RECT  8.592 34.476 8.616 34.56 ;
    END
  END i_h[9]
  PIN i_v
    DIRECTION INPUT ;
    USE SIGNAL ;
    PORT
      LAYER M5 ;
        RECT  65.232 34.476 65.256 34.56 ;
    END
  END i_v
  PIN pe_i[1]
    DIRECTION INPUT ;
    USE SIGNAL ;
    PORT
      LAYER M4 ;
        RECT  0 10.416 0.084 10.44 ;
    END
  END pe_i[1]
  PIN pe_i[2]
    DIRECTION INPUT ;
    USE SIGNAL ;
    PORT
      LAYER M4 ;
        RECT  0 10.512 0.084 10.536 ;
    END
  END pe_i[2]
  PIN pe_i[3]
    DIRECTION INPUT ;
    USE SIGNAL ;
    PORT
      LAYER M4 ;
        RECT  0 10.608 0.084 10.632 ;
    END
  END pe_i[3]
  PIN rs
    DIRECTION INPUT ;
    USE SIGNAL ;
    PORT
      LAYER M4 ;
        RECT  0 10.704 0.084 10.728 ;
    END
  END rs
  PIN VDD
    DIRECTION INOUT ;
    USE POWER ;
    PORT
      LAYER M5 ;
        RECT  61.992 2.151 62.112 32.409 ;
        RECT  56.592 2.151 56.712 32.409 ;
        RECT  51.192 2.151 51.312 32.409 ;
        RECT  45.792 2.151 45.912 32.409 ;
        RECT  40.392 2.151 40.512 32.409 ;
        RECT  34.992 2.151 35.112 32.409 ;
        RECT  29.592 2.151 29.712 32.409 ;
        RECT  24.192 2.151 24.312 32.409 ;
        RECT  18.792 2.151 18.912 32.409 ;
        RECT  13.392 2.151 13.512 32.409 ;
        RECT  7.992 2.151 8.112 32.409 ;
        RECT  2.592 2.151 2.712 32.409 ;
    END
  END VDD
  PIN VSS
    DIRECTION INOUT ;
    USE GROUND ;
    PORT
      LAYER M5 ;
        RECT  61.8 2.137 61.92 32.423 ;
        RECT  56.4 2.137 56.52 32.423 ;
        RECT  51 2.137 51.12 32.423 ;
        RECT  45.6 2.137 45.72 32.423 ;
        RECT  40.2 2.137 40.32 32.423 ;
        RECT  34.8 2.137 34.92 32.423 ;
        RECT  29.4 2.137 29.52 32.423 ;
        RECT  24 2.137 24.12 32.423 ;
        RECT  18.6 2.137 18.72 32.423 ;
        RECT  13.2 2.137 13.32 32.423 ;
        RECT  7.8 2.137 7.92 32.423 ;
        RECT  2.4 2.137 2.52 32.423 ;
    END
  END VSS
  # OT_OBS_CLOSED layer=M5 d_um=1.536 added=118
  OBS
    LAYER RVTN ;
     RECT  2.16 2.16 66.96 2.295 ;
     RECT  2.16 2.565 66.96 2.835 ;
     RECT  2.16 3.105 66.96 3.375 ;
     RECT  2.16 3.645 66.96 3.915 ;
     RECT  2.16 4.185 66.96 4.455 ;
     RECT  2.16 4.725 66.96 4.995 ;
     RECT  2.16 5.265 66.96 5.535 ;
     RECT  2.16 5.805 66.96 6.075 ;
     RECT  2.16 6.345 66.96 6.615 ;
     RECT  2.16 6.885 66.96 7.155 ;
     RECT  2.16 7.425 66.96 7.695 ;
     RECT  2.16 7.965 66.96 8.235 ;
     RECT  2.16 8.505 66.96 8.775 ;
     RECT  2.16 9.045 66.96 9.315 ;
     RECT  2.16 9.585 66.96 9.855 ;
     RECT  2.16 10.125 66.96 10.395 ;
     RECT  2.16 10.665 66.96 10.935 ;
     RECT  2.16 11.205 66.96 11.475 ;
     RECT  2.16 11.745 66.96 12.015 ;
     RECT  2.16 12.285 66.96 12.555 ;
     RECT  2.16 12.825 66.96 13.095 ;
     RECT  2.16 13.365 66.96 13.635 ;
     RECT  2.16 13.905 66.96 14.175 ;
     RECT  2.16 14.445 66.96 14.715 ;
     RECT  2.16 14.985 66.96 15.255 ;
     RECT  2.16 15.525 66.96 15.795 ;
     RECT  2.16 16.065 66.96 16.335 ;
     RECT  2.16 16.605 66.96 16.875 ;
     RECT  2.16 17.145 66.96 17.415 ;
     RECT  2.16 17.685 66.96 17.955 ;
     RECT  2.16 18.225 66.96 18.495 ;
     RECT  2.16 18.765 66.96 19.035 ;
     RECT  2.16 19.305 66.96 19.575 ;
     RECT  2.16 19.845 66.96 20.115 ;
     RECT  2.16 20.385 66.96 20.655 ;
     RECT  2.16 20.925 66.96 21.195 ;
     RECT  2.16 21.465 66.96 21.735 ;
     RECT  2.16 22.005 66.96 22.275 ;
     RECT  2.16 22.545 66.96 22.815 ;
     RECT  2.16 23.085 66.96 23.355 ;
     RECT  2.16 23.625 66.96 23.895 ;
     RECT  2.16 24.165 66.96 24.435 ;
     RECT  2.16 24.705 66.96 24.975 ;
     RECT  2.16 25.245 66.96 25.515 ;
     RECT  2.16 25.785 66.96 26.055 ;
     RECT  2.16 26.325 66.96 26.595 ;
     RECT  2.16 26.865 66.96 27.135 ;
     RECT  2.16 27.405 66.96 27.675 ;
     RECT  2.16 27.945 66.96 28.215 ;
     RECT  2.16 28.485 66.96 28.755 ;
     RECT  2.16 29.025 66.96 29.295 ;
     RECT  2.16 29.565 66.96 29.835 ;
     RECT  2.16 30.105 66.96 30.375 ;
     RECT  2.16 30.645 66.96 30.915 ;
     RECT  2.16 31.185 66.96 31.455 ;
     RECT  2.16 31.725 66.96 31.995 ;
     RECT  2.16 32.265 66.96 32.4 ;
    LAYER RVTP ;
     RECT  2.16 2.295 66.96 2.565 ;
     RECT  2.16 2.835 66.96 3.105 ;
     RECT  2.16 3.375 66.96 3.645 ;
     RECT  2.16 3.915 66.96 4.185 ;
     RECT  2.16 4.455 66.96 4.725 ;
     RECT  2.16 4.995 66.96 5.265 ;
     RECT  2.16 5.535 66.96 5.805 ;
     RECT  2.16 6.075 66.96 6.345 ;
     RECT  2.16 6.615 66.96 6.885 ;
     RECT  2.16 7.155 66.96 7.425 ;
     RECT  2.16 7.695 66.96 7.965 ;
     RECT  2.16 8.235 66.96 8.505 ;
     RECT  2.16 8.775 66.96 9.045 ;
     RECT  2.16 9.315 66.96 9.585 ;
     RECT  2.16 9.855 66.96 10.125 ;
     RECT  2.16 10.395 66.96 10.665 ;
     RECT  2.16 10.935 66.96 11.205 ;
     RECT  2.16 11.475 66.96 11.745 ;
     RECT  2.16 12.015 66.96 12.285 ;
     RECT  2.16 12.555 66.96 12.825 ;
     RECT  2.16 13.095 66.96 13.365 ;
     RECT  2.16 13.635 66.96 13.905 ;
     RECT  2.16 14.175 66.96 14.445 ;
     RECT  2.16 14.715 66.96 14.985 ;
     RECT  2.16 15.255 66.96 15.525 ;
     RECT  2.16 15.795 66.96 16.065 ;
     RECT  2.16 16.335 66.96 16.605 ;
     RECT  2.16 16.875 66.96 17.145 ;
     RECT  2.16 17.415 66.96 17.685 ;
     RECT  2.16 17.955 66.96 18.225 ;
     RECT  2.16 18.495 66.96 18.765 ;
     RECT  2.16 19.035 66.96 19.305 ;
     RECT  2.16 19.575 66.96 19.845 ;
     RECT  2.16 20.115 66.96 20.385 ;
     RECT  2.16 20.655 66.96 20.925 ;
     RECT  2.16 21.195 66.96 21.465 ;
     RECT  2.16 21.735 66.96 22.005 ;
     RECT  2.16 22.275 66.96 22.545 ;
     RECT  2.16 22.815 66.96 23.085 ;
     RECT  2.16 23.355 66.96 23.625 ;
     RECT  2.16 23.895 66.96 24.165 ;
     RECT  2.16 24.435 66.96 24.705 ;
     RECT  2.16 24.975 66.96 25.245 ;
     RECT  2.16 25.515 66.96 25.785 ;
     RECT  2.16 26.055 66.96 26.325 ;
     RECT  2.16 26.595 66.96 26.865 ;
     RECT  2.16 27.135 66.96 27.405 ;
     RECT  2.16 27.675 66.96 27.945 ;
     RECT  2.16 28.215 66.96 28.485 ;
     RECT  2.16 28.755 66.96 29.025 ;
     RECT  2.16 29.295 66.96 29.565 ;
     RECT  2.16 29.835 66.96 30.105 ;
     RECT  2.16 30.375 66.96 30.645 ;
     RECT  2.16 30.915 66.96 31.185 ;
     RECT  2.16 31.455 66.96 31.725 ;
     RECT  2.16 31.995 66.96 32.265 ;
    LAYER M1 ;
     RECT  2.16 2.151 66.96 32.409 ;
    LAYER M2 ;
     RECT  0.103 10.17 2.16 10.188 ;
     RECT  2.16 2.151 3.883 32.409 ;
     RECT  3.883 2.106 4.487 32.409 ;
     RECT  4.487 2.151 9.139 32.409 ;
     RECT  9.139 2.151 11.839 32.454 ;
     RECT  12.127 1.152 12.227 1.17 ;
     RECT  11.839 2.106 12.623 32.454 ;
     RECT  12.623 2.151 13.891 32.454 ;
     RECT  13.891 2.151 14.027 33.066 ;
     RECT  15.259 1.152 15.359 1.17 ;
     RECT  14.027 2.151 15.511 32.454 ;
     RECT  15.511 2.151 15.611 33.066 ;
     RECT  15.611 2.151 21.163 32.409 ;
     RECT  21.163 2.151 21.271 32.454 ;
     RECT  21.271 2.151 21.371 32.562 ;
     RECT  22.423 1.152 22.595 1.17 ;
     RECT  21.371 2.151 25.115 32.454 ;
     RECT  25.115 2.151 27.103 32.409 ;
     RECT  27.103 2.151 27.203 32.562 ;
     RECT  27.203 2.151 28.255 32.409 ;
     RECT  28.255 2.151 28.427 32.562 ;
     RECT  29.119 1.152 29.291 1.17 ;
     RECT  28.427 2.151 29.335 32.409 ;
     RECT  29.335 2.151 29.615 32.724 ;
     RECT  29.615 2.151 30.595 32.409 ;
     RECT  30.595 2.151 30.631 32.994 ;
     RECT  30.631 2.151 30.731 33.066 ;
     RECT  30.731 2.151 34.771 32.409 ;
     RECT  34.771 2.106 36.347 32.409 ;
     RECT  36.347 2.151 37.039 32.409 ;
     RECT  37.039 2.151 37.507 32.454 ;
     RECT  37.507 2.106 38.651 32.454 ;
     RECT  38.651 2.151 44.843 32.454 ;
     RECT  44.843 2.151 45.211 32.409 ;
     RECT  45.211 2.07 45.671 32.409 ;
     RECT  45.671 2.151 46.687 32.409 ;
     RECT  46.687 2.106 47.659 32.409 ;
     RECT  47.659 2.034 48.875 32.409 ;
     RECT  48.875 2.151 50.899 32.409 ;
     RECT  50.899 2.106 52.043 32.409 ;
     RECT  52.043 2.151 53.167 32.409 ;
     RECT  53.167 2.106 54.167 32.409 ;
     RECT  54.167 2.151 55.471 32.409 ;
     RECT  55.471 2.106 55.759 32.409 ;
     RECT  55.759 2.034 56.399 32.409 ;
     RECT  56.399 2.106 56.723 32.409 ;
     RECT  56.723 2.151 57.883 32.409 ;
     RECT  57.883 2.07 58.747 32.409 ;
     RECT  58.747 1.836 63.455 32.409 ;
     RECT  63.455 1.881 63.707 32.409 ;
     RECT  63.707 2.106 63.851 32.409 ;
     RECT  63.851 2.151 66.96 32.409 ;
    LAYER M3 ;
     RECT  15.012 0.091 15.03 0.139 ;
     RECT  15.984 0.091 16.002 0.139 ;
     RECT  21.06 0.091 21.222 0.139 ;
     RECT  30.708 0.091 31.086 0.139 ;
     RECT  56.844 0.091 56.862 0.139 ;
     RECT  61.596 0.091 61.614 0.139 ;
     RECT  58.644 0.043 58.662 0.173 ;
     RECT  30.708 0.139 31.194 0.187 ;
     RECT  61.596 0.139 61.686 0.187 ;
     RECT  63.216 0.043 63.234 0.187 ;
     RECT  10.764 0.091 10.782 0.221 ;
     RECT  40.86 0.091 40.878 0.221 ;
     RECT  52.308 0.091 52.83 0.221 ;
     RECT  21.06 0.139 21.294 0.235 ;
     RECT  23.472 0.091 23.49 0.235 ;
     RECT  24.408 0.187 24.426 0.235 ;
     RECT  46.62 0.091 46.638 0.235 ;
     RECT  23.472 0.235 24.426 0.269 ;
     RECT  56.844 0.139 56.97 0.269 ;
     RECT  20.988 0.235 21.294 0.283 ;
     RECT  29.772 0.091 29.79 0.283 ;
     RECT  30.708 0.187 31.266 0.283 ;
     RECT  56.952 0.269 56.97 0.317 ;
     RECT  23.868 0.269 24.426 0.365 ;
     RECT  20.844 0.283 21.294 0.413 ;
     RECT  23.868 0.365 24.354 0.413 ;
     RECT  29.772 0.283 31.266 0.413 ;
     RECT  9.756 0.187 9.774 0.475 ;
     RECT  3.744 0.091 5.166 0.523 ;
     RECT  5.976 0.091 5.994 0.523 ;
     RECT  9.36 0.475 9.774 0.523 ;
     RECT  28.44 0.091 28.458 0.523 ;
     RECT  29.772 0.413 31.194 0.523 ;
     RECT  44.28 0.091 44.298 0.523 ;
     RECT  54.576 0.091 54.594 0.523 ;
     RECT  7.164 0.091 7.182 0.571 ;
     RECT  8.208 0.187 8.226 0.571 ;
     RECT  15.012 0.139 16.002 0.571 ;
     RECT  37.656 0.091 38.25 0.571 ;
     RECT  41.796 0.091 43.11 0.571 ;
     RECT  43.884 0.523 44.298 0.571 ;
     RECT  46.008 0.235 46.638 0.571 ;
     RECT  48.708 0.091 49.05 0.571 ;
     RECT  28.188 0.523 31.194 0.605 ;
     RECT  9.36 0.523 9.846 0.653 ;
     RECT  26.928 0.523 27.378 1.051 ;
     RECT  28.188 0.605 30.51 1.051 ;
     RECT  5.976 0.523 6.39 1.099 ;
     RECT  7.164 0.571 8.226 1.099 ;
     RECT  20.016 0.091 20.034 1.099 ;
     RECT  21.06 0.413 21.294 1.099 ;
     RECT  24.156 0.413 24.354 1.099 ;
     RECT  35.82 0.571 35.838 1.099 ;
     RECT  45.648 0.571 46.638 1.099 ;
     RECT  47.592 0.091 47.61 1.099 ;
     RECT  50.724 0.091 50.742 1.099 ;
     RECT  3.024 0.523 5.166 1.147 ;
     RECT  5.976 1.099 8.226 1.147 ;
     RECT  12.132 0.523 12.15 1.147 ;
     RECT  12.924 0.091 12.942 1.147 ;
     RECT  14.004 0.571 14.022 1.147 ;
     RECT  15.012 0.571 16.578 1.147 ;
     RECT  21.06 1.099 21.33 1.147 ;
     RECT  22.356 0.091 22.626 1.147 ;
     RECT  37.476 0.571 38.25 1.147 ;
     RECT  41.796 0.571 44.298 1.147 ;
     RECT  48.492 0.571 49.05 1.147 ;
     RECT  50.004 1.099 50.742 1.147 ;
     RECT  26.928 1.051 30.51 1.181 ;
     RECT  33.804 1.147 33.822 1.195 ;
     RECT  40.788 1.147 40.806 1.195 ;
     RECT  48.492 1.147 50.742 1.195 ;
     RECT  61.596 0.187 63.234 1.387 ;
     RECT  61.56 1.387 63.234 1.435 ;
     RECT  3.024 1.147 8.37 1.723 ;
     RECT  9.432 0.653 9.846 1.723 ;
     RECT  12.132 1.147 12.942 1.723 ;
     RECT  14.904 1.147 16.578 1.723 ;
     RECT  17.496 0.571 17.514 1.723 ;
     RECT  20.016 1.099 20.322 1.723 ;
     RECT  21.06 1.147 22.626 1.723 ;
     RECT  24.156 1.099 24.498 1.723 ;
     RECT  25.848 0.523 25.866 1.723 ;
     RECT  26.928 1.181 27.414 1.723 ;
     RECT  28.188 1.181 30.51 1.723 ;
     RECT  32.688 0.571 32.706 1.723 ;
     RECT  33.66 1.195 33.822 1.723 ;
     RECT  34.596 0.091 34.974 1.723 ;
     RECT  35.82 1.099 36.162 1.723 ;
     RECT  37.404 1.147 38.25 1.723 ;
     RECT  39.096 0.523 39.114 1.723 ;
     RECT  39.888 1.147 39.906 1.723 ;
     RECT  40.788 1.195 40.986 1.723 ;
     RECT  41.796 1.147 44.802 1.723 ;
     RECT  45.648 1.099 47.61 1.723 ;
     RECT  48.492 1.195 51.174 1.723 ;
     RECT  52.308 0.221 52.758 1.723 ;
     RECT  53.856 0.523 54.882 1.723 ;
     RECT  61.56 1.435 63.306 1.723 ;
     RECT  13.68 1.147 14.022 1.771 ;
     RECT  14.796 1.723 17.622 1.771 ;
     RECT  52.308 1.723 52.974 1.771 ;
     RECT  53.856 1.723 56.574 1.771 ;
     RECT  59.868 0.907 59.886 1.771 ;
     RECT  13.68 1.771 17.622 1.819 ;
     RECT  60.948 1.723 63.306 1.831 ;
     RECT  18.756 1.723 22.878 1.867 ;
     RECT  52.308 1.771 57.078 1.867 ;
     RECT  60.948 1.831 63.45 1.876 ;
     RECT  59.868 1.771 60.066 1.915 ;
     RECT  60.948 1.876 63.702 1.915 ;
     RECT  18.504 1.867 22.878 1.963 ;
     RECT  59.868 1.915 63.702 1.963 ;
     RECT  58.752 1.831 58.77 1.993 ;
     RECT  11.124 1.723 12.942 2.011 ;
     RECT  13.68 1.819 17.658 2.011 ;
     RECT  58.752 1.993 58.806 2.059 ;
     RECT  52.308 1.867 57.402 2.065 ;
     RECT  33.624 1.723 38.25 2.101 ;
     RECT  39.096 1.723 51.21 2.101 ;
     RECT  52.308 2.065 57.906 2.101 ;
     RECT  58.716 2.059 58.806 2.101 ;
     RECT  59.868 1.963 63.774 2.101 ;
     RECT  3.024 1.723 10.242 2.143 ;
     RECT  24.156 1.723 26.01 2.143 ;
     RECT  52.02 2.101 58.806 2.155 ;
     RECT  59.868 2.101 63.846 2.155 ;
     RECT  24.015 2.143 26.01 2.191 ;
     RECT  26.892 1.723 27.414 2.191 ;
     RECT  28.188 1.723 31.338 2.191 ;
     RECT  32.184 1.723 32.706 2.191 ;
     RECT  33.624 2.101 51.21 2.191 ;
     RECT  52.02 2.155 63.846 2.191 ;
     RECT  26.748 2.191 63.846 2.219 ;
     RECT  2.415 2.143 10.242 2.227 ;
     RECT  11.124 2.011 17.658 2.227 ;
     RECT  18.468 1.963 22.878 2.227 ;
     RECT  23.904 2.191 26.01 2.227 ;
     RECT  2.415 2.227 17.658 2.251 ;
     RECT  18.468 2.227 26.01 2.251 ;
     RECT  2.415 2.251 26.01 2.335 ;
     RECT  26.748 2.219 63.774 2.335 ;
     RECT  2.415 2.335 63.774 2.489 ;
     RECT  2.415 2.489 63.666 2.525 ;
     RECT  2.415 2.525 63.198 2.641 ;
     RECT  2.34 2.641 63.198 2.759 ;
     RECT  2.34 2.759 63.054 3.371 ;
     RECT  2.34 3.371 62.118 3.407 ;
     RECT  2.34 3.407 62.097 4.919 ;
     RECT  63.036 3.371 63.054 4.991 ;
     RECT  2.376 4.919 62.097 5.999 ;
     RECT  2.415 5.999 62.097 9.517 ;
     RECT  2.412 9.517 62.097 9.581 ;
     RECT  2.415 9.581 62.097 10.411 ;
     RECT  0.108 10.165 0.126 10.507 ;
     RECT  0.108 10.507 0.342 10.637 ;
     RECT  2.412 10.411 62.097 10.699 ;
     RECT  2.304 10.699 62.097 10.769 ;
     RECT  2.304 10.769 53.406 10.895 ;
     RECT  54.144 10.769 62.097 11.039 ;
     RECT  2.412 10.895 53.406 11.165 ;
     RECT  66.456 10.561 66.474 12.793 ;
     RECT  66.456 12.793 66.582 13.369 ;
     RECT  65.304 13.261 65.322 13.405 ;
     RECT  64.8 13.405 65.322 13.441 ;
     RECT  64.656 13.441 65.322 13.945 ;
     RECT  64.116 13.945 65.322 14.683 ;
     RECT  54.216 11.039 62.097 14.791 ;
     RECT  62.856 13.981 62.874 14.791 ;
     RECT  54.216 14.791 62.874 15.295 ;
     RECT  2.415 11.165 53.406 16.411 ;
     RECT  54.216 15.295 62.946 16.411 ;
     RECT  2.415 16.411 62.946 17.879 ;
     RECT  2.415 17.879 59.742 19.499 ;
     RECT  60.768 17.879 62.946 20.191 ;
     RECT  5.76 19.499 59.742 20.309 ;
     RECT  5.832 20.309 59.742 21.937 ;
     RECT  60.48 20.191 62.946 21.937 ;
     RECT  5.832 21.937 62.946 24.629 ;
     RECT  2.415 19.499 4.914 25.249 ;
     RECT  5.832 24.629 32.562 25.249 ;
     RECT  64.044 14.683 65.322 25.531 ;
     RECT  2.415 25.249 32.562 25.555 ;
     RECT  33.444 24.629 62.946 25.555 ;
     RECT  2.415 25.555 62.946 27.481 ;
     RECT  63.828 25.531 65.322 27.481 ;
     RECT  66.06 13.369 66.582 27.949 ;
     RECT  2.415 27.481 65.322 28.759 ;
     RECT  66.06 27.949 66.618 28.759 ;
     RECT  2.415 28.759 66.618 29.641 ;
     RECT  2.415 29.641 66.834 30.029 ;
     RECT  2.415 30.029 66.618 30.137 ;
     RECT  4.932 30.137 66.618 30.299 ;
     RECT  2.415 30.137 4.05 30.407 ;
     RECT  2.415 30.407 3.762 30.569 ;
     RECT  5.436 30.299 66.618 30.605 ;
     RECT  2.415 30.569 3.33 30.641 ;
     RECT  5.436 30.605 5.994 30.749 ;
     RECT  6.768 30.605 66.618 31.379 ;
     RECT  6.768 31.379 66.006 31.451 ;
     RECT  6.84 31.451 66.006 31.649 ;
     RECT  6.84 31.649 65.898 31.919 ;
     RECT  5.436 30.749 5.454 32.099 ;
     RECT  6.84 31.919 65.718 32.099 ;
     RECT  2.415 30.641 2.697 32.147 ;
     RECT  7.272 32.099 65.718 32.189 ;
     RECT  12.132 32.189 35.046 32.285 ;
     RECT  7.272 32.189 11.394 32.333 ;
     RECT  12.132 32.285 17.262 32.369 ;
     RECT  35.784 32.189 65.718 32.369 ;
     RECT  18.216 32.285 35.046 32.381 ;
     RECT  35.784 32.369 49.302 32.381 ;
     RECT  50.04 32.369 65.286 32.381 ;
     RECT  2.415 32.147 2.505 32.417 ;
     RECT  39.564 32.381 49.302 32.429 ;
     RECT  57.924 32.381 65.286 32.429 ;
     RECT  7.452 32.333 11.394 32.477 ;
     RECT  12.132 32.369 16.902 32.477 ;
     RECT  19.908 32.381 23.058 32.477 ;
     RECT  33.948 32.381 35.046 32.477 ;
     RECT  35.784 32.381 38.142 32.477 ;
     RECT  39.564 32.429 47.142 32.477 ;
     RECT  48.168 32.429 49.122 32.477 ;
     RECT  50.04 32.381 57.078 32.477 ;
     RECT  57.924 32.429 65.214 32.477 ;
     RECT  7.452 32.477 8.514 32.525 ;
     RECT  23.868 32.381 27.306 32.525 ;
     RECT  28.08 32.381 31.914 32.525 ;
     RECT  34.632 32.477 35.046 32.525 ;
     RECT  45.756 32.477 46.746 32.525 ;
     RECT  56.304 32.477 56.754 32.525 ;
     RECT  59.256 32.477 64.926 32.525 ;
     RECT  7.452 32.525 7.974 32.573 ;
     RECT  12.348 32.477 14.238 32.573 ;
     RECT  18.216 32.381 19.098 32.573 ;
     RECT  34.632 32.525 34.974 32.573 ;
     RECT  39.744 32.477 41.562 32.573 ;
     RECT  59.256 32.525 64.314 32.573 ;
     RECT  12.348 32.573 12.834 32.621 ;
     RECT  23.868 32.525 25.542 32.621 ;
     RECT  28.08 32.525 29.646 32.621 ;
     RECT  34.632 32.573 34.686 32.621 ;
     RECT  50.472 32.477 51.822 32.621 ;
     RECT  61.776 32.573 61.794 32.621 ;
     RECT  40.104 32.573 41.562 32.669 ;
     RECT  50.472 32.621 50.994 32.669 ;
     RECT  37.728 32.477 38.142 33.053 ;
     RECT  53.82 32.477 55.458 33.053 ;
     RECT  12.348 32.621 12.762 33.101 ;
     RECT  13.644 32.573 14.238 33.101 ;
     RECT  15.3 32.477 16.902 33.101 ;
     RECT  19.08 32.573 19.098 33.101 ;
     RECT  26.604 32.525 27.306 33.101 ;
     RECT  28.08 32.621 29.61 33.101 ;
     RECT  34.668 32.621 34.686 33.101 ;
     RECT  35.784 32.477 36.918 33.101 ;
     RECT  42.48 32.477 43.83 33.101 ;
     RECT  51.732 32.621 51.822 33.101 ;
     RECT  54.432 33.053 55.458 33.101 ;
     RECT  56.304 32.525 56.322 33.101 ;
     RECT  59.256 32.573 60.858 33.101 ;
     RECT  62.712 32.573 64.314 33.101 ;
     RECT  16.488 33.101 16.902 33.115 ;
     RECT  29.268 33.101 29.61 33.149 ;
     RECT  12.492 33.101 12.762 33.197 ;
     RECT  30.384 32.525 31.914 33.197 ;
     RECT  46.08 32.525 46.746 33.389 ;
     RECT  13.644 33.101 13.914 33.629 ;
     RECT  28.08 33.101 28.422 33.629 ;
     RECT  31.248 33.197 31.914 33.629 ;
     RECT  50.472 32.669 50.67 33.629 ;
     RECT  62.712 33.101 63.522 33.629 ;
     RECT  7.452 32.573 7.722 33.677 ;
     RECT  9.54 32.477 9.558 33.677 ;
     RECT  11.088 32.477 11.394 33.677 ;
     RECT  12.492 33.197 12.51 33.677 ;
     RECT  15.3 33.101 15.534 33.677 ;
     RECT  16.488 33.115 17.082 33.677 ;
     RECT  18.216 32.573 18.234 33.677 ;
     RECT  19.908 32.477 19.926 33.677 ;
     RECT  20.808 32.477 22.95 33.677 ;
     RECT  24.84 32.621 25.542 33.677 ;
     RECT  26.604 33.101 27.198 33.677 ;
     RECT  28.08 33.629 28.098 33.677 ;
     RECT  29.592 33.149 29.61 33.677 ;
     RECT  32.904 32.381 32.922 33.677 ;
     RECT  36.9 33.101 36.918 33.677 ;
     RECT  38.124 33.053 38.142 33.677 ;
     RECT  40.68 32.669 41.562 33.677 ;
     RECT  42.48 33.101 43.038 33.677 ;
     RECT  44.892 32.477 44.91 33.677 ;
     RECT  46.728 33.389 46.746 33.677 ;
     RECT  50.472 33.629 50.49 33.677 ;
     RECT  51.804 33.101 51.822 33.677 ;
     RECT  59.58 33.101 60.354 33.677 ;
     RECT  63.216 33.629 63.522 33.677 ;
     RECT  7.452 33.677 7.47 33.725 ;
     RECT  11.376 33.677 11.394 33.725 ;
     RECT  15.516 33.677 15.534 33.725 ;
     RECT  21.276 33.677 22.95 33.725 ;
     RECT  43.812 33.101 43.83 33.725 ;
     RECT  59.796 33.677 60.354 33.725 ;
     RECT  22.536 33.725 22.95 33.931 ;
     RECT  23.868 32.621 23.886 33.931 ;
     RECT  22.536 33.931 23.886 34.109 ;
     RECT  56.808 34.123 56.826 34.301 ;
     RECT  60.336 33.725 60.354 34.349 ;
     RECT  17.064 33.677 17.082 34.397 ;
     RECT  9.468 34.315 9.486 34.445 ;
     RECT  13.644 33.629 13.662 34.445 ;
     RECT  18.828 34.315 18.846 34.445 ;
     RECT  21.276 33.725 21.474 34.445 ;
     RECT  22.536 34.109 22.95 34.445 ;
     RECT  23.868 34.109 23.886 34.445 ;
     RECT  25.524 33.677 25.542 34.445 ;
     RECT  30.384 33.197 30.402 34.445 ;
     RECT  31.248 33.629 31.266 34.445 ;
     RECT  32.76 34.219 32.778 34.445 ;
     RECT  40.86 33.677 40.878 34.445 ;
     RECT  42.48 33.677 42.498 34.445 ;
     RECT  48.42 34.315 48.438 34.445 ;
     RECT  55.008 33.101 55.026 34.445 ;
     RECT  63.216 33.677 63.234 34.445 ;
     RECT  64.296 33.101 64.314 34.445 ;
    LAYER M4 ;
     RECT  0.06 10.32 0.227 10.728 ;
     RECT  0.227 10.416 2.401 10.728 ;
     RECT  2.401 9.552 2.408 10.728 ;
     RECT  0.181 17.136 2.408 17.16 ;
     RECT  2.408 2.148 2.512 32.412 ;
     RECT  2.512 2.418 2.704 32.142 ;
     RECT  2.704 9.072 3.521 10.872 ;
     RECT  3.013 0.528 3.733 0.552 ;
     RECT  3.625 1.728 3.826 1.752 ;
     RECT  2.704 3.312 3.877 3.336 ;
     RECT  3.521 9.072 3.971 10.008 ;
     RECT  3.733 0.096 4.057 0.552 ;
     RECT  3.826 1.68 4.057 1.752 ;
     RECT  3.971 9.552 4.169 10.008 ;
     RECT  4.057 0.096 4.307 1.752 ;
     RECT  4.129 7.968 4.499 7.992 ;
     RECT  3.877 3.312 4.525 3.48 ;
     RECT  4.169 9.984 4.565 10.008 ;
     RECT  4.525 2.736 4.597 3.48 ;
     RECT  2.704 5.376 4.777 5.4 ;
     RECT  4.777 5.376 4.892 5.544 ;
     RECT  2.704 6.72 4.892 6.744 ;
     RECT  4.307 0.096 5.141 1.176 ;
     RECT  5.132 9.408 5.173 9.432 ;
     RECT  5.173 8.976 5.219 9.432 ;
     RECT  4.597 2.736 5.317 4.008 ;
     RECT  4.892 5.376 5.317 6.744 ;
     RECT  5.219 8.976 5.389 9 ;
     RECT  5.141 1.152 5.413 1.176 ;
     RECT  5.317 2.736 5.429 6.744 ;
     RECT  5.413 1.152 5.509 1.752 ;
     RECT  5.173 10.848 5.569 10.872 ;
     RECT  5.389 8.496 5.605 9 ;
     RECT  5.569 10.416 5.713 10.872 ;
     RECT  5.509 1.152 5.753 2.28 ;
     RECT  5.141 0.096 6.005 0.12 ;
     RECT  5.497 30.24 6.073 30.264 ;
     RECT  6.073 30.096 6.145 30.264 ;
     RECT  5.429 3.36 6.253 6.744 ;
     RECT  6.253 3.36 6.257 6.888 ;
     RECT  2.704 17.136 6.353 17.16 ;
     RECT  6.257 4.512 6.389 6.888 ;
     RECT  5.605 7.968 6.389 9 ;
     RECT  5.753 1.728 6.421 2.28 ;
     RECT  6.257 3.36 6.421 3.432 ;
     RECT  6.145 29.664 6.433 30.264 ;
     RECT  6.253 0.528 6.445 0.696 ;
     RECT  6.389 4.512 6.469 9 ;
     RECT  6.469 4.512 6.473 9.144 ;
     RECT  6.433 29.664 6.805 30.6 ;
     RECT  6.421 1.728 6.853 3.432 ;
     RECT  6.805 28.704 6.865 30.6 ;
     RECT  6.865 28.704 6.937 30.696 ;
     RECT  7.109 0.096 7.193 0.12 ;
     RECT  6.937 28.704 7.369 30.84 ;
     RECT  6.853 1.104 7.388 3.432 ;
     RECT  6.473 4.512 7.388 6.888 ;
     RECT  7.261 32.304 7.429 32.328 ;
     RECT  7.388 1.104 7.525 6.888 ;
     RECT  7.525 0.288 7.549 6.888 ;
     RECT  6.473 7.968 7.549 9.144 ;
     RECT  7.441 33.696 7.693 33.72 ;
     RECT  7.429 32.304 7.762 32.52 ;
     RECT  7.549 0.288 7.808 9.144 ;
     RECT  5.713 10.368 7.808 10.872 ;
     RECT  6.353 16.56 7.808 17.16 ;
     RECT  7.369 28.704 7.808 30.888 ;
     RECT  7.762 32.304 7.808 32.568 ;
     RECT  7.808 0.288 7.996 32.568 ;
     RECT  7.693 33.648 8.051 33.72 ;
     RECT  7.996 0.288 8.104 32.52 ;
     RECT  8.104 0.288 8.156 10.824 ;
     RECT  8.104 15.984 8.381 16.008 ;
     RECT  8.156 0.192 8.435 10.824 ;
     RECT  8.051 33.696 8.435 33.72 ;
     RECT  8.104 14.256 8.561 14.28 ;
     RECT  8.435 1.728 8.669 10.488 ;
     RECT  8.435 0.192 8.821 0.648 ;
     RECT  8.104 32.304 8.915 32.52 ;
     RECT  8.821 0.144 9.011 0.648 ;
     RECT  8.915 32.304 9.157 32.472 ;
     RECT  9.349 34.416 9.397 34.44 ;
     RECT  9.397 34.32 9.497 34.44 ;
     RECT  9.497 34.32 9.529 34.392 ;
     RECT  9.011 0.192 9.58 0.648 ;
     RECT  9.529 33.648 9.683 34.392 ;
     RECT  9.58 0.192 9.875 0.552 ;
     RECT  8.104 27.216 9.889 30.888 ;
     RECT  9.157 31.92 9.889 32.472 ;
     RECT  9.98 22.752 10.067 22.776 ;
     RECT  9.673 26.208 10.067 26.232 ;
     RECT  9.683 33.648 10.067 33.672 ;
     RECT  8.669 1.728 10.097 1.752 ;
     RECT  9.889 27.216 10.249 32.472 ;
     RECT  10.177 22.224 10.261 22.248 ;
     RECT  10.105 23.856 10.285 23.88 ;
     RECT  10.097 1.728 10.309 1.8 ;
     RECT  8.669 2.88 10.309 10.488 ;
     RECT  10.213 18.528 10.361 18.552 ;
     RECT  10.261 13.056 10.403 13.08 ;
     RECT  10.249 26.256 10.477 32.472 ;
     RECT  10.309 1.728 10.501 10.488 ;
     RECT  9.875 0.192 10.597 0.36 ;
     RECT  10.285 23.856 10.693 24.504 ;
     RECT  10.597 0.096 10.739 0.36 ;
     RECT  10.477 26.256 10.739 32.088 ;
     RECT  10.739 0.096 10.819 0.264 ;
     RECT  10.693 23.856 10.825 25.128 ;
     RECT  10.819 0.144 10.883 0.264 ;
     RECT  10.883 0.144 10.979 0.168 ;
     RECT  10.501 1.728 11.036 10.728 ;
     RECT  11.036 1.728 11.077 10.872 ;
     RECT  11.077 33.648 11.257 33.672 ;
     RECT  11.077 1.728 11.315 11.16 ;
     RECT  10.825 23.568 11.365 25.128 ;
     RECT  11.257 33.072 11.365 33.672 ;
     RECT  11.365 23.568 11.905 25.272 ;
     RECT  10.739 26.256 11.905 31.464 ;
     RECT  11.315 1.728 11.909 2.376 ;
     RECT  11.905 23.568 12.013 31.464 ;
     RECT  12.013 23.568 12.044 31.896 ;
     RECT  12.037 0.144 12.092 0.168 ;
     RECT  12.044 23.328 12.121 31.896 ;
     RECT  11.365 33.072 12.121 33.72 ;
     RECT  12.092 0.144 12.179 0.552 ;
     RECT  12.049 19.104 12.179 19.128 ;
     RECT  12.121 22.8 12.205 33.72 ;
     RECT  11.909 1.728 12.22 2.328 ;
     RECT  12.205 23.568 12.661 33.72 ;
     RECT  12.179 0.144 12.869 0.168 ;
     RECT  12.869 0.096 12.953 0.168 ;
     RECT  11.315 3.36 13.093 11.16 ;
     RECT  12.661 23.568 13.139 34.392 ;
     RECT  12.953 0.144 13.189 0.168 ;
     RECT  12.22 1.728 13.208 1.752 ;
     RECT  13.093 2.88 13.208 11.16 ;
     RECT  12.121 14.784 13.208 14.808 ;
     RECT  8.104 17.136 13.208 17.16 ;
     RECT  12.661 18.816 13.208 18.84 ;
     RECT  12.301 21.408 13.208 21.432 ;
     RECT  13.139 23.568 13.208 32.616 ;
     RECT  13.208 1.728 13.385 32.616 ;
     RECT  13.385 2.418 13.504 32.616 ;
     RECT  13.139 33.6 13.573 34.392 ;
     RECT  13.189 0.144 13.669 0.36 ;
     RECT  13.573 33.6 13.673 34.44 ;
     RECT  13.673 33.6 13.925 33.624 ;
     RECT  13.504 23.424 14.209 32.616 ;
     RECT  13.504 2.784 14.249 11.208 ;
     RECT  14.209 23.424 14.387 33.096 ;
     RECT  13.669 0.144 14.533 1.272 ;
     RECT  14.249 2.784 14.533 11.16 ;
     RECT  14.533 0.144 14.579 11.16 ;
     RECT  14.579 1.152 14.825 11.16 ;
     RECT  14.579 0.144 15.001 0.168 ;
     RECT  14.869 34.368 15.289 34.392 ;
     RECT  15.001 0.096 15.293 0.168 ;
     RECT  14.825 1.152 15.293 1.272 ;
     RECT  14.825 2.304 15.329 11.16 ;
     RECT  15.289 33.648 15.347 34.392 ;
     RECT  14.387 23.424 15.469 32.52 ;
     RECT  15.347 33.648 15.469 33.72 ;
     RECT  15.329 2.832 15.589 11.16 ;
     RECT  15.293 1.152 15.635 1.176 ;
     RECT  15.293 0.096 16.057 0.12 ;
     RECT  16.261 0.144 16.547 0.168 ;
     RECT  15.469 23.424 16.597 33.72 ;
     RECT  16.597 23.424 16.691 34.392 ;
     RECT  15.589 3.312 16.801 11.16 ;
     RECT  16.357 1.728 16.804 1.752 ;
     RECT  16.804 1.728 16.837 1.8 ;
     RECT  16.801 3.216 16.837 11.16 ;
     RECT  16.837 1.728 17.075 11.16 ;
     RECT  16.691 23.424 17.157 33.144 ;
     RECT  17.157 23.424 17.267 33.096 ;
     RECT  16.691 34.368 17.363 34.392 ;
     RECT  16.549 0.576 17.525 0.6 ;
     RECT  17.893 0.144 18.083 0.168 ;
     RECT  17.075 1.728 18.241 1.848 ;
     RECT  17.075 2.88 18.241 11.16 ;
     RECT  18.205 33.648 18.373 33.672 ;
     RECT  18.373 33.552 18.421 33.672 ;
     RECT  18.241 1.728 18.608 11.16 ;
     RECT  13.504 17.136 18.608 17.16 ;
     RECT  13.504 21.408 18.608 21.432 ;
     RECT  17.267 23.424 18.608 32.28 ;
     RECT  18.421 33.552 18.611 34.392 ;
     RECT  18.608 1.728 18.661 32.412 ;
     RECT  18.611 34.32 18.802 34.392 ;
     RECT  18.661 1.728 18.904 32.568 ;
     RECT  18.802 34.32 18.995 34.44 ;
     RECT  18.995 34.32 19.043 34.344 ;
     RECT  18.904 23.424 19.069 32.568 ;
     RECT  19.069 23.424 19.475 33.096 ;
     RECT  19.897 33.648 20.149 33.672 ;
     RECT  18.904 1.728 20.243 11.16 ;
     RECT  20.243 1.728 20.252 1.8 ;
     RECT  20.252 1.104 20.339 1.8 ;
     RECT  20.005 0.096 20.629 0.12 ;
     RECT  18.904 17.136 20.833 17.16 ;
     RECT  19.475 23.424 21.02 32.472 ;
     RECT  20.257 12.768 21.049 12.792 ;
     RECT  20.339 1.728 21.053 1.8 ;
     RECT  21.02 23.424 21.107 32.568 ;
     RECT  20.149 33.648 21.221 34.392 ;
     RECT  20.629 0.096 21.299 0.408 ;
     RECT  21.299 0.144 21.301 0.408 ;
     RECT  21.301 0.144 21.305 1.176 ;
     RECT  21.305 1.104 21.395 1.176 ;
     RECT  21.049 12.528 21.395 12.792 ;
     RECT  20.243 3.024 21.493 11.16 ;
     RECT  21.493 2.256 21.701 11.16 ;
     RECT  21.395 1.152 21.737 1.176 ;
     RECT  18.904 21.408 21.781 21.432 ;
     RECT  21.395 12.768 21.923 12.792 ;
     RECT  21.781 21.408 21.989 21.768 ;
     RECT  21.989 21.408 22.057 21.672 ;
     RECT  22.057 20.928 22.177 21.672 ;
     RECT  21.221 33.648 22.213 34.44 ;
     RECT  22.213 33.6 22.385 34.44 ;
     RECT  22.301 0.096 22.417 0.12 ;
     RECT  21.701 2.88 22.637 11.16 ;
     RECT  22.417 0.096 22.643 0.552 ;
     RECT  21.107 23.424 22.777 32.472 ;
     RECT  22.637 3.024 22.889 11.16 ;
     RECT  22.849 1.728 22.933 1.752 ;
     RECT  22.777 23.088 23.123 32.472 ;
     RECT  22.177 20.928 23.281 20.952 ;
     RECT  22.643 0.096 23.545 0.36 ;
     RECT  23.123 23.088 23.569 32.412 ;
     RECT  22.889 3.024 23.653 10.824 ;
     RECT  23.545 0.192 23.749 0.36 ;
     RECT  22.385 33.648 23.897 34.44 ;
     RECT  23.653 2.304 24.001 10.824 ;
     RECT  24.001 2.304 24.008 10.92 ;
     RECT  21.877 15.744 24.008 15.768 ;
     RECT  20.833 17.136 24.008 17.496 ;
     RECT  20.245 19.824 24.008 19.848 ;
     RECT  23.281 20.928 24.008 21.432 ;
     RECT  23.569 22.464 24.008 32.412 ;
     RECT  24.008 2.148 24.037 32.412 ;
     RECT  24.037 2.016 24.133 32.412 ;
     RECT  24.133 1.728 24.236 32.412 ;
     RECT  24.236 1.728 24.304 32.616 ;
     RECT  24.304 22.464 24.323 32.616 ;
     RECT  23.749 0.192 24.325 0.456 ;
     RECT  23.897 33.648 24.419 34.392 ;
     RECT  24.419 33.648 24.467 34.296 ;
     RECT  24.325 0.192 24.469 0.504 ;
     RECT  24.304 1.728 24.469 11.4 ;
     RECT  24.469 0.192 24.481 11.4 ;
     RECT  24.481 0.384 24.515 11.4 ;
     RECT  24.467 33.648 24.515 34.104 ;
     RECT  24.515 1.104 24.653 10.488 ;
     RECT  24.653 1.104 24.659 5.88 ;
     RECT  24.659 1.728 24.977 5.88 ;
     RECT  24.515 33.648 25.139 33.672 ;
     RECT  24.977 3.216 25.693 5.88 ;
     RECT  24.653 6.96 25.693 10.488 ;
     RECT  24.977 1.728 25.769 2.184 ;
     RECT  24.304 17.136 25.873 17.496 ;
     RECT  25.82 0.528 25.907 0.552 ;
     RECT  25.513 34.416 25.907 34.44 ;
     RECT  25.693 3.216 25.945 10.488 ;
     RECT  24.304 19.824 26.245 21.432 ;
     RECT  24.323 22.464 26.291 32.52 ;
     RECT  25.945 3.168 26.293 10.488 ;
     RECT  26.293 2.832 26.38 10.488 ;
     RECT  25.769 1.728 26.921 1.752 ;
     RECT  26.876 0.528 26.989 0.552 ;
     RECT  26.38 2.88 27.155 10.488 ;
     RECT  26.291 22.464 27.277 32.472 ;
     RECT  26.593 33.648 27.277 33.672 ;
     RECT  27.277 22.464 27.443 33.672 ;
     RECT  25.369 18.528 27.637 18.552 ;
     RECT  27.155 3.168 27.685 10.488 ;
     RECT  26.989 0.528 27.923 1.176 ;
     RECT  27.443 33.6 28.115 33.672 ;
     RECT  26.449 12.768 28.349 12.792 ;
     RECT  27.923 0.528 28.357 0.552 ;
     RECT  28.349 12.768 28.433 13.704 ;
     RECT  28.357 0.096 28.469 0.552 ;
     RECT  27.685 3.168 28.537 10.872 ;
     RECT  28.115 33.6 28.595 33.624 ;
     RECT  28.537 2.304 28.681 10.872 ;
     RECT  28.681 2.304 28.7 10.968 ;
     RECT  27.443 22.464 28.717 32.472 ;
     RECT  28.7 1.68 28.787 10.968 ;
     RECT  28.787 1.728 28.789 10.968 ;
     RECT  28.789 1.728 29.081 11.448 ;
     RECT  28.469 0.144 29.221 0.552 ;
     RECT  28.717 22.464 29.363 33.144 ;
     RECT  29.081 1.776 29.408 11.448 ;
     RECT  28.433 12.768 29.408 12.792 ;
     RECT  24.304 15.744 29.408 15.768 ;
     RECT  25.873 16.848 29.408 17.496 ;
     RECT  27.637 18.48 29.408 18.552 ;
     RECT  26.245 19.536 29.408 21.432 ;
     RECT  29.363 22.464 29.408 32.664 ;
     RECT  29.408 1.776 29.585 32.664 ;
     RECT  29.221 0.144 29.701 0.744 ;
     RECT  29.585 2.208 29.704 32.664 ;
     RECT  29.581 33.648 29.939 33.672 ;
     RECT  29.701 0.096 30.229 0.744 ;
     RECT  30.229 0.096 30.371 1.176 ;
     RECT  29.704 22.464 30.481 32.664 ;
     RECT  29.704 2.208 30.949 10.968 ;
     RECT  30.949 2.208 31.013 11.496 ;
     RECT  30.371 0.096 31.097 0.6 ;
     RECT  31.097 0.144 31.235 0.6 ;
     RECT  31.235 0.144 31.277 0.408 ;
     RECT  31.013 1.728 31.277 11.496 ;
     RECT  31.277 0.144 31.283 0.312 ;
     RECT  30.373 34.416 31.379 34.44 ;
     RECT  31.277 1.728 31.601 10.968 ;
     RECT  31.601 2.832 31.66 10.968 ;
     RECT  30.481 22.464 31.885 33.192 ;
     RECT  31.283 0.144 31.907 0.216 ;
     RECT  29.704 19.536 32.069 21.432 ;
     RECT  31.885 22.464 32.147 33.624 ;
     RECT  31.601 1.728 32.213 1.752 ;
     RECT  29.704 16.848 32.245 17.496 ;
     RECT  29.704 18.48 32.245 18.552 ;
     RECT  32.069 19.536 32.245 19.56 ;
     RECT  31.957 14.736 32.321 14.76 ;
     RECT  32.147 33.6 32.339 33.624 ;
     RECT  29.704 12.768 32.485 12.792 ;
     RECT  32.485 0.576 32.533 0.6 ;
     RECT  32.245 16.848 32.537 19.56 ;
     RECT  32.485 12.768 32.627 13.08 ;
     RECT  32.537 18.48 32.627 19.56 ;
     RECT  32.533 0.576 32.717 1.272 ;
     RECT  32.717 1.152 32.723 1.272 ;
     RECT  31.66 3.168 32.725 10.968 ;
     RECT  32.677 33.648 32.749 34.344 ;
     RECT  32.749 33.648 32.833 34.44 ;
     RECT  32.833 33.648 33.107 34.344 ;
     RECT  32.725 2.736 33.221 10.968 ;
     RECT  29.704 15.744 33.445 15.768 ;
     RECT  33.301 0.144 33.491 0.168 ;
     RECT  33.221 2.88 33.493 10.968 ;
     RECT  32.723 1.2 33.613 1.272 ;
     RECT  33.445 15.408 33.653 15.768 ;
     RECT  33.613 1.2 33.733 1.752 ;
     RECT  33.733 1.152 33.833 1.752 ;
     RECT  33.833 1.2 33.875 1.752 ;
     RECT  33.107 34.128 33.875 34.344 ;
     RECT  32.147 22.464 33.893 32.376 ;
     RECT  33.875 1.728 34.009 1.752 ;
     RECT  33.875 34.224 34.067 34.248 ;
     RECT  34.009 1.728 34.085 1.848 ;
     RECT  34.085 1.776 34.453 1.848 ;
     RECT  33.493 2.88 34.453 11.448 ;
     RECT  32.627 18.48 34.501 18.552 ;
     RECT  32.627 19.536 34.501 19.56 ;
     RECT  33.893 22.464 34.621 32.472 ;
     RECT  34.621 22.464 34.657 32.616 ;
     RECT  34.405 0.096 34.789 0.12 ;
     RECT  34.453 1.776 34.808 11.448 ;
     RECT  32.627 12.768 34.808 12.792 ;
     RECT  33.653 15.744 34.808 15.768 ;
     RECT  32.537 16.848 34.808 17.496 ;
     RECT  34.501 18.48 34.808 19.56 ;
     RECT  32.069 20.592 34.808 21.432 ;
     RECT  34.657 22.464 34.808 33.096 ;
     RECT  34.789 0.096 34.885 0.168 ;
     RECT  34.885 0.096 34.981 0.456 ;
     RECT  34.808 1.776 35.077 33.096 ;
     RECT  35.077 1.728 35.104 33.096 ;
     RECT  34.981 0.096 35.123 0.504 ;
     RECT  35.104 22.464 35.123 33.096 ;
     RECT  35.123 0.144 35.557 0.504 ;
     RECT  35.557 34.368 35.605 34.392 ;
     RECT  35.605 34.272 35.747 34.392 ;
     RECT  35.123 22.464 36.085 31.992 ;
     RECT  35.123 33.072 36.085 33.096 ;
     RECT  35.557 0.144 36.092 0.6 ;
     RECT  35.104 1.728 36.092 10.968 ;
     RECT  35.747 34.272 36.133 34.296 ;
     RECT  35.104 20.544 36.137 21.432 ;
     RECT  36.092 0.144 36.179 10.968 ;
     RECT  36.179 1.152 36.419 10.968 ;
     RECT  36.419 1.152 36.425 1.8 ;
     RECT  36.179 0.144 36.467 0.168 ;
     RECT  36.085 22.464 36.659 33.096 ;
     RECT  35.104 15.408 36.661 15.768 ;
     RECT  36.133 34.176 36.853 34.296 ;
     RECT  36.853 34.176 36.889 34.392 ;
     RECT  36.889 33.648 37.043 34.392 ;
     RECT  36.137 20.592 37.1 21.432 ;
     RECT  36.661 14.832 37.213 15.768 ;
     RECT  35.104 16.848 37.213 17.496 ;
     RECT  37.213 14.832 37.297 17.496 ;
     RECT  37.1 19.824 37.333 21.432 ;
     RECT  36.425 1.152 37.381 1.752 ;
     RECT  37.381 0.576 37.433 1.752 ;
     RECT  37.433 0.576 37.505 0.6 ;
     RECT  36.659 22.464 37.717 32.52 ;
     RECT  37.043 33.648 37.717 33.672 ;
     RECT  37.297 14.832 37.721 15.768 ;
     RECT  36.419 3.168 37.753 10.968 ;
     RECT  37.333 19.824 37.861 21.48 ;
     RECT  37.717 22.464 37.907 33.672 ;
     RECT  37.753 2.784 37.969 10.968 ;
     RECT  35.104 12.768 38.099 12.792 ;
     RECT  37.433 1.728 38.149 1.752 ;
     RECT  37.969 2.736 38.149 10.968 ;
     RECT  38.149 1.728 38.153 10.968 ;
     RECT  37.907 22.464 38.195 32.472 ;
     RECT  38.153 1.824 38.233 10.968 ;
     RECT  37.907 33.648 38.291 33.672 ;
     RECT  37.645 0.096 38.305 0.12 ;
     RECT  37.861 19.632 38.533 21.48 ;
     RECT  38.195 22.464 38.533 32.376 ;
     RECT  38.233 2.736 38.689 10.968 ;
     RECT  38.533 19.632 38.873 32.376 ;
     RECT  38.689 2.736 39.059 11.112 ;
     RECT  37.721 15.744 39.061 15.768 ;
     RECT  39.068 0.528 39.155 0.552 ;
     RECT  39.205 1.728 39.265 1.752 ;
     RECT  39.059 2.736 39.265 10.68 ;
     RECT  35.104 18.48 39.337 18.552 ;
     RECT  38.873 19.632 39.337 19.656 ;
     RECT  38.873 20.736 39.553 32.376 ;
     RECT  39.265 1.728 39.589 10.68 ;
     RECT  39.553 20.736 39.733 32.472 ;
     RECT  39.061 15.744 39.949 15.816 ;
     RECT  39.589 0.576 40.021 10.68 ;
     RECT  40.021 0.576 40.057 10.776 ;
     RECT  39.733 20.736 40.093 32.568 ;
     RECT  40.057 0.576 40.208 11.016 ;
     RECT  39.949 14.784 40.208 15.816 ;
     RECT  37.297 16.848 40.208 17.496 ;
     RECT  39.337 18.48 40.208 19.656 ;
     RECT  40.093 20.736 40.208 32.664 ;
     RECT  40.208 0.576 40.357 32.664 ;
     RECT  40.453 34.176 40.501 34.2 ;
     RECT  40.357 0.144 40.504 32.664 ;
     RECT  40.501 34.176 40.669 34.392 ;
     RECT  40.504 0.144 40.834 11.016 ;
     RECT  40.669 33.648 40.849 34.392 ;
     RECT  40.834 0.096 40.997 11.016 ;
     RECT  40.997 0.096 41.027 0.6 ;
     RECT  40.504 20.928 41.029 32.664 ;
     RECT  40.849 33.648 41.029 34.44 ;
     RECT  41.027 0.096 41.123 0.216 ;
     RECT  41.029 20.928 41.363 34.44 ;
     RECT  40.504 15.744 41.429 17.496 ;
     RECT  41.363 33.648 41.459 34.44 ;
     RECT  40.997 1.728 41.537 11.016 ;
     RECT  41.459 33.648 41.843 33.672 ;
     RECT  41.537 2.88 42.037 11.016 ;
     RECT  41.429 15.744 42.073 15.816 ;
     RECT  41.537 1.728 42.149 1.752 ;
     RECT  42.073 14.832 42.157 15.816 ;
     RECT  41.123 0.096 42.325 0.12 ;
     RECT  42.037 2.88 42.509 11.352 ;
     RECT  40.504 19.632 42.668 19.656 ;
     RECT  42.509 2.88 42.689 11.016 ;
     RECT  42.469 34.416 42.899 34.44 ;
     RECT  42.668 19.632 42.908 19.944 ;
     RECT  41.363 20.928 42.908 32.472 ;
     RECT  42.829 14.256 42.913 14.28 ;
     RECT  42.908 19.632 42.995 32.472 ;
     RECT  42.995 19.632 43.139 19.944 ;
     RECT  42.689 2.88 43.148 10.92 ;
     RECT  42.995 20.928 43.153 32.472 ;
     RECT  43.148 2.832 43.229 10.92 ;
     RECT  42.325 0.096 43.237 0.216 ;
     RECT  43.141 1.248 43.237 1.272 ;
     RECT  43.153 20.928 43.657 32.568 ;
     RECT  43.009 33.648 43.657 33.72 ;
     RECT  43.237 0.096 43.667 1.272 ;
     RECT  42.157 15.744 43.693 15.816 ;
     RECT  41.429 16.848 43.693 17.496 ;
     RECT  43.229 2.832 43.741 10.872 ;
     RECT  43.693 15.744 43.777 17.496 ;
     RECT  43.777 16.848 43.945 17.496 ;
     RECT  40.504 18.48 43.945 18.504 ;
     RECT  43.657 20.928 43.955 33.72 ;
     RECT  43.945 16.848 44.051 18.504 ;
     RECT  43.741 3.312 44.269 10.872 ;
     RECT  43.667 0.096 44.309 0.648 ;
     RECT  43.793 1.728 44.344 1.752 ;
     RECT  44.344 1.728 44.453 1.8 ;
     RECT  44.309 0.144 44.773 0.648 ;
     RECT  44.453 1.728 44.773 1.752 ;
     RECT  43.955 33.648 44.773 33.72 ;
     RECT  44.269 3.312 44.845 11.448 ;
     RECT  44.773 0.144 44.857 1.752 ;
     RECT  44.845 3.264 44.965 11.448 ;
     RECT  44.773 33.648 45.203 34.392 ;
     RECT  44.857 1.728 45.608 1.752 ;
     RECT  44.965 3.024 45.608 11.448 ;
     RECT  43.777 15.744 45.608 15.768 ;
     RECT  44.051 16.848 45.608 17.496 ;
     RECT  44.051 18.48 45.608 18.504 ;
     RECT  43.139 19.632 45.608 19.656 ;
     RECT  43.955 20.928 45.608 32.472 ;
     RECT  45.608 1.728 45.637 32.472 ;
     RECT  44.857 0.144 45.721 0.6 ;
     RECT  45.637 1.728 45.904 33.384 ;
     RECT  45.721 0.144 46.037 0.264 ;
     RECT  46.037 0.144 46.115 0.216 ;
     RECT  45.904 3.312 46.181 10.872 ;
     RECT  46.181 3.36 46.613 10.872 ;
     RECT  45.904 20.928 46.717 33.384 ;
     RECT  45.203 34.368 46.717 34.392 ;
     RECT  46.717 20.928 46.835 34.392 ;
     RECT  46.835 33.648 46.931 34.392 ;
     RECT  45.904 13.632 46.981 13.656 ;
     RECT  45.904 1.728 47.036 1.752 ;
     RECT  45.904 14.784 47.117 15.768 ;
     RECT  47.036 1.104 47.123 1.752 ;
     RECT  46.981 13.488 47.189 13.656 ;
     RECT  46.931 34.368 47.219 34.392 ;
     RECT  47.189 13.632 47.261 13.656 ;
     RECT  45.904 18.48 47.324 18.504 ;
     RECT  45.904 19.632 47.324 19.752 ;
     RECT  47.123 1.728 47.461 1.752 ;
     RECT  47.461 1.728 47.761 2.328 ;
     RECT  46.613 3.36 47.761 10.824 ;
     RECT  47.324 18.48 48.229 19.752 ;
     RECT  46.835 20.928 48.229 32.472 ;
     RECT  48.229 34.416 48.277 34.44 ;
     RECT  48.277 34.32 48.47 34.44 ;
     RECT  46.609 0.096 48.481 0.12 ;
     RECT  47.761 1.728 48.563 10.824 ;
     RECT  48.481 0.096 48.565 0.6 ;
     RECT  48.47 34.368 48.755 34.392 ;
     RECT  48.229 18.48 48.845 32.472 ;
     RECT  48.845 19.728 48.917 32.472 ;
     RECT  48.563 3.36 48.985 10.824 ;
     RECT  48.917 19.728 48.989 21.48 ;
     RECT  48.565 0.096 49.061 0.168 ;
     RECT  48.563 1.728 49.265 2.328 ;
     RECT  49.061 0.144 49.523 0.168 ;
     RECT  48.985 3.36 49.529 11.304 ;
     RECT  48.989 19.728 49.853 19.752 ;
     RECT  49.265 1.152 49.993 2.328 ;
     RECT  49.993 1.104 50.197 2.328 ;
     RECT  49.529 3.36 50.197 10.488 ;
     RECT  50.149 33.6 50.461 33.624 ;
     RECT  50.461 33.6 50.719 33.672 ;
     RECT  50.719 33.648 50.771 33.672 ;
     RECT  50.713 0.096 50.797 0.12 ;
     RECT  48.917 22.464 50.917 32.472 ;
     RECT  50.917 22.464 50.965 32.568 ;
     RECT  50.197 1.104 51.008 10.488 ;
     RECT  47.117 15.744 51.008 15.768 ;
     RECT  45.904 16.848 51.008 17.496 ;
     RECT  48.845 18.48 51.008 18.504 ;
     RECT  48.989 20.928 51.008 21.48 ;
     RECT  50.965 22.464 51.008 32.664 ;
     RECT  51.008 1.104 51.155 32.664 ;
     RECT  50.869 34.368 51.155 34.392 ;
     RECT  51.155 1.2 51.185 32.664 ;
     RECT  51.185 1.728 51.304 32.664 ;
     RECT  51.304 22.464 51.721 32.664 ;
     RECT  51.721 22.464 51.793 33.096 ;
     RECT  51.793 22.464 51.923 33.672 ;
     RECT  51.301 0.144 51.973 0.168 ;
     RECT  51.304 1.728 51.977 10.488 ;
     RECT  51.977 2.88 52.019 10.488 ;
     RECT  51.304 18.48 52.085 18.504 ;
     RECT  51.923 22.464 52.307 33.096 ;
     RECT  51.973 0.096 52.325 0.168 ;
     RECT  52.325 0.096 52.409 0.6 ;
     RECT  52.019 2.88 52.547 7.992 ;
     RECT  52.547 3.312 53.017 7.992 ;
     RECT  52.019 8.976 53.017 10.488 ;
     RECT  52.645 34.368 53.027 34.392 ;
     RECT  53.017 3.312 53.053 10.488 ;
     RECT  52.409 0.096 53.075 0.216 ;
     RECT  53.053 3.312 53.093 10.872 ;
     RECT  53.075 0.192 53.123 0.216 ;
     RECT  53.093 10.416 53.129 10.872 ;
     RECT  53.129 10.464 53.137 10.872 ;
     RECT  51.977 1.728 53.413 1.8 ;
     RECT  53.093 3.312 53.453 9.432 ;
     RECT  53.413 1.728 53.477 1.848 ;
     RECT  53.453 3.312 53.561 7.992 ;
     RECT  53.137 10.464 53.741 10.728 ;
     RECT  53.453 8.976 53.777 9.432 ;
     RECT  52.307 22.464 53.809 32.472 ;
     RECT  51.304 16.848 53.891 17.496 ;
     RECT  53.477 1.728 53.893 1.944 ;
     RECT  53.561 3.312 54.245 5.88 ;
     RECT  53.845 0.528 54.373 0.552 ;
     RECT  53.809 22.464 54.421 33.048 ;
     RECT  53.893 1.728 54.457 2.328 ;
     RECT  54.245 3.312 54.457 5.736 ;
     RECT  54.457 1.728 54.461 5.736 ;
     RECT  54.373 0.528 54.469 0.6 ;
     RECT  54.229 34.368 54.515 34.392 ;
     RECT  53.561 6.864 54.517 7.992 ;
     RECT  53.777 8.976 54.517 9.336 ;
     RECT  54.469 0.096 54.605 0.6 ;
     RECT  54.517 6.864 54.673 9.336 ;
     RECT  54.605 0.528 54.713 0.6 ;
     RECT  53.891 17.472 54.851 17.496 ;
     RECT  54.713 0.528 54.899 0.552 ;
     RECT  54.461 1.728 55.145 5.448 ;
     RECT  55.145 4.944 55.429 5.448 ;
     RECT  55.429 4.944 55.525 5.688 ;
     RECT  54.673 6.72 55.525 9.336 ;
     RECT  54.997 34.416 55.525 34.44 ;
     RECT  55.525 34.368 55.859 34.44 ;
     RECT  55.145 1.728 56.293 3.96 ;
     RECT  55.525 4.944 56.293 9.336 ;
     RECT  56.293 1.728 56.408 9.336 ;
     RECT  53.741 10.464 56.408 10.488 ;
     RECT  51.304 15.744 56.408 15.768 ;
     RECT  51.304 20.928 56.408 21.432 ;
     RECT  54.421 22.464 56.408 33.096 ;
     RECT  55.859 34.368 56.435 34.392 ;
     RECT  56.408 1.728 56.531 33.096 ;
     RECT  56.531 1.728 56.704 32.52 ;
     RECT  56.704 27.84 56.765 32.52 ;
     RECT  56.677 0.384 56.773 0.408 ;
     RECT  56.753 34.272 56.773 34.296 ;
     RECT  56.773 0.192 56.818 0.408 ;
     RECT  56.773 34.032 56.837 34.296 ;
     RECT  56.765 27.84 56.845 32.472 ;
     RECT  56.837 34.032 56.867 34.152 ;
     RECT  56.704 6.144 56.873 8.472 ;
     RECT  56.867 34.032 56.915 34.056 ;
     RECT  56.818 0.096 56.917 0.408 ;
     RECT  56.704 1.728 56.945 5.016 ;
     RECT  56.945 1.728 56.965 4.68 ;
     RECT  56.917 0.144 57.011 0.408 ;
     RECT  56.965 1.392 57.061 4.68 ;
     RECT  56.845 27.888 57.305 32.472 ;
     RECT  56.704 22.464 57.341 26.808 ;
     RECT  57.061 0.816 57.491 4.68 ;
     RECT  56.873 6.144 57.491 7.992 ;
     RECT  57.491 6.144 57.587 6.312 ;
     RECT  57.341 22.464 57.587 26.664 ;
     RECT  57.491 7.392 57.629 7.992 ;
     RECT  57.491 3.936 57.845 4.68 ;
     RECT  57.829 34.368 57.925 34.392 ;
     RECT  57.925 34.272 58.019 34.392 ;
     RECT  58.019 34.272 58.115 34.296 ;
     RECT  57.845 3.936 58.133 4.104 ;
     RECT  58.237 5.136 58.457 5.16 ;
     RECT  57.587 6.288 58.493 6.312 ;
     RECT  57.629 7.392 58.525 7.656 ;
     RECT  58.133 3.936 58.529 3.96 ;
     RECT  57.491 0.816 58.589 2.952 ;
     RECT  58.589 0.144 58.633 2.952 ;
     RECT  58.525 6.864 58.817 7.656 ;
     RECT  57.305 28.08 58.921 32.472 ;
     RECT  58.921 27.888 59.245 32.472 ;
     RECT  58.633 0.048 59.317 2.952 ;
     RECT  59.245 27.888 59.569 33.096 ;
     RECT  59.569 27.888 59.785 33.672 ;
     RECT  59.785 27.888 59.795 33.72 ;
     RECT  59.795 27.888 59.861 32.472 ;
     RECT  57.587 23.424 60.037 26.664 ;
     RECT  59.861 27.888 60.037 30.936 ;
     RECT  58.817 6.864 60.221 6.888 ;
     RECT  59.795 33.648 60.325 33.72 ;
     RECT  60.073 4.512 60.581 4.536 ;
     RECT  59.317 0.048 60.653 3.096 ;
     RECT  60.037 23.424 60.653 30.936 ;
     RECT  59.861 31.92 60.829 32.472 ;
     RECT  60.325 33.648 60.829 34.344 ;
     RECT  60.829 31.92 61.139 34.344 ;
     RECT  61.139 33.6 61.141 34.344 ;
     RECT  60.653 0.048 61.808 2.904 ;
     RECT  56.704 10.464 61.808 10.488 ;
     RECT  60.653 23.424 61.808 23.448 ;
     RECT  60.653 24.48 61.808 30.936 ;
     RECT  61.139 31.92 61.808 32.616 ;
     RECT  61.808 0.048 61.907 32.616 ;
     RECT  61.907 0.048 62.104 32.568 ;
     RECT  62.104 32.544 62.137 32.568 ;
     RECT  61.141 33.6 62.149 34.392 ;
     RECT  62.104 0.048 62.237 2.856 ;
     RECT  62.104 25.008 62.489 25.56 ;
     RECT  62.237 0.048 62.705 2.616 ;
     RECT  62.104 28.272 62.993 30.936 ;
     RECT  62.705 0.048 63.029 2.088 ;
     RECT  62.993 28.272 63.065 30.84 ;
     RECT  62.149 33.6 63.133 34.44 ;
     RECT  63.029 0.048 63.245 0.072 ;
     RECT  63.029 1.44 63.317 2.088 ;
     RECT  63.065 28.416 63.317 30.84 ;
     RECT  63.313 31.92 63.421 31.944 ;
     RECT  63.133 33.072 63.421 34.44 ;
     RECT  63.317 1.968 63.569 2.088 ;
     RECT  63.569 1.968 63.785 1.992 ;
     RECT  62.489 25.536 63.857 25.56 ;
     RECT  63.421 31.92 63.923 34.44 ;
     RECT  63.317 30.288 63.929 30.84 ;
     RECT  63.923 33.648 64.019 34.44 ;
     RECT  63.317 28.416 64.433 29.208 ;
     RECT  64.019 34.416 64.499 34.44 ;
     RECT  63.923 31.92 64.691 32.472 ;
     RECT  64.691 32.352 64.897 32.472 ;
     RECT  64.897 32.352 64.979 32.52 ;
     RECT  63.929 30.288 65.005 30.456 ;
     RECT  64.979 32.4 65.171 32.52 ;
     RECT  65.171 32.4 65.225 32.472 ;
     RECT  65.225 32.4 65.297 32.424 ;
     RECT  65.005 30.288 65.369 31.32 ;
     RECT  64.433 28.8 65.621 29.208 ;
     RECT  65.369 30.384 65.657 31.32 ;
     RECT  65.657 30.384 66.197 30.408 ;
     RECT  65.621 28.8 66.305 28.824 ;
     RECT  62.104 26.64 66.521 26.664 ;
    LAYER M5 ;
     RECT  3.792 0.016 60.168 0.371 ;
     RECT  62.448 0.229 62.472 0.371 ;
     RECT  3.792 0.371 60.072 0.563 ;
     RECT  3.792 0.563 38.184 1.763 ;
     RECT  39.216 0.563 60.072 1.763 ;
     RECT  4.752 1.763 38.184 1.859 ;
     RECT  39.312 1.763 60.072 1.859 ;
     RECT  2.4 2.137 2.52 2.151 ;
     RECT  61.8 2.137 61.92 2.151 ;
     RECT  39.408 1.859 60.072 2.195 ;
     RECT  39.408 2.195 58.344 2.483 ;
     RECT  39.408 2.483 57.384 2.869 ;
     RECT  59.808 2.195 59.832 3.011 ;
     RECT  39.216 2.869 57.384 3.157 ;
     RECT  4.752 1.859 37.992 3.349 ;
     RECT  39.168 3.157 57.384 3.349 ;
     RECT  4.752 3.349 57.384 3.877 ;
     RECT  4.752 3.877 57.48 4.019 ;
     RECT  5.52 4.019 57.48 4.645 ;
     RECT  5.52 4.645 57.576 5.365 ;
     RECT  4.944 5.365 57.576 6.419 ;
     RECT  4.464 6.709 4.488 8.003 ;
     RECT  5.52 6.419 57.576 8.965 ;
     RECT  5.184 8.965 57.576 9.731 ;
     RECT  17.856 9.731 33.528 9.779 ;
     RECT  2.4 2.151 2.712 9.973 ;
     RECT  3.936 9.061 3.96 9.973 ;
     RECT  2.4 9.973 3.96 10.019 ;
     RECT  25.68 9.779 33.528 10.115 ;
     RECT  26.544 10.115 33.528 10.259 ;
     RECT  34.512 9.731 57.576 10.259 ;
     RECT  26.928 10.259 33.528 10.499 ;
     RECT  5.184 9.731 16.872 10.835 ;
     RECT  2.4 10.019 3.48 10.883 ;
     RECT  5.184 10.835 8.376 10.883 ;
     RECT  17.856 9.779 24.648 10.883 ;
     RECT  32.16 10.499 33.528 10.883 ;
     RECT  17.856 10.883 21.672 11.171 ;
     RECT  9.36 10.835 16.872 11.219 ;
     RECT  26.928 10.499 31.08 11.459 ;
     RECT  32.256 10.883 33.528 11.459 ;
     RECT  26.928 11.459 30.984 11.507 ;
     RECT  17.856 11.171 21.576 12.757 ;
     RECT  34.512 10.259 47.016 13.523 ;
     RECT  5.52 10.883 8.376 14.291 ;
     RECT  34.512 13.523 46.872 14.291 ;
     RECT  34.512 14.291 42.12 14.867 ;
     RECT  32.256 11.459 33.48 15.443 ;
     RECT  34.512 14.867 36.072 15.443 ;
     RECT  5.52 14.291 8.28 16.019 ;
     RECT  43.728 14.291 46.872 16.019 ;
     RECT  37.248 14.867 41.496 16.595 ;
     RECT  48 10.259 57.576 16.883 ;
     RECT  0.192 10.309 0.216 17.171 ;
     RECT  44.112 16.019 46.872 17.365 ;
     RECT  17.856 12.757 21.912 17.411 ;
     RECT  54.816 16.883 57.576 17.507 ;
     RECT  44.112 17.365 47.016 18.181 ;
     RECT  26.928 11.507 30.648 18.515 ;
     RECT  32.256 15.443 32.52 19.093 ;
     RECT  44.016 18.181 47.016 19.285 ;
     RECT  48 16.883 53.784 19.285 ;
     RECT  32.256 19.093 32.616 19.427 ;
     RECT  34.512 15.443 35.112 19.427 ;
     RECT  26.928 18.515 27.096 19.525 ;
     RECT  37.344 16.595 41.496 19.667 ;
     RECT  37.344 19.667 37.368 19.813 ;
     RECT  44.016 19.285 53.784 19.909 ;
     RECT  28.272 18.515 30.648 20.579 ;
     RECT  32.496 19.427 32.616 20.581 ;
     RECT  55.008 17.507 57.576 20.963 ;
     RECT  22.896 10.883 24.648 20.965 ;
     RECT  38.496 19.667 41.496 21.011 ;
     RECT  37.152 19.813 37.368 21.013 ;
     RECT  32.496 20.581 32.76 21.061 ;
     RECT  56.112 20.963 57.576 21.443 ;
     RECT  36.384 21.013 37.368 21.491 ;
     RECT  17.856 17.411 21.816 21.637 ;
     RECT  22.896 20.965 25.272 21.637 ;
     RECT  17.856 21.637 25.272 21.779 ;
     RECT  38.544 21.011 41.496 21.971 ;
     RECT  56.304 21.443 57.576 22.499 ;
     RECT  38.976 21.971 41.496 22.547 ;
     RECT  39.168 22.547 41.496 23.075 ;
     RECT  56.304 22.499 56.712 23.123 ;
     RECT  32.496 21.061 33.336 23.797 ;
     RECT  36.384 21.491 37.176 25.045 ;
     RECT  34.8 19.427 35.112 25.093 ;
     RECT  36.384 25.045 37.32 25.093 ;
     RECT  34.8 25.093 37.32 25.235 ;
     RECT  42.72 19.909 53.784 25.475 ;
     RECT  43.056 25.475 53.784 25.621 ;
     RECT  55.008 20.963 55.032 25.621 ;
     RECT  36.768 25.235 37.32 25.715 ;
     RECT  43.056 25.621 55.032 25.715 ;
     RECT  36.96 25.715 37.32 25.717 ;
     RECT  22.128 21.779 25.272 25.957 ;
     RECT  26.256 19.525 27.096 25.957 ;
     RECT  36.96 25.717 38.232 26.101 ;
     RECT  39.264 23.075 41.496 26.101 ;
     RECT  9.36 11.219 13.512 26.149 ;
     RECT  14.544 11.219 16.872 26.149 ;
     RECT  32.256 23.797 33.336 26.149 ;
     RECT  22.128 25.957 27.096 26.243 ;
     RECT  28.272 20.579 29.712 26.243 ;
     RECT  44.112 25.715 55.032 26.243 ;
     RECT  61.8 2.151 62.112 26.245 ;
     RECT  31.296 26.149 33.336 26.293 ;
     RECT  31.296 26.293 33.72 26.437 ;
     RECT  34.8 25.235 35.736 26.437 ;
     RECT  29.4 26.243 29.712 26.629 ;
     RECT  31.296 26.437 35.736 26.629 ;
     RECT  17.856 21.779 20.904 26.725 ;
     RECT  22.128 26.243 25.272 26.725 ;
     RECT  36.96 26.101 41.496 26.725 ;
     RECT  54.96 26.243 55.032 26.725 ;
     RECT  56.4 23.123 56.712 26.725 ;
     RECT  9.36 26.149 16.872 26.819 ;
     RECT  36.96 26.725 41.592 26.819 ;
     RECT  28.272 26.243 28.296 26.867 ;
     RECT  54.96 26.725 56.712 27.011 ;
     RECT  29.4 26.629 35.736 27.061 ;
     RECT  43.056 25.715 43.08 27.061 ;
     RECT  44.112 26.243 53.784 27.061 ;
     RECT  17.856 26.725 25.272 27.107 ;
     RECT  36.96 26.819 38.232 27.301 ;
     RECT  61.248 26.245 62.112 27.301 ;
     RECT  43.056 27.061 53.784 27.349 ;
     RECT  9.36 26.819 12.072 27.395 ;
     RECT  13.2 26.819 16.44 27.395 ;
     RECT  29.4 27.061 35.88 27.395 ;
     RECT  42.96 27.349 53.784 27.395 ;
     RECT  29.4 27.395 30.648 27.445 ;
     RECT  39.264 26.819 41.592 27.781 ;
     RECT  55.008 27.011 56.712 27.829 ;
     RECT  32.256 27.395 35.88 27.877 ;
     RECT  36.912 27.301 38.232 27.877 ;
     RECT  9.648 27.395 12.072 27.971 ;
     RECT  42.96 27.395 53.064 27.971 ;
     RECT  22.752 27.107 25.272 28.021 ;
     RECT  26.256 26.243 27.096 28.021 ;
     RECT  29.28 27.445 30.648 28.069 ;
     RECT  10.8 27.971 12.072 28.165 ;
     RECT  13.2 27.395 13.512 28.165 ;
     RECT  55.008 27.829 56.808 28.165 ;
     RECT  5.52 16.019 8.112 28.309 ;
     RECT  54.72 28.165 56.808 28.309 ;
     RECT  32.256 27.877 38.232 28.357 ;
     RECT  22.752 28.021 27.096 28.403 ;
     RECT  10.8 28.165 13.512 28.501 ;
     RECT  14.496 27.395 16.44 28.501 ;
     RECT  10.8 28.501 16.44 28.547 ;
     RECT  17.856 27.107 21.672 28.549 ;
     RECT  16.848 28.549 21.672 28.595 ;
     RECT  31.824 28.357 38.232 28.597 ;
     RECT  39.264 27.781 41.976 28.597 ;
     RECT  31.728 28.597 41.976 28.643 ;
     RECT  54.72 28.309 56.856 28.643 ;
     RECT  22.752 28.403 26.28 28.691 ;
     RECT  38.64 28.643 41.976 28.693 ;
     RECT  42.96 27.971 53.016 28.693 ;
     RECT  31.728 28.643 37.464 29.027 ;
     RECT  38.64 28.693 53.016 29.171 ;
     RECT  43.824 29.171 53.016 29.219 ;
     RECT  54.72 28.643 56.808 29.219 ;
     RECT  29.232 28.069 30.648 29.221 ;
     RECT  59.568 27.925 59.592 29.269 ;
     RECT  61.152 27.301 62.112 29.269 ;
     RECT  21.552 28.595 21.672 29.509 ;
     RECT  22.752 28.691 25.512 29.509 ;
     RECT  29.04 29.221 30.648 29.555 ;
     RECT  16.848 28.595 19.992 29.605 ;
     RECT  11.184 28.547 15.624 29.651 ;
     RECT  5.52 28.309 8.232 29.653 ;
     RECT  9.408 29.605 9.432 29.653 ;
     RECT  21.552 29.509 25.512 29.653 ;
     RECT  5.52 29.653 9.432 29.699 ;
     RECT  11.184 29.651 15.48 29.699 ;
     RECT  21.216 29.653 25.512 29.795 ;
     RECT  49.872 29.219 53.016 29.795 ;
     RECT  16.608 29.605 19.992 30.037 ;
     RECT  55.44 29.219 56.808 30.037 ;
     RECT  55.44 30.037 57.096 30.085 ;
     RECT  58.08 29.509 58.104 30.085 ;
     RECT  7.8 29.699 9.432 30.181 ;
     RECT  16.608 30.037 20.184 30.181 ;
     RECT  43.824 29.219 48.504 30.181 ;
     RECT  59.568 29.269 62.112 30.181 ;
     RECT  59.568 30.181 62.664 30.229 ;
     RECT  5.52 29.699 5.88 30.275 ;
     RECT  29.04 29.555 29.832 30.275 ;
     RECT  11.184 29.699 15.336 30.323 ;
     RECT  38.64 29.171 42.792 30.563 ;
     RECT  38.832 30.563 42.792 30.613 ;
     RECT  11.568 30.323 15.336 30.659 ;
     RECT  16.608 30.181 20.424 30.709 ;
     RECT  38.832 30.613 42.84 30.755 ;
     RECT  38.832 30.755 42.744 30.803 ;
     RECT  7.8 30.181 9.672 30.805 ;
     RECT  50.4 29.795 53.016 30.899 ;
     RECT  31.728 29.027 37.368 31.237 ;
     RECT  7.44 30.805 9.672 31.285 ;
     RECT  7.44 31.285 10.344 31.909 ;
     RECT  38.832 30.803 42.696 31.909 ;
     RECT  43.824 30.181 48.552 31.909 ;
     RECT  50.832 30.899 53.016 31.909 ;
     RECT  54.24 29.941 54.264 31.909 ;
     RECT  55.44 30.085 58.104 31.909 ;
     RECT  59.376 30.229 62.664 31.909 ;
     RECT  11.568 30.659 14.904 31.957 ;
     RECT  16.08 30.709 20.424 31.957 ;
     RECT  21.408 29.795 25.512 31.957 ;
     RECT  29.136 30.275 29.832 31.957 ;
     RECT  31.728 31.237 37.8 31.957 ;
     RECT  38.832 31.909 48.84 31.957 ;
     RECT  49.968 31.909 64.584 31.957 ;
     RECT  7.44 31.909 10.536 32.005 ;
     RECT  11.568 31.957 29.832 32.005 ;
     RECT  31.152 31.957 48.84 32.005 ;
     RECT  49.968 31.957 64.68 32.341 ;
     RECT  31.152 32.005 48.936 32.389 ;
     RECT  49.968 32.341 64.968 32.389 ;
     RECT  2.4 10.883 2.712 32.409 ;
     RECT  2.4 32.409 2.52 32.423 ;
     RECT  7.44 32.005 29.832 32.531 ;
     RECT  31.152 32.389 65.256 33.013 ;
     RECT  30.96 33.013 65.256 33.061 ;
     RECT  7.728 32.531 29.832 33.637 ;
     RECT  30.864 33.061 65.256 33.637 ;
     RECT  7.728 33.637 65.256 34.451 ;
     RECT  7.728 34.451 62.184 34.512 ;
     RECT  63.408 34.451 65.256 34.512 ;
     RECT  38.184 0.563 39.216 1.763 ;
     RECT  38.184 1.763 39.312 1.859 ;
     RECT  37.992 1.859 39.408 2.869 ;
     RECT  58.344 2.195 59.808 2.483 ;
     RECT  57.384 2.483 57.48 3.877 ;
     RECT  37.992 2.869 39.216 3.157 ;
     RECT  37.992 3.157 39.168 3.349 ;
     RECT  4.944 4.019 5.52 5.365 ;
     RECT  4.944 6.419 5.52 6.709 ;
     RECT  4.488 6.709 5.52 8.003 ;
     RECT  4.464 8.003 5.52 8.965 ;
     RECT  4.464 8.965 5.184 9.061 ;
     RECT  2.712 9.061 3.936 9.973 ;
     RECT  3.96 9.061 5.184 10.019 ;
     RECT  16.872 9.731 17.856 26.819 ;
     RECT  33.528 9.731 34.512 11.459 ;
     RECT  24.648 9.779 25.68 10.115 ;
     RECT  47.016 10.259 48 13.523 ;
     RECT  31.08 10.499 32.16 10.883 ;
     RECT  8.376 10.835 9.36 14.291 ;
     RECT  21.672 10.883 22.896 11.171 ;
     RECT  31.08 10.883 32.256 11.459 ;
     RECT  21.576 11.171 22.896 12.757 ;
     RECT  13.512 11.219 14.544 26.149 ;
     RECT  30.984 11.459 32.256 11.507 ;
     RECT  33.48 11.459 34.512 15.443 ;
     RECT  21.912 12.757 22.896 17.411 ;
     RECT  46.872 13.523 48 17.365 ;
     RECT  8.28 14.291 9.36 16.019 ;
     RECT  36.072 14.867 37.248 15.443 ;
     RECT  8.112 16.019 9.36 27.395 ;
     RECT  53.784 16.883 54.816 17.507 ;
     RECT  47.016 17.365 48 19.285 ;
     RECT  21.816 17.411 22.896 21.637 ;
     RECT  53.784 17.507 55.008 25.621 ;
     RECT  27.096 18.515 28.272 26.867 ;
     RECT  37.368 19.667 38.496 21.011 ;
     RECT  41.496 19.909 42.72 25.475 ;
     RECT  55.032 20.963 56.112 21.443 ;
     RECT  25.272 20.965 26.256 25.957 ;
     RECT  37.368 21.011 38.544 21.491 ;
     RECT  35.112 21.013 36.384 25.093 ;
     RECT  33.336 21.061 34.8 26.293 ;
     RECT  55.032 21.443 56.304 23.123 ;
     RECT  37.176 21.491 38.544 21.971 ;
     RECT  20.904 21.779 22.128 26.725 ;
     RECT  55.032 23.123 56.4 26.725 ;
     RECT  35.736 25.235 36.768 25.715 ;
     RECT  41.496 25.475 43.056 26.725 ;
     RECT  35.736 25.715 36.96 27.061 ;
     RECT  43.08 25.715 44.112 27.061 ;
     RECT  38.232 25.717 39.264 26.101 ;
     RECT  25.272 26.243 26.256 28.021 ;
     RECT  28.296 26.243 29.4 26.867 ;
     RECT  53.784 26.243 54.96 27.011 ;
     RECT  33.72 26.293 34.8 26.437 ;
     RECT  41.592 26.725 43.056 27.349 ;
     RECT  12.072 26.819 13.2 28.165 ;
     RECT  16.44 26.819 17.856 28.547 ;
     RECT  38.232 26.819 39.264 28.597 ;
     RECT  29.232 26.867 29.4 27.445 ;
     RECT  53.784 27.011 55.008 27.395 ;
     RECT  35.88 27.061 36.96 27.301 ;
     RECT  21.672 27.107 22.752 29.509 ;
     RECT  35.88 27.301 36.912 27.877 ;
     RECT  41.592 27.349 42.96 27.781 ;
     RECT  8.112 27.395 9.648 27.971 ;
     RECT  13.512 27.395 14.496 28.501 ;
     RECT  30.648 27.395 32.256 28.357 ;
     RECT  54.72 27.395 55.008 28.165 ;
     RECT  29.232 27.445 29.28 28.069 ;
     RECT  41.976 27.781 42.96 28.693 ;
     RECT  8.112 27.971 8.232 28.309 ;
     RECT  30.648 28.357 31.824 28.597 ;
     RECT  15.624 28.547 17.856 28.549 ;
     RECT  15.624 28.549 16.848 29.605 ;
     RECT  19.992 28.595 21.552 29.653 ;
     RECT  30.648 28.597 31.728 29.555 ;
     RECT  37.464 28.643 38.64 29.027 ;
     RECT  56.808 28.643 56.856 29.509 ;
     RECT  37.368 29.027 38.64 30.563 ;
     RECT  42.792 29.171 43.824 30.613 ;
     RECT  48.504 29.219 49.872 29.795 ;
     RECT  54.72 29.219 55.44 29.941 ;
     RECT  56.808 29.509 58.08 30.037 ;
     RECT  58.104 29.509 59.568 30.229 ;
     RECT  8.232 29.605 9.408 29.653 ;
     RECT  15.624 29.605 16.608 29.651 ;
     RECT  15.48 29.651 16.608 29.699 ;
     RECT  19.992 29.653 21.216 29.795 ;
     RECT  7.44 29.699 7.8 30.805 ;
     RECT  15.336 29.699 16.608 30.659 ;
     RECT  19.992 29.795 21.408 30.037 ;
     RECT  48.504 29.795 48.552 30.181 ;
     RECT  53.016 29.941 54.24 31.909 ;
     RECT  54.264 29.941 55.44 31.909 ;
     RECT  20.184 30.037 21.408 30.181 ;
     RECT  57.096 30.037 58.08 30.085 ;
     RECT  9.672 30.181 11.184 30.323 ;
     RECT  20.424 30.181 21.408 31.957 ;
     RECT  58.104 30.229 59.376 31.909 ;
     RECT  9.672 30.323 11.568 31.285 ;
     RECT  37.368 30.563 38.832 31.237 ;
     RECT  42.84 30.613 43.824 30.755 ;
     RECT  14.904 30.659 16.608 30.709 ;
     RECT  14.904 30.709 16.08 31.957 ;
     RECT  42.744 30.755 43.824 30.803 ;
     RECT  42.696 30.803 43.824 31.909 ;
     RECT  50.4 30.899 50.832 31.909 ;
     RECT  37.8 31.237 38.832 31.957 ;
     RECT  10.344 31.285 11.568 31.909 ;
     RECT  10.536 31.909 11.568 32.005 ;
     RECT  48.84 31.909 49.968 32.005 ;
     RECT  29.832 31.957 31.152 33.013 ;
     RECT  48.936 32.005 49.968 32.389 ;
     RECT  29.832 33.013 30.96 33.061 ;
     RECT  29.832 33.061 30.864 33.637 ;
     RECT  62.232 34.451 63.36 34.512 ;
  END
END dsfd_coll_ceso
END LIBRARY
